VERSION 5.8 ;
BUSBITCHARS "[]" ;
DIVIDERCHAR "/" ;
UNITS
    DATABASE MICRONS 1000 ;
END UNITS

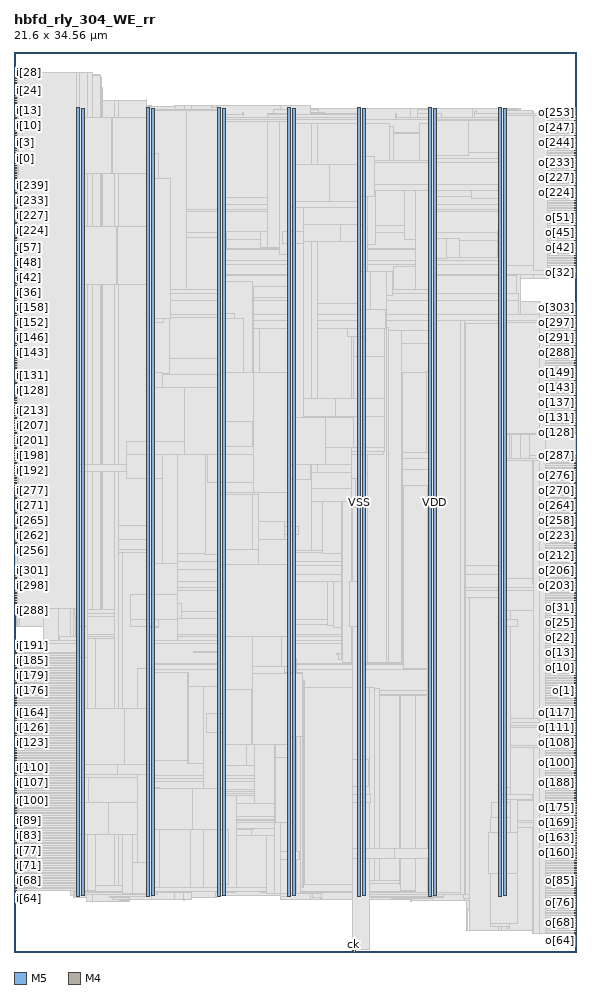
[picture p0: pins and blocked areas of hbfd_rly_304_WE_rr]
MACRO hbfd_rly_304_WE_rr
  FOREIGN hbfd_rly_304_WE_rr 0 0 ;
  CLASS BLOCK ;
  SIZE 21.6 BY 34.56 ;
  PIN ck
    DIRECTION INPUT ;
    USE SIGNAL ;
    PORT
      LAYER M5 ;
        RECT  13.008 0 13.032 0.084 ;
    END
  END ck
  PIN i[0]
    DIRECTION INPUT ;
    USE SIGNAL ;
    PORT
      LAYER M4 ;
        RECT  0 30.768 0.084 30.792 ;
    END
  END i[0]
  PIN i[100]
    DIRECTION INPUT ;
    USE SIGNAL ;
    PORT
      LAYER M4 ;
        RECT  0 5.808 0.084 5.832 ;
    END
  END i[100]
  PIN i[101]
    DIRECTION INPUT ;
    USE SIGNAL ;
    PORT
      LAYER M4 ;
        RECT  0 5.904 0.084 5.928 ;
    END
  END i[101]
  PIN i[102]
    DIRECTION INPUT ;
    USE SIGNAL ;
    PORT
      LAYER M4 ;
        RECT  0 6 0.084 6.024 ;
    END
  END i[102]
  PIN i[103]
    DIRECTION INPUT ;
    USE SIGNAL ;
    PORT
      LAYER M4 ;
        RECT  0 6.096 0.084 6.12 ;
    END
  END i[103]
  PIN i[104]
    DIRECTION INPUT ;
    USE SIGNAL ;
    PORT
      LAYER M4 ;
        RECT  0 6.192 0.084 6.216 ;
    END
  END i[104]
  PIN i[105]
    DIRECTION INPUT ;
    USE SIGNAL ;
    PORT
      LAYER M4 ;
        RECT  0 6.288 0.084 6.312 ;
    END
  END i[105]
  PIN i[106]
    DIRECTION INPUT ;
    USE SIGNAL ;
    PORT
      LAYER M4 ;
        RECT  0 6.384 0.084 6.408 ;
    END
  END i[106]
  PIN i[107]
    DIRECTION INPUT ;
    USE SIGNAL ;
    PORT
      LAYER M4 ;
        RECT  0 6.48 0.084 6.504 ;
    END
  END i[107]
  PIN i[108]
    DIRECTION INPUT ;
    USE SIGNAL ;
    PORT
      LAYER M4 ;
        RECT  0 6.576 0.084 6.6 ;
    END
  END i[108]
  PIN i[109]
    DIRECTION INPUT ;
    USE SIGNAL ;
    PORT
      LAYER M4 ;
        RECT  0 6.672 0.084 6.696 ;
    END
  END i[109]
  PIN i[10]
    DIRECTION INPUT ;
    USE SIGNAL ;
    PORT
      LAYER M4 ;
        RECT  0 31.728 0.084 31.752 ;
    END
  END i[10]
  PIN i[110]
    DIRECTION INPUT ;
    USE SIGNAL ;
    PORT
      LAYER M4 ;
        RECT  0 6.768 0.084 6.792 ;
    END
  END i[110]
  PIN i[111]
    DIRECTION INPUT ;
    USE SIGNAL ;
    PORT
      LAYER M4 ;
        RECT  0 6.864 0.084 6.888 ;
    END
  END i[111]
  PIN i[112]
    DIRECTION INPUT ;
    USE SIGNAL ;
    PORT
      LAYER M4 ;
        RECT  0 6.96 0.084 6.984 ;
    END
  END i[112]
  PIN i[113]
    DIRECTION INPUT ;
    USE SIGNAL ;
    PORT
      LAYER M4 ;
        RECT  0 7.056 0.084 7.08 ;
    END
  END i[113]
  PIN i[114]
    DIRECTION INPUT ;
    USE SIGNAL ;
    PORT
      LAYER M4 ;
        RECT  0 7.152 0.084 7.176 ;
    END
  END i[114]
  PIN i[115]
    DIRECTION INPUT ;
    USE SIGNAL ;
    PORT
      LAYER M4 ;
        RECT  0 7.248 0.084 7.272 ;
    END
  END i[115]
  PIN i[116]
    DIRECTION INPUT ;
    USE SIGNAL ;
    PORT
      LAYER M4 ;
        RECT  0 7.344 0.084 7.368 ;
    END
  END i[116]
  PIN i[117]
    DIRECTION INPUT ;
    USE SIGNAL ;
    PORT
      LAYER M4 ;
        RECT  0 7.44 0.084 7.464 ;
    END
  END i[117]
  PIN i[118]
    DIRECTION INPUT ;
    USE SIGNAL ;
    PORT
      LAYER M4 ;
        RECT  0 7.536 0.084 7.56 ;
    END
  END i[118]
  PIN i[119]
    DIRECTION INPUT ;
    USE SIGNAL ;
    PORT
      LAYER M4 ;
        RECT  0 7.632 0.084 7.656 ;
    END
  END i[119]
  PIN i[11]
    DIRECTION INPUT ;
    USE SIGNAL ;
    PORT
      LAYER M4 ;
        RECT  0 31.824 0.084 31.848 ;
    END
  END i[11]
  PIN i[120]
    DIRECTION INPUT ;
    USE SIGNAL ;
    PORT
      LAYER M4 ;
        RECT  0 7.728 0.084 7.752 ;
    END
  END i[120]
  PIN i[121]
    DIRECTION INPUT ;
    USE SIGNAL ;
    PORT
      LAYER M4 ;
        RECT  0 7.824 0.084 7.848 ;
    END
  END i[121]
  PIN i[122]
    DIRECTION INPUT ;
    USE SIGNAL ;
    PORT
      LAYER M4 ;
        RECT  0 7.92 0.084 7.944 ;
    END
  END i[122]
  PIN i[123]
    DIRECTION INPUT ;
    USE SIGNAL ;
    PORT
      LAYER M4 ;
        RECT  0 8.016 0.084 8.04 ;
    END
  END i[123]
  PIN i[124]
    DIRECTION INPUT ;
    USE SIGNAL ;
    PORT
      LAYER M4 ;
        RECT  0 8.112 0.084 8.136 ;
    END
  END i[124]
  PIN i[125]
    DIRECTION INPUT ;
    USE SIGNAL ;
    PORT
      LAYER M4 ;
        RECT  0 8.208 0.084 8.232 ;
    END
  END i[125]
  PIN i[126]
    DIRECTION INPUT ;
    USE SIGNAL ;
    PORT
      LAYER M4 ;
        RECT  0 8.304 0.084 8.328 ;
    END
  END i[126]
  PIN i[127]
    DIRECTION INPUT ;
    USE SIGNAL ;
    PORT
      LAYER M4 ;
        RECT  0 8.4 0.084 8.424 ;
    END
  END i[127]
  PIN i[128]
    DIRECTION INPUT ;
    USE SIGNAL ;
    PORT
      LAYER M4 ;
        RECT  0 21.552 0.084 21.576 ;
    END
  END i[128]
  PIN i[129]
    DIRECTION INPUT ;
    USE SIGNAL ;
    PORT
      LAYER M4 ;
        RECT  0 21.648 0.084 21.672 ;
    END
  END i[129]
  PIN i[12]
    DIRECTION INPUT ;
    USE SIGNAL ;
    PORT
      LAYER M4 ;
        RECT  0 31.92 0.084 31.944 ;
    END
  END i[12]
  PIN i[130]
    DIRECTION INPUT ;
    USE SIGNAL ;
    PORT
      LAYER M4 ;
        RECT  0 21.744 0.084 21.768 ;
    END
  END i[130]
  PIN i[131]
    DIRECTION INPUT ;
    USE SIGNAL ;
    PORT
      LAYER M4 ;
        RECT  0 21.84 0.084 21.864 ;
    END
  END i[131]
  PIN i[132]
    DIRECTION INPUT ;
    USE SIGNAL ;
    PORT
      LAYER M4 ;
        RECT  0 21.936 0.084 21.96 ;
    END
  END i[132]
  PIN i[133]
    DIRECTION INPUT ;
    USE SIGNAL ;
    PORT
      LAYER M4 ;
        RECT  0 22.032 0.084 22.056 ;
    END
  END i[133]
  PIN i[134]
    DIRECTION INPUT ;
    USE SIGNAL ;
    PORT
      LAYER M4 ;
        RECT  0 22.128 0.084 22.152 ;
    END
  END i[134]
  PIN i[135]
    DIRECTION INPUT ;
    USE SIGNAL ;
    PORT
      LAYER M4 ;
        RECT  0 22.224 0.084 22.248 ;
    END
  END i[135]
  PIN i[136]
    DIRECTION INPUT ;
    USE SIGNAL ;
    PORT
      LAYER M4 ;
        RECT  0 22.32 0.084 22.344 ;
    END
  END i[136]
  PIN i[137]
    DIRECTION INPUT ;
    USE SIGNAL ;
    PORT
      LAYER M4 ;
        RECT  0 22.416 0.084 22.44 ;
    END
  END i[137]
  PIN i[138]
    DIRECTION INPUT ;
    USE SIGNAL ;
    PORT
      LAYER M4 ;
        RECT  0 22.512 0.084 22.536 ;
    END
  END i[138]
  PIN i[139]
    DIRECTION INPUT ;
    USE SIGNAL ;
    PORT
      LAYER M4 ;
        RECT  0 22.608 0.084 22.632 ;
    END
  END i[139]
  PIN i[13]
    DIRECTION INPUT ;
    USE SIGNAL ;
    PORT
      LAYER M4 ;
        RECT  0 32.016 0.084 32.04 ;
    END
  END i[13]
  PIN i[140]
    DIRECTION INPUT ;
    USE SIGNAL ;
    PORT
      LAYER M4 ;
        RECT  0 22.704 0.084 22.728 ;
    END
  END i[140]
  PIN i[141]
    DIRECTION INPUT ;
    USE SIGNAL ;
    PORT
      LAYER M4 ;
        RECT  0 22.8 0.084 22.824 ;
    END
  END i[141]
  PIN i[142]
    DIRECTION INPUT ;
    USE SIGNAL ;
    PORT
      LAYER M4 ;
        RECT  0 22.896 0.084 22.92 ;
    END
  END i[142]
  PIN i[143]
    DIRECTION INPUT ;
    USE SIGNAL ;
    PORT
      LAYER M4 ;
        RECT  0 22.992 0.084 23.016 ;
    END
  END i[143]
  PIN i[144]
    DIRECTION INPUT ;
    USE SIGNAL ;
    PORT
      LAYER M4 ;
        RECT  0 23.088 0.084 23.112 ;
    END
  END i[144]
  PIN i[145]
    DIRECTION INPUT ;
    USE SIGNAL ;
    PORT
      LAYER M4 ;
        RECT  0 23.184 0.084 23.208 ;
    END
  END i[145]
  PIN i[146]
    DIRECTION INPUT ;
    USE SIGNAL ;
    PORT
      LAYER M4 ;
        RECT  0 23.28 0.084 23.304 ;
    END
  END i[146]
  PIN i[147]
    DIRECTION INPUT ;
    USE SIGNAL ;
    PORT
      LAYER M4 ;
        RECT  0 23.376 0.084 23.4 ;
    END
  END i[147]
  PIN i[148]
    DIRECTION INPUT ;
    USE SIGNAL ;
    PORT
      LAYER M4 ;
        RECT  0 23.472 0.084 23.496 ;
    END
  END i[148]
  PIN i[149]
    DIRECTION INPUT ;
    USE SIGNAL ;
    PORT
      LAYER M4 ;
        RECT  0 23.568 0.084 23.592 ;
    END
  END i[149]
  PIN i[14]
    DIRECTION INPUT ;
    USE SIGNAL ;
    PORT
      LAYER M4 ;
        RECT  0 32.112 0.084 32.136 ;
    END
  END i[14]
  PIN i[150]
    DIRECTION INPUT ;
    USE SIGNAL ;
    PORT
      LAYER M4 ;
        RECT  0 23.664 0.084 23.688 ;
    END
  END i[150]
  PIN i[151]
    DIRECTION INPUT ;
    USE SIGNAL ;
    PORT
      LAYER M4 ;
        RECT  0 23.76 0.084 23.784 ;
    END
  END i[151]
  PIN i[152]
    DIRECTION INPUT ;
    USE SIGNAL ;
    PORT
      LAYER M4 ;
        RECT  0 23.856 0.084 23.88 ;
    END
  END i[152]
  PIN i[153]
    DIRECTION INPUT ;
    USE SIGNAL ;
    PORT
      LAYER M4 ;
        RECT  0 23.952 0.084 23.976 ;
    END
  END i[153]
  PIN i[154]
    DIRECTION INPUT ;
    USE SIGNAL ;
    PORT
      LAYER M4 ;
        RECT  0 24.048 0.084 24.072 ;
    END
  END i[154]
  PIN i[155]
    DIRECTION INPUT ;
    USE SIGNAL ;
    PORT
      LAYER M4 ;
        RECT  0 24.144 0.084 24.168 ;
    END
  END i[155]
  PIN i[156]
    DIRECTION INPUT ;
    USE SIGNAL ;
    PORT
      LAYER M4 ;
        RECT  0 24.24 0.084 24.264 ;
    END
  END i[156]
  PIN i[157]
    DIRECTION INPUT ;
    USE SIGNAL ;
    PORT
      LAYER M4 ;
        RECT  0 24.336 0.084 24.36 ;
    END
  END i[157]
  PIN i[158]
    DIRECTION INPUT ;
    USE SIGNAL ;
    PORT
      LAYER M4 ;
        RECT  0 24.432 0.084 24.456 ;
    END
  END i[158]
  PIN i[159]
    DIRECTION INPUT ;
    USE SIGNAL ;
    PORT
      LAYER M4 ;
        RECT  0 24.528 0.084 24.552 ;
    END
  END i[159]
  PIN i[15]
    DIRECTION INPUT ;
    USE SIGNAL ;
    PORT
      LAYER M4 ;
        RECT  0 32.208 0.084 32.232 ;
    END
  END i[15]
  PIN i[160]
    DIRECTION INPUT ;
    USE SIGNAL ;
    PORT
      LAYER M4 ;
        RECT  0 8.496 0.084 8.52 ;
    END
  END i[160]
  PIN i[161]
    DIRECTION INPUT ;
    USE SIGNAL ;
    PORT
      LAYER M4 ;
        RECT  0 8.592 0.084 8.616 ;
    END
  END i[161]
  PIN i[162]
    DIRECTION INPUT ;
    USE SIGNAL ;
    PORT
      LAYER M4 ;
        RECT  0 8.688 0.084 8.712 ;
    END
  END i[162]
  PIN i[163]
    DIRECTION INPUT ;
    USE SIGNAL ;
    PORT
      LAYER M4 ;
        RECT  0 8.784 0.084 8.808 ;
    END
  END i[163]
  PIN i[164]
    DIRECTION INPUT ;
    USE SIGNAL ;
    PORT
      LAYER M4 ;
        RECT  0 8.88 0.084 8.904 ;
    END
  END i[164]
  PIN i[165]
    DIRECTION INPUT ;
    USE SIGNAL ;
    PORT
      LAYER M4 ;
        RECT  0 8.976 0.084 9 ;
    END
  END i[165]
  PIN i[166]
    DIRECTION INPUT ;
    USE SIGNAL ;
    PORT
      LAYER M4 ;
        RECT  0 9.072 0.084 9.096 ;
    END
  END i[166]
  PIN i[167]
    DIRECTION INPUT ;
    USE SIGNAL ;
    PORT
      LAYER M4 ;
        RECT  0 9.168 0.084 9.192 ;
    END
  END i[167]
  PIN i[168]
    DIRECTION INPUT ;
    USE SIGNAL ;
    PORT
      LAYER M4 ;
        RECT  0 9.264 0.084 9.288 ;
    END
  END i[168]
  PIN i[169]
    DIRECTION INPUT ;
    USE SIGNAL ;
    PORT
      LAYER M4 ;
        RECT  0 9.36 0.084 9.384 ;
    END
  END i[169]
  PIN i[16]
    DIRECTION INPUT ;
    USE SIGNAL ;
    PORT
      LAYER M4 ;
        RECT  0 32.304 0.084 32.328 ;
    END
  END i[16]
  PIN i[170]
    DIRECTION INPUT ;
    USE SIGNAL ;
    PORT
      LAYER M4 ;
        RECT  0 9.456 0.084 9.48 ;
    END
  END i[170]
  PIN i[171]
    DIRECTION INPUT ;
    USE SIGNAL ;
    PORT
      LAYER M4 ;
        RECT  0 9.552 0.084 9.576 ;
    END
  END i[171]
  PIN i[172]
    DIRECTION INPUT ;
    USE SIGNAL ;
    PORT
      LAYER M4 ;
        RECT  0 9.648 0.084 9.672 ;
    END
  END i[172]
  PIN i[173]
    DIRECTION INPUT ;
    USE SIGNAL ;
    PORT
      LAYER M4 ;
        RECT  0 9.744 0.084 9.768 ;
    END
  END i[173]
  PIN i[174]
    DIRECTION INPUT ;
    USE SIGNAL ;
    PORT
      LAYER M4 ;
        RECT  0 9.84 0.084 9.864 ;
    END
  END i[174]
  PIN i[175]
    DIRECTION INPUT ;
    USE SIGNAL ;
    PORT
      LAYER M4 ;
        RECT  0 9.936 0.084 9.96 ;
    END
  END i[175]
  PIN i[176]
    DIRECTION INPUT ;
    USE SIGNAL ;
    PORT
      LAYER M4 ;
        RECT  0 10.032 0.084 10.056 ;
    END
  END i[176]
  PIN i[177]
    DIRECTION INPUT ;
    USE SIGNAL ;
    PORT
      LAYER M4 ;
        RECT  0 10.128 0.084 10.152 ;
    END
  END i[177]
  PIN i[178]
    DIRECTION INPUT ;
    USE SIGNAL ;
    PORT
      LAYER M4 ;
        RECT  0 10.224 0.084 10.248 ;
    END
  END i[178]
  PIN i[179]
    DIRECTION INPUT ;
    USE SIGNAL ;
    PORT
      LAYER M4 ;
        RECT  0 10.32 0.084 10.344 ;
    END
  END i[179]
  PIN i[17]
    DIRECTION INPUT ;
    USE SIGNAL ;
    PORT
      LAYER M4 ;
        RECT  0 32.4 0.084 32.424 ;
    END
  END i[17]
  PIN i[180]
    DIRECTION INPUT ;
    USE SIGNAL ;
    PORT
      LAYER M4 ;
        RECT  0 10.416 0.084 10.44 ;
    END
  END i[180]
  PIN i[181]
    DIRECTION INPUT ;
    USE SIGNAL ;
    PORT
      LAYER M4 ;
        RECT  0 10.512 0.084 10.536 ;
    END
  END i[181]
  PIN i[182]
    DIRECTION INPUT ;
    USE SIGNAL ;
    PORT
      LAYER M4 ;
        RECT  0 10.608 0.084 10.632 ;
    END
  END i[182]
  PIN i[183]
    DIRECTION INPUT ;
    USE SIGNAL ;
    PORT
      LAYER M4 ;
        RECT  0 10.704 0.084 10.728 ;
    END
  END i[183]
  PIN i[184]
    DIRECTION INPUT ;
    USE SIGNAL ;
    PORT
      LAYER M4 ;
        RECT  0 10.8 0.084 10.824 ;
    END
  END i[184]
  PIN i[185]
    DIRECTION INPUT ;
    USE SIGNAL ;
    PORT
      LAYER M4 ;
        RECT  0 10.896 0.084 10.92 ;
    END
  END i[185]
  PIN i[186]
    DIRECTION INPUT ;
    USE SIGNAL ;
    PORT
      LAYER M4 ;
        RECT  0 10.992 0.084 11.016 ;
    END
  END i[186]
  PIN i[187]
    DIRECTION INPUT ;
    USE SIGNAL ;
    PORT
      LAYER M4 ;
        RECT  0 11.088 0.084 11.112 ;
    END
  END i[187]
  PIN i[188]
    DIRECTION INPUT ;
    USE SIGNAL ;
    PORT
      LAYER M4 ;
        RECT  0 11.184 0.084 11.208 ;
    END
  END i[188]
  PIN i[189]
    DIRECTION INPUT ;
    USE SIGNAL ;
    PORT
      LAYER M4 ;
        RECT  0 11.28 0.084 11.304 ;
    END
  END i[189]
  PIN i[18]
    DIRECTION INPUT ;
    USE SIGNAL ;
    PORT
      LAYER M4 ;
        RECT  0 32.496 0.084 32.52 ;
    END
  END i[18]
  PIN i[190]
    DIRECTION INPUT ;
    USE SIGNAL ;
    PORT
      LAYER M4 ;
        RECT  0 11.376 0.084 11.4 ;
    END
  END i[190]
  PIN i[191]
    DIRECTION INPUT ;
    USE SIGNAL ;
    PORT
      LAYER M4 ;
        RECT  0 11.472 0.084 11.496 ;
    END
  END i[191]
  PIN i[192]
    DIRECTION INPUT ;
    USE SIGNAL ;
    PORT
      LAYER M4 ;
        RECT  0 18.48 0.084 18.504 ;
    END
  END i[192]
  PIN i[193]
    DIRECTION INPUT ;
    USE SIGNAL ;
    PORT
      LAYER M4 ;
        RECT  0 18.576 0.084 18.6 ;
    END
  END i[193]
  PIN i[194]
    DIRECTION INPUT ;
    USE SIGNAL ;
    PORT
      LAYER M4 ;
        RECT  0 18.672 0.084 18.696 ;
    END
  END i[194]
  PIN i[195]
    DIRECTION INPUT ;
    USE SIGNAL ;
    PORT
      LAYER M4 ;
        RECT  0 18.768 0.084 18.792 ;
    END
  END i[195]
  PIN i[196]
    DIRECTION INPUT ;
    USE SIGNAL ;
    PORT
      LAYER M4 ;
        RECT  0 18.864 0.084 18.888 ;
    END
  END i[196]
  PIN i[197]
    DIRECTION INPUT ;
    USE SIGNAL ;
    PORT
      LAYER M4 ;
        RECT  0 18.96 0.084 18.984 ;
    END
  END i[197]
  PIN i[198]
    DIRECTION INPUT ;
    USE SIGNAL ;
    PORT
      LAYER M4 ;
        RECT  0 19.056 0.084 19.08 ;
    END
  END i[198]
  PIN i[199]
    DIRECTION INPUT ;
    USE SIGNAL ;
    PORT
      LAYER M4 ;
        RECT  0 19.152 0.084 19.176 ;
    END
  END i[199]
  PIN i[19]
    DIRECTION INPUT ;
    USE SIGNAL ;
    PORT
      LAYER M4 ;
        RECT  0 32.592 0.084 32.616 ;
    END
  END i[19]
  PIN i[1]
    DIRECTION INPUT ;
    USE SIGNAL ;
    PORT
      LAYER M4 ;
        RECT  0 30.864 0.084 30.888 ;
    END
  END i[1]
  PIN i[200]
    DIRECTION INPUT ;
    USE SIGNAL ;
    PORT
      LAYER M4 ;
        RECT  0 19.248 0.084 19.272 ;
    END
  END i[200]
  PIN i[201]
    DIRECTION INPUT ;
    USE SIGNAL ;
    PORT
      LAYER M4 ;
        RECT  0 19.344 0.084 19.368 ;
    END
  END i[201]
  PIN i[202]
    DIRECTION INPUT ;
    USE SIGNAL ;
    PORT
      LAYER M4 ;
        RECT  0 19.44 0.084 19.464 ;
    END
  END i[202]
  PIN i[203]
    DIRECTION INPUT ;
    USE SIGNAL ;
    PORT
      LAYER M4 ;
        RECT  0 19.536 0.084 19.56 ;
    END
  END i[203]
  PIN i[204]
    DIRECTION INPUT ;
    USE SIGNAL ;
    PORT
      LAYER M4 ;
        RECT  0 19.632 0.084 19.656 ;
    END
  END i[204]
  PIN i[205]
    DIRECTION INPUT ;
    USE SIGNAL ;
    PORT
      LAYER M4 ;
        RECT  0 19.728 0.084 19.752 ;
    END
  END i[205]
  PIN i[206]
    DIRECTION INPUT ;
    USE SIGNAL ;
    PORT
      LAYER M4 ;
        RECT  0 19.824 0.084 19.848 ;
    END
  END i[206]
  PIN i[207]
    DIRECTION INPUT ;
    USE SIGNAL ;
    PORT
      LAYER M4 ;
        RECT  0 19.92 0.084 19.944 ;
    END
  END i[207]
  PIN i[208]
    DIRECTION INPUT ;
    USE SIGNAL ;
    PORT
      LAYER M4 ;
        RECT  0 20.016 0.084 20.04 ;
    END
  END i[208]
  PIN i[209]
    DIRECTION INPUT ;
    USE SIGNAL ;
    PORT
      LAYER M4 ;
        RECT  0 20.112 0.084 20.136 ;
    END
  END i[209]
  PIN i[20]
    DIRECTION INPUT ;
    USE SIGNAL ;
    PORT
      LAYER M4 ;
        RECT  0 32.688 0.084 32.712 ;
    END
  END i[20]
  PIN i[210]
    DIRECTION INPUT ;
    USE SIGNAL ;
    PORT
      LAYER M4 ;
        RECT  0 20.208 0.084 20.232 ;
    END
  END i[210]
  PIN i[211]
    DIRECTION INPUT ;
    USE SIGNAL ;
    PORT
      LAYER M4 ;
        RECT  0 20.304 0.084 20.328 ;
    END
  END i[211]
  PIN i[212]
    DIRECTION INPUT ;
    USE SIGNAL ;
    PORT
      LAYER M4 ;
        RECT  0 20.4 0.084 20.424 ;
    END
  END i[212]
  PIN i[213]
    DIRECTION INPUT ;
    USE SIGNAL ;
    PORT
      LAYER M4 ;
        RECT  0 20.496 0.084 20.52 ;
    END
  END i[213]
  PIN i[214]
    DIRECTION INPUT ;
    USE SIGNAL ;
    PORT
      LAYER M4 ;
        RECT  0 20.592 0.084 20.616 ;
    END
  END i[214]
  PIN i[215]
    DIRECTION INPUT ;
    USE SIGNAL ;
    PORT
      LAYER M4 ;
        RECT  0 20.688 0.084 20.712 ;
    END
  END i[215]
  PIN i[216]
    DIRECTION INPUT ;
    USE SIGNAL ;
    PORT
      LAYER M4 ;
        RECT  0 20.784 0.084 20.808 ;
    END
  END i[216]
  PIN i[217]
    DIRECTION INPUT ;
    USE SIGNAL ;
    PORT
      LAYER M4 ;
        RECT  0 20.88 0.084 20.904 ;
    END
  END i[217]
  PIN i[218]
    DIRECTION INPUT ;
    USE SIGNAL ;
    PORT
      LAYER M4 ;
        RECT  0 20.976 0.084 21 ;
    END
  END i[218]
  PIN i[219]
    DIRECTION INPUT ;
    USE SIGNAL ;
    PORT
      LAYER M4 ;
        RECT  0 21.072 0.084 21.096 ;
    END
  END i[219]
  PIN i[21]
    DIRECTION INPUT ;
    USE SIGNAL ;
    PORT
      LAYER M4 ;
        RECT  0 32.784 0.084 32.808 ;
    END
  END i[21]
  PIN i[220]
    DIRECTION INPUT ;
    USE SIGNAL ;
    PORT
      LAYER M4 ;
        RECT  0 21.168 0.084 21.192 ;
    END
  END i[220]
  PIN i[221]
    DIRECTION INPUT ;
    USE SIGNAL ;
    PORT
      LAYER M4 ;
        RECT  0 21.264 0.084 21.288 ;
    END
  END i[221]
  PIN i[222]
    DIRECTION INPUT ;
    USE SIGNAL ;
    PORT
      LAYER M4 ;
        RECT  0 21.36 0.084 21.384 ;
    END
  END i[222]
  PIN i[223]
    DIRECTION INPUT ;
    USE SIGNAL ;
    PORT
      LAYER M4 ;
        RECT  0 21.456 0.084 21.48 ;
    END
  END i[223]
  PIN i[224]
    DIRECTION INPUT ;
    USE SIGNAL ;
    PORT
      LAYER M4 ;
        RECT  0 27.696 0.084 27.72 ;
    END
  END i[224]
  PIN i[225]
    DIRECTION INPUT ;
    USE SIGNAL ;
    PORT
      LAYER M4 ;
        RECT  0 27.792 0.084 27.816 ;
    END
  END i[225]
  PIN i[226]
    DIRECTION INPUT ;
    USE SIGNAL ;
    PORT
      LAYER M4 ;
        RECT  0 27.888 0.084 27.912 ;
    END
  END i[226]
  PIN i[227]
    DIRECTION INPUT ;
    USE SIGNAL ;
    PORT
      LAYER M4 ;
        RECT  0 27.984 0.084 28.008 ;
    END
  END i[227]
  PIN i[228]
    DIRECTION INPUT ;
    USE SIGNAL ;
    PORT
      LAYER M4 ;
        RECT  0 28.08 0.084 28.104 ;
    END
  END i[228]
  PIN i[229]
    DIRECTION INPUT ;
    USE SIGNAL ;
    PORT
      LAYER M4 ;
        RECT  0 28.176 0.084 28.2 ;
    END
  END i[229]
  PIN i[22]
    DIRECTION INPUT ;
    USE SIGNAL ;
    PORT
      LAYER M4 ;
        RECT  0 32.88 0.084 32.904 ;
    END
  END i[22]
  PIN i[230]
    DIRECTION INPUT ;
    USE SIGNAL ;
    PORT
      LAYER M4 ;
        RECT  0 28.272 0.084 28.296 ;
    END
  END i[230]
  PIN i[231]
    DIRECTION INPUT ;
    USE SIGNAL ;
    PORT
      LAYER M4 ;
        RECT  0 28.368 0.084 28.392 ;
    END
  END i[231]
  PIN i[232]
    DIRECTION INPUT ;
    USE SIGNAL ;
    PORT
      LAYER M4 ;
        RECT  0 28.464 0.084 28.488 ;
    END
  END i[232]
  PIN i[233]
    DIRECTION INPUT ;
    USE SIGNAL ;
    PORT
      LAYER M4 ;
        RECT  0 28.56 0.084 28.584 ;
    END
  END i[233]
  PIN i[234]
    DIRECTION INPUT ;
    USE SIGNAL ;
    PORT
      LAYER M4 ;
        RECT  0 28.656 0.084 28.68 ;
    END
  END i[234]
  PIN i[235]
    DIRECTION INPUT ;
    USE SIGNAL ;
    PORT
      LAYER M4 ;
        RECT  0 28.752 0.084 28.776 ;
    END
  END i[235]
  PIN i[236]
    DIRECTION INPUT ;
    USE SIGNAL ;
    PORT
      LAYER M4 ;
        RECT  0 28.848 0.084 28.872 ;
    END
  END i[236]
  PIN i[237]
    DIRECTION INPUT ;
    USE SIGNAL ;
    PORT
      LAYER M4 ;
        RECT  0 28.944 0.084 28.968 ;
    END
  END i[237]
  PIN i[238]
    DIRECTION INPUT ;
    USE SIGNAL ;
    PORT
      LAYER M4 ;
        RECT  0 29.04 0.084 29.064 ;
    END
  END i[238]
  PIN i[239]
    DIRECTION INPUT ;
    USE SIGNAL ;
    PORT
      LAYER M4 ;
        RECT  0 29.136 0.084 29.16 ;
    END
  END i[239]
  PIN i[23]
    DIRECTION INPUT ;
    USE SIGNAL ;
    PORT
      LAYER M4 ;
        RECT  0 32.976 0.084 33 ;
    END
  END i[23]
  PIN i[240]
    DIRECTION INPUT ;
    USE SIGNAL ;
    PORT
      LAYER M4 ;
        RECT  0 29.232 0.084 29.256 ;
    END
  END i[240]
  PIN i[241]
    DIRECTION INPUT ;
    USE SIGNAL ;
    PORT
      LAYER M4 ;
        RECT  0 29.328 0.084 29.352 ;
    END
  END i[241]
  PIN i[242]
    DIRECTION INPUT ;
    USE SIGNAL ;
    PORT
      LAYER M4 ;
        RECT  0 29.424 0.084 29.448 ;
    END
  END i[242]
  PIN i[243]
    DIRECTION INPUT ;
    USE SIGNAL ;
    PORT
      LAYER M4 ;
        RECT  0 29.52 0.084 29.544 ;
    END
  END i[243]
  PIN i[244]
    DIRECTION INPUT ;
    USE SIGNAL ;
    PORT
      LAYER M4 ;
        RECT  0 29.616 0.084 29.64 ;
    END
  END i[244]
  PIN i[245]
    DIRECTION INPUT ;
    USE SIGNAL ;
    PORT
      LAYER M4 ;
        RECT  0 29.712 0.084 29.736 ;
    END
  END i[245]
  PIN i[246]
    DIRECTION INPUT ;
    USE SIGNAL ;
    PORT
      LAYER M4 ;
        RECT  0 29.808 0.084 29.832 ;
    END
  END i[246]
  PIN i[247]
    DIRECTION INPUT ;
    USE SIGNAL ;
    PORT
      LAYER M4 ;
        RECT  0 29.904 0.084 29.928 ;
    END
  END i[247]
  PIN i[248]
    DIRECTION INPUT ;
    USE SIGNAL ;
    PORT
      LAYER M4 ;
        RECT  0 30 0.084 30.024 ;
    END
  END i[248]
  PIN i[249]
    DIRECTION INPUT ;
    USE SIGNAL ;
    PORT
      LAYER M4 ;
        RECT  0 30.096 0.084 30.12 ;
    END
  END i[249]
  PIN i[24]
    DIRECTION INPUT ;
    USE SIGNAL ;
    PORT
      LAYER M4 ;
        RECT  0 33.072 0.084 33.096 ;
    END
  END i[24]
  PIN i[250]
    DIRECTION INPUT ;
    USE SIGNAL ;
    PORT
      LAYER M4 ;
        RECT  0 30.192 0.084 30.216 ;
    END
  END i[250]
  PIN i[251]
    DIRECTION INPUT ;
    USE SIGNAL ;
    PORT
      LAYER M4 ;
        RECT  0 30.288 0.084 30.312 ;
    END
  END i[251]
  PIN i[252]
    DIRECTION INPUT ;
    USE SIGNAL ;
    PORT
      LAYER M4 ;
        RECT  0 30.384 0.084 30.408 ;
    END
  END i[252]
  PIN i[253]
    DIRECTION INPUT ;
    USE SIGNAL ;
    PORT
      LAYER M4 ;
        RECT  0 30.48 0.084 30.504 ;
    END
  END i[253]
  PIN i[254]
    DIRECTION INPUT ;
    USE SIGNAL ;
    PORT
      LAYER M4 ;
        RECT  0 30.576 0.084 30.6 ;
    END
  END i[254]
  PIN i[255]
    DIRECTION INPUT ;
    USE SIGNAL ;
    PORT
      LAYER M4 ;
        RECT  0 30.672 0.084 30.696 ;
    END
  END i[255]
  PIN i[256]
    DIRECTION INPUT ;
    USE SIGNAL ;
    PORT
      LAYER M4 ;
        RECT  0 15.408 0.084 15.432 ;
    END
  END i[256]
  PIN i[257]
    DIRECTION INPUT ;
    USE SIGNAL ;
    PORT
      LAYER M4 ;
        RECT  0 15.504 0.084 15.528 ;
    END
  END i[257]
  PIN i[258]
    DIRECTION INPUT ;
    USE SIGNAL ;
    PORT
      LAYER M4 ;
        RECT  0 15.6 0.084 15.624 ;
    END
  END i[258]
  PIN i[259]
    DIRECTION INPUT ;
    USE SIGNAL ;
    PORT
      LAYER M4 ;
        RECT  0 15.696 0.084 15.72 ;
    END
  END i[259]
  PIN i[25]
    DIRECTION INPUT ;
    USE SIGNAL ;
    PORT
      LAYER M4 ;
        RECT  0 33.168 0.084 33.192 ;
    END
  END i[25]
  PIN i[260]
    DIRECTION INPUT ;
    USE SIGNAL ;
    PORT
      LAYER M4 ;
        RECT  0 15.792 0.084 15.816 ;
    END
  END i[260]
  PIN i[261]
    DIRECTION INPUT ;
    USE SIGNAL ;
    PORT
      LAYER M4 ;
        RECT  0 15.888 0.084 15.912 ;
    END
  END i[261]
  PIN i[262]
    DIRECTION INPUT ;
    USE SIGNAL ;
    PORT
      LAYER M4 ;
        RECT  0 15.984 0.084 16.008 ;
    END
  END i[262]
  PIN i[263]
    DIRECTION INPUT ;
    USE SIGNAL ;
    PORT
      LAYER M4 ;
        RECT  0 16.08 0.084 16.104 ;
    END
  END i[263]
  PIN i[264]
    DIRECTION INPUT ;
    USE SIGNAL ;
    PORT
      LAYER M4 ;
        RECT  0 16.176 0.084 16.2 ;
    END
  END i[264]
  PIN i[265]
    DIRECTION INPUT ;
    USE SIGNAL ;
    PORT
      LAYER M4 ;
        RECT  0 16.272 0.084 16.296 ;
    END
  END i[265]
  PIN i[266]
    DIRECTION INPUT ;
    USE SIGNAL ;
    PORT
      LAYER M4 ;
        RECT  0 16.368 0.084 16.392 ;
    END
  END i[266]
  PIN i[267]
    DIRECTION INPUT ;
    USE SIGNAL ;
    PORT
      LAYER M4 ;
        RECT  0 16.464 0.084 16.488 ;
    END
  END i[267]
  PIN i[268]
    DIRECTION INPUT ;
    USE SIGNAL ;
    PORT
      LAYER M4 ;
        RECT  0 16.56 0.084 16.584 ;
    END
  END i[268]
  PIN i[269]
    DIRECTION INPUT ;
    USE SIGNAL ;
    PORT
      LAYER M4 ;
        RECT  0 16.656 0.084 16.68 ;
    END
  END i[269]
  PIN i[26]
    DIRECTION INPUT ;
    USE SIGNAL ;
    PORT
      LAYER M4 ;
        RECT  0 33.264 0.084 33.288 ;
    END
  END i[26]
  PIN i[270]
    DIRECTION INPUT ;
    USE SIGNAL ;
    PORT
      LAYER M4 ;
        RECT  0 16.752 0.084 16.776 ;
    END
  END i[270]
  PIN i[271]
    DIRECTION INPUT ;
    USE SIGNAL ;
    PORT
      LAYER M4 ;
        RECT  0 16.848 0.084 16.872 ;
    END
  END i[271]
  PIN i[272]
    DIRECTION INPUT ;
    USE SIGNAL ;
    PORT
      LAYER M4 ;
        RECT  0 16.944 0.084 16.968 ;
    END
  END i[272]
  PIN i[273]
    DIRECTION INPUT ;
    USE SIGNAL ;
    PORT
      LAYER M4 ;
        RECT  0 17.04 0.084 17.064 ;
    END
  END i[273]
  PIN i[274]
    DIRECTION INPUT ;
    USE SIGNAL ;
    PORT
      LAYER M4 ;
        RECT  0 17.136 0.084 17.16 ;
    END
  END i[274]
  PIN i[275]
    DIRECTION INPUT ;
    USE SIGNAL ;
    PORT
      LAYER M4 ;
        RECT  0 17.232 0.084 17.256 ;
    END
  END i[275]
  PIN i[276]
    DIRECTION INPUT ;
    USE SIGNAL ;
    PORT
      LAYER M4 ;
        RECT  0 17.328 0.084 17.352 ;
    END
  END i[276]
  PIN i[277]
    DIRECTION INPUT ;
    USE SIGNAL ;
    PORT
      LAYER M4 ;
        RECT  0 17.424 0.084 17.448 ;
    END
  END i[277]
  PIN i[278]
    DIRECTION INPUT ;
    USE SIGNAL ;
    PORT
      LAYER M4 ;
        RECT  0 17.52 0.084 17.544 ;
    END
  END i[278]
  PIN i[279]
    DIRECTION INPUT ;
    USE SIGNAL ;
    PORT
      LAYER M4 ;
        RECT  0 17.616 0.084 17.64 ;
    END
  END i[279]
  PIN i[27]
    DIRECTION INPUT ;
    USE SIGNAL ;
    PORT
      LAYER M4 ;
        RECT  0 33.36 0.084 33.384 ;
    END
  END i[27]
  PIN i[280]
    DIRECTION INPUT ;
    USE SIGNAL ;
    PORT
      LAYER M4 ;
        RECT  0 17.712 0.084 17.736 ;
    END
  END i[280]
  PIN i[281]
    DIRECTION INPUT ;
    USE SIGNAL ;
    PORT
      LAYER M4 ;
        RECT  0 17.808 0.084 17.832 ;
    END
  END i[281]
  PIN i[282]
    DIRECTION INPUT ;
    USE SIGNAL ;
    PORT
      LAYER M4 ;
        RECT  0 17.904 0.084 17.928 ;
    END
  END i[282]
  PIN i[283]
    DIRECTION INPUT ;
    USE SIGNAL ;
    PORT
      LAYER M4 ;
        RECT  0 18 0.084 18.024 ;
    END
  END i[283]
  PIN i[284]
    DIRECTION INPUT ;
    USE SIGNAL ;
    PORT
      LAYER M4 ;
        RECT  0 18.096 0.084 18.12 ;
    END
  END i[284]
  PIN i[285]
    DIRECTION INPUT ;
    USE SIGNAL ;
    PORT
      LAYER M4 ;
        RECT  0 18.192 0.084 18.216 ;
    END
  END i[285]
  PIN i[286]
    DIRECTION INPUT ;
    USE SIGNAL ;
    PORT
      LAYER M4 ;
        RECT  0 18.288 0.084 18.312 ;
    END
  END i[286]
  PIN i[287]
    DIRECTION INPUT ;
    USE SIGNAL ;
    PORT
      LAYER M4 ;
        RECT  0 18.384 0.084 18.408 ;
    END
  END i[287]
  PIN i[288]
    DIRECTION INPUT ;
    USE SIGNAL ;
    PORT
      LAYER M4 ;
        RECT  0 13.104 0.084 13.128 ;
    END
  END i[288]
  PIN i[289]
    DIRECTION INPUT ;
    USE SIGNAL ;
    PORT
      LAYER M4 ;
        RECT  0 13.2 0.084 13.224 ;
    END
  END i[289]
  PIN i[28]
    DIRECTION INPUT ;
    USE SIGNAL ;
    PORT
      LAYER M4 ;
        RECT  0 33.456 0.084 33.48 ;
    END
  END i[28]
  PIN i[290]
    DIRECTION INPUT ;
    USE SIGNAL ;
    PORT
      LAYER M4 ;
        RECT  0 13.296 0.084 13.32 ;
    END
  END i[290]
  PIN i[291]
    DIRECTION INPUT ;
    USE SIGNAL ;
    PORT
      LAYER M4 ;
        RECT  0 13.392 0.084 13.416 ;
    END
  END i[291]
  PIN i[292]
    DIRECTION INPUT ;
    USE SIGNAL ;
    PORT
      LAYER M4 ;
        RECT  0 13.488 0.084 13.512 ;
    END
  END i[292]
  PIN i[293]
    DIRECTION INPUT ;
    USE SIGNAL ;
    PORT
      LAYER M4 ;
        RECT  0 13.584 0.084 13.608 ;
    END
  END i[293]
  PIN i[294]
    DIRECTION INPUT ;
    USE SIGNAL ;
    PORT
      LAYER M4 ;
        RECT  0 13.68 0.084 13.704 ;
    END
  END i[294]
  PIN i[295]
    DIRECTION INPUT ;
    USE SIGNAL ;
    PORT
      LAYER M4 ;
        RECT  0 13.776 0.084 13.8 ;
    END
  END i[295]
  PIN i[296]
    DIRECTION INPUT ;
    USE SIGNAL ;
    PORT
      LAYER M4 ;
        RECT  0 13.872 0.084 13.896 ;
    END
  END i[296]
  PIN i[297]
    DIRECTION INPUT ;
    USE SIGNAL ;
    PORT
      LAYER M4 ;
        RECT  0 13.968 0.084 13.992 ;
    END
  END i[297]
  PIN i[298]
    DIRECTION INPUT ;
    USE SIGNAL ;
    PORT
      LAYER M4 ;
        RECT  0 14.064 0.084 14.088 ;
    END
  END i[298]
  PIN i[299]
    DIRECTION INPUT ;
    USE SIGNAL ;
    PORT
      LAYER M4 ;
        RECT  0 14.16 0.084 14.184 ;
    END
  END i[299]
  PIN i[29]
    DIRECTION INPUT ;
    USE SIGNAL ;
    PORT
      LAYER M4 ;
        RECT  0 33.552 0.084 33.576 ;
    END
  END i[29]
  PIN i[2]
    DIRECTION INPUT ;
    USE SIGNAL ;
    PORT
      LAYER M4 ;
        RECT  0 30.96 0.084 30.984 ;
    END
  END i[2]
  PIN i[300]
    DIRECTION INPUT ;
    USE SIGNAL ;
    PORT
      LAYER M4 ;
        RECT  0 14.256 0.084 14.28 ;
    END
  END i[300]
  PIN i[301]
    DIRECTION INPUT ;
    USE SIGNAL ;
    PORT
      LAYER M4 ;
        RECT  0 14.352 0.084 14.376 ;
    END
  END i[301]
  PIN i[302]
    DIRECTION INPUT ;
    USE SIGNAL ;
    PORT
      LAYER M4 ;
        RECT  0 14.448 0.084 14.472 ;
    END
  END i[302]
  PIN i[303]
    DIRECTION INPUT ;
    USE SIGNAL ;
    PORT
      LAYER M4 ;
        RECT  0 14.544 0.084 14.568 ;
    END
  END i[303]
  PIN i[30]
    DIRECTION INPUT ;
    USE SIGNAL ;
    PORT
      LAYER M4 ;
        RECT  0 33.648 0.084 33.672 ;
    END
  END i[30]
  PIN i[31]
    DIRECTION INPUT ;
    USE SIGNAL ;
    PORT
      LAYER M4 ;
        RECT  0 33.744 0.084 33.768 ;
    END
  END i[31]
  PIN i[32]
    DIRECTION INPUT ;
    USE SIGNAL ;
    PORT
      LAYER M4 ;
        RECT  0 24.624 0.084 24.648 ;
    END
  END i[32]
  PIN i[33]
    DIRECTION INPUT ;
    USE SIGNAL ;
    PORT
      LAYER M4 ;
        RECT  0 24.72 0.084 24.744 ;
    END
  END i[33]
  PIN i[34]
    DIRECTION INPUT ;
    USE SIGNAL ;
    PORT
      LAYER M4 ;
        RECT  0 24.816 0.084 24.84 ;
    END
  END i[34]
  PIN i[35]
    DIRECTION INPUT ;
    USE SIGNAL ;
    PORT
      LAYER M4 ;
        RECT  0 24.912 0.084 24.936 ;
    END
  END i[35]
  PIN i[36]
    DIRECTION INPUT ;
    USE SIGNAL ;
    PORT
      LAYER M4 ;
        RECT  0 25.008 0.084 25.032 ;
    END
  END i[36]
  PIN i[37]
    DIRECTION INPUT ;
    USE SIGNAL ;
    PORT
      LAYER M4 ;
        RECT  0 25.104 0.084 25.128 ;
    END
  END i[37]
  PIN i[38]
    DIRECTION INPUT ;
    USE SIGNAL ;
    PORT
      LAYER M4 ;
        RECT  0 25.2 0.084 25.224 ;
    END
  END i[38]
  PIN i[39]
    DIRECTION INPUT ;
    USE SIGNAL ;
    PORT
      LAYER M4 ;
        RECT  0 25.296 0.084 25.32 ;
    END
  END i[39]
  PIN i[3]
    DIRECTION INPUT ;
    USE SIGNAL ;
    PORT
      LAYER M4 ;
        RECT  0 31.056 0.084 31.08 ;
    END
  END i[3]
  PIN i[40]
    DIRECTION INPUT ;
    USE SIGNAL ;
    PORT
      LAYER M4 ;
        RECT  0 25.392 0.084 25.416 ;
    END
  END i[40]
  PIN i[41]
    DIRECTION INPUT ;
    USE SIGNAL ;
    PORT
      LAYER M4 ;
        RECT  0 25.488 0.084 25.512 ;
    END
  END i[41]
  PIN i[42]
    DIRECTION INPUT ;
    USE SIGNAL ;
    PORT
      LAYER M4 ;
        RECT  0 25.584 0.084 25.608 ;
    END
  END i[42]
  PIN i[43]
    DIRECTION INPUT ;
    USE SIGNAL ;
    PORT
      LAYER M4 ;
        RECT  0 25.68 0.084 25.704 ;
    END
  END i[43]
  PIN i[44]
    DIRECTION INPUT ;
    USE SIGNAL ;
    PORT
      LAYER M4 ;
        RECT  0 25.776 0.084 25.8 ;
    END
  END i[44]
  PIN i[45]
    DIRECTION INPUT ;
    USE SIGNAL ;
    PORT
      LAYER M4 ;
        RECT  0 25.872 0.084 25.896 ;
    END
  END i[45]
  PIN i[46]
    DIRECTION INPUT ;
    USE SIGNAL ;
    PORT
      LAYER M4 ;
        RECT  0 25.968 0.084 25.992 ;
    END
  END i[46]
  PIN i[47]
    DIRECTION INPUT ;
    USE SIGNAL ;
    PORT
      LAYER M4 ;
        RECT  0 26.064 0.084 26.088 ;
    END
  END i[47]
  PIN i[48]
    DIRECTION INPUT ;
    USE SIGNAL ;
    PORT
      LAYER M4 ;
        RECT  0 26.16 0.084 26.184 ;
    END
  END i[48]
  PIN i[49]
    DIRECTION INPUT ;
    USE SIGNAL ;
    PORT
      LAYER M4 ;
        RECT  0 26.256 0.084 26.28 ;
    END
  END i[49]
  PIN i[4]
    DIRECTION INPUT ;
    USE SIGNAL ;
    PORT
      LAYER M4 ;
        RECT  0 31.152 0.084 31.176 ;
    END
  END i[4]
  PIN i[50]
    DIRECTION INPUT ;
    USE SIGNAL ;
    PORT
      LAYER M4 ;
        RECT  0 26.352 0.084 26.376 ;
    END
  END i[50]
  PIN i[51]
    DIRECTION INPUT ;
    USE SIGNAL ;
    PORT
      LAYER M4 ;
        RECT  0 26.448 0.084 26.472 ;
    END
  END i[51]
  PIN i[52]
    DIRECTION INPUT ;
    USE SIGNAL ;
    PORT
      LAYER M4 ;
        RECT  0 26.544 0.084 26.568 ;
    END
  END i[52]
  PIN i[53]
    DIRECTION INPUT ;
    USE SIGNAL ;
    PORT
      LAYER M4 ;
        RECT  0 26.64 0.084 26.664 ;
    END
  END i[53]
  PIN i[54]
    DIRECTION INPUT ;
    USE SIGNAL ;
    PORT
      LAYER M4 ;
        RECT  0 26.736 0.084 26.76 ;
    END
  END i[54]
  PIN i[55]
    DIRECTION INPUT ;
    USE SIGNAL ;
    PORT
      LAYER M4 ;
        RECT  0 26.832 0.084 26.856 ;
    END
  END i[55]
  PIN i[56]
    DIRECTION INPUT ;
    USE SIGNAL ;
    PORT
      LAYER M4 ;
        RECT  0 26.928 0.084 26.952 ;
    END
  END i[56]
  PIN i[57]
    DIRECTION INPUT ;
    USE SIGNAL ;
    PORT
      LAYER M4 ;
        RECT  0 27.024 0.084 27.048 ;
    END
  END i[57]
  PIN i[58]
    DIRECTION INPUT ;
    USE SIGNAL ;
    PORT
      LAYER M4 ;
        RECT  0 27.12 0.084 27.144 ;
    END
  END i[58]
  PIN i[59]
    DIRECTION INPUT ;
    USE SIGNAL ;
    PORT
      LAYER M4 ;
        RECT  0 27.216 0.084 27.24 ;
    END
  END i[59]
  PIN i[5]
    DIRECTION INPUT ;
    USE SIGNAL ;
    PORT
      LAYER M4 ;
        RECT  0 31.248 0.084 31.272 ;
    END
  END i[5]
  PIN i[60]
    DIRECTION INPUT ;
    USE SIGNAL ;
    PORT
      LAYER M4 ;
        RECT  0 27.312 0.084 27.336 ;
    END
  END i[60]
  PIN i[61]
    DIRECTION INPUT ;
    USE SIGNAL ;
    PORT
      LAYER M4 ;
        RECT  0 27.408 0.084 27.432 ;
    END
  END i[61]
  PIN i[62]
    DIRECTION INPUT ;
    USE SIGNAL ;
    PORT
      LAYER M4 ;
        RECT  0 27.504 0.084 27.528 ;
    END
  END i[62]
  PIN i[63]
    DIRECTION INPUT ;
    USE SIGNAL ;
    PORT
      LAYER M4 ;
        RECT  0 27.6 0.084 27.624 ;
    END
  END i[63]
  PIN i[64]
    DIRECTION INPUT ;
    USE SIGNAL ;
    PORT
      LAYER M4 ;
        RECT  0 2.352 0.084 2.376 ;
    END
  END i[64]
  PIN i[65]
    DIRECTION INPUT ;
    USE SIGNAL ;
    PORT
      LAYER M4 ;
        RECT  0 2.448 0.084 2.472 ;
    END
  END i[65]
  PIN i[66]
    DIRECTION INPUT ;
    USE SIGNAL ;
    PORT
      LAYER M4 ;
        RECT  0 2.544 0.084 2.568 ;
    END
  END i[66]
  PIN i[67]
    DIRECTION INPUT ;
    USE SIGNAL ;
    PORT
      LAYER M4 ;
        RECT  0 2.64 0.084 2.664 ;
    END
  END i[67]
  PIN i[68]
    DIRECTION INPUT ;
    USE SIGNAL ;
    PORT
      LAYER M4 ;
        RECT  0 2.736 0.084 2.76 ;
    END
  END i[68]
  PIN i[69]
    DIRECTION INPUT ;
    USE SIGNAL ;
    PORT
      LAYER M4 ;
        RECT  0 2.832 0.084 2.856 ;
    END
  END i[69]
  PIN i[6]
    DIRECTION INPUT ;
    USE SIGNAL ;
    PORT
      LAYER M4 ;
        RECT  0 31.344 0.084 31.368 ;
    END
  END i[6]
  PIN i[70]
    DIRECTION INPUT ;
    USE SIGNAL ;
    PORT
      LAYER M4 ;
        RECT  0 2.928 0.084 2.952 ;
    END
  END i[70]
  PIN i[71]
    DIRECTION INPUT ;
    USE SIGNAL ;
    PORT
      LAYER M4 ;
        RECT  0 3.024 0.084 3.048 ;
    END
  END i[71]
  PIN i[72]
    DIRECTION INPUT ;
    USE SIGNAL ;
    PORT
      LAYER M4 ;
        RECT  0 3.12 0.084 3.144 ;
    END
  END i[72]
  PIN i[73]
    DIRECTION INPUT ;
    USE SIGNAL ;
    PORT
      LAYER M4 ;
        RECT  0 3.216 0.084 3.24 ;
    END
  END i[73]
  PIN i[74]
    DIRECTION INPUT ;
    USE SIGNAL ;
    PORT
      LAYER M4 ;
        RECT  0 3.312 0.084 3.336 ;
    END
  END i[74]
  PIN i[75]
    DIRECTION INPUT ;
    USE SIGNAL ;
    PORT
      LAYER M4 ;
        RECT  0 3.408 0.084 3.432 ;
    END
  END i[75]
  PIN i[76]
    DIRECTION INPUT ;
    USE SIGNAL ;
    PORT
      LAYER M4 ;
        RECT  0 3.504 0.084 3.528 ;
    END
  END i[76]
  PIN i[77]
    DIRECTION INPUT ;
    USE SIGNAL ;
    PORT
      LAYER M4 ;
        RECT  0 3.6 0.084 3.624 ;
    END
  END i[77]
  PIN i[78]
    DIRECTION INPUT ;
    USE SIGNAL ;
    PORT
      LAYER M4 ;
        RECT  0 3.696 0.084 3.72 ;
    END
  END i[78]
  PIN i[79]
    DIRECTION INPUT ;
    USE SIGNAL ;
    PORT
      LAYER M4 ;
        RECT  0 3.792 0.084 3.816 ;
    END
  END i[79]
  PIN i[7]
    DIRECTION INPUT ;
    USE SIGNAL ;
    PORT
      LAYER M4 ;
        RECT  0 31.44 0.084 31.464 ;
    END
  END i[7]
  PIN i[80]
    DIRECTION INPUT ;
    USE SIGNAL ;
    PORT
      LAYER M4 ;
        RECT  0 3.888 0.084 3.912 ;
    END
  END i[80]
  PIN i[81]
    DIRECTION INPUT ;
    USE SIGNAL ;
    PORT
      LAYER M4 ;
        RECT  0 3.984 0.084 4.008 ;
    END
  END i[81]
  PIN i[82]
    DIRECTION INPUT ;
    USE SIGNAL ;
    PORT
      LAYER M4 ;
        RECT  0 4.08 0.084 4.104 ;
    END
  END i[82]
  PIN i[83]
    DIRECTION INPUT ;
    USE SIGNAL ;
    PORT
      LAYER M4 ;
        RECT  0 4.176 0.084 4.2 ;
    END
  END i[83]
  PIN i[84]
    DIRECTION INPUT ;
    USE SIGNAL ;
    PORT
      LAYER M4 ;
        RECT  0 4.272 0.084 4.296 ;
    END
  END i[84]
  PIN i[85]
    DIRECTION INPUT ;
    USE SIGNAL ;
    PORT
      LAYER M4 ;
        RECT  0 4.368 0.084 4.392 ;
    END
  END i[85]
  PIN i[86]
    DIRECTION INPUT ;
    USE SIGNAL ;
    PORT
      LAYER M4 ;
        RECT  0 4.464 0.084 4.488 ;
    END
  END i[86]
  PIN i[87]
    DIRECTION INPUT ;
    USE SIGNAL ;
    PORT
      LAYER M4 ;
        RECT  0 4.56 0.084 4.584 ;
    END
  END i[87]
  PIN i[88]
    DIRECTION INPUT ;
    USE SIGNAL ;
    PORT
      LAYER M4 ;
        RECT  0 4.656 0.084 4.68 ;
    END
  END i[88]
  PIN i[89]
    DIRECTION INPUT ;
    USE SIGNAL ;
    PORT
      LAYER M4 ;
        RECT  0 4.752 0.084 4.776 ;
    END
  END i[89]
  PIN i[8]
    DIRECTION INPUT ;
    USE SIGNAL ;
    PORT
      LAYER M4 ;
        RECT  0 31.536 0.084 31.56 ;
    END
  END i[8]
  PIN i[90]
    DIRECTION INPUT ;
    USE SIGNAL ;
    PORT
      LAYER M4 ;
        RECT  0 4.848 0.084 4.872 ;
    END
  END i[90]
  PIN i[91]
    DIRECTION INPUT ;
    USE SIGNAL ;
    PORT
      LAYER M4 ;
        RECT  0 4.944 0.084 4.968 ;
    END
  END i[91]
  PIN i[92]
    DIRECTION INPUT ;
    USE SIGNAL ;
    PORT
      LAYER M4 ;
        RECT  0 5.04 0.084 5.064 ;
    END
  END i[92]
  PIN i[93]
    DIRECTION INPUT ;
    USE SIGNAL ;
    PORT
      LAYER M4 ;
        RECT  0 5.136 0.084 5.16 ;
    END
  END i[93]
  PIN i[94]
    DIRECTION INPUT ;
    USE SIGNAL ;
    PORT
      LAYER M4 ;
        RECT  0 5.232 0.084 5.256 ;
    END
  END i[94]
  PIN i[95]
    DIRECTION INPUT ;
    USE SIGNAL ;
    PORT
      LAYER M4 ;
        RECT  0 5.328 0.084 5.352 ;
    END
  END i[95]
  PIN i[96]
    DIRECTION INPUT ;
    USE SIGNAL ;
    PORT
      LAYER M4 ;
        RECT  0 5.424 0.084 5.448 ;
    END
  END i[96]
  PIN i[97]
    DIRECTION INPUT ;
    USE SIGNAL ;
    PORT
      LAYER M4 ;
        RECT  0 5.52 0.084 5.544 ;
    END
  END i[97]
  PIN i[98]
    DIRECTION INPUT ;
    USE SIGNAL ;
    PORT
      LAYER M4 ;
        RECT  0 5.616 0.084 5.64 ;
    END
  END i[98]
  PIN i[99]
    DIRECTION INPUT ;
    USE SIGNAL ;
    PORT
      LAYER M4 ;
        RECT  0 5.712 0.084 5.736 ;
    END
  END i[99]
  PIN i[9]
    DIRECTION INPUT ;
    USE SIGNAL ;
    PORT
      LAYER M4 ;
        RECT  0 31.632 0.084 31.656 ;
    END
  END i[9]
  PIN o[0]
    DIRECTION OUTPUT ;
    USE SIGNAL ;
    PORT
      LAYER M4 ;
        RECT  21.516 9.936 21.6 9.96 ;
    END
  END o[0]
  PIN o[100]
    DIRECTION OUTPUT ;
    USE SIGNAL ;
    PORT
      LAYER M4 ;
        RECT  21.516 7.248 21.6 7.272 ;
    END
  END o[100]
  PIN o[101]
    DIRECTION OUTPUT ;
    USE SIGNAL ;
    PORT
      LAYER M4 ;
        RECT  21.516 7.344 21.6 7.368 ;
    END
  END o[101]
  PIN o[102]
    DIRECTION OUTPUT ;
    USE SIGNAL ;
    PORT
      LAYER M4 ;
        RECT  21.516 7.44 21.6 7.464 ;
    END
  END o[102]
  PIN o[103]
    DIRECTION OUTPUT ;
    USE SIGNAL ;
    PORT
      LAYER M4 ;
        RECT  21.516 7.536 21.6 7.56 ;
    END
  END o[103]
  PIN o[104]
    DIRECTION OUTPUT ;
    USE SIGNAL ;
    PORT
      LAYER M4 ;
        RECT  21.516 7.632 21.6 7.656 ;
    END
  END o[104]
  PIN o[105]
    DIRECTION OUTPUT ;
    USE SIGNAL ;
    PORT
      LAYER M4 ;
        RECT  21.516 7.728 21.6 7.752 ;
    END
  END o[105]
  PIN o[106]
    DIRECTION OUTPUT ;
    USE SIGNAL ;
    PORT
      LAYER M4 ;
        RECT  21.516 7.824 21.6 7.848 ;
    END
  END o[106]
  PIN o[107]
    DIRECTION OUTPUT ;
    USE SIGNAL ;
    PORT
      LAYER M4 ;
        RECT  21.516 7.92 21.6 7.944 ;
    END
  END o[107]
  PIN o[108]
    DIRECTION OUTPUT ;
    USE SIGNAL ;
    PORT
      LAYER M4 ;
        RECT  21.516 8.016 21.6 8.04 ;
    END
  END o[108]
  PIN o[109]
    DIRECTION OUTPUT ;
    USE SIGNAL ;
    PORT
      LAYER M4 ;
        RECT  21.516 8.112 21.6 8.136 ;
    END
  END o[109]
  PIN o[10]
    DIRECTION OUTPUT ;
    USE SIGNAL ;
    PORT
      LAYER M4 ;
        RECT  21.516 10.896 21.6 10.92 ;
    END
  END o[10]
  PIN o[110]
    DIRECTION OUTPUT ;
    USE SIGNAL ;
    PORT
      LAYER M4 ;
        RECT  21.516 8.208 21.6 8.232 ;
    END
  END o[110]
  PIN o[111]
    DIRECTION OUTPUT ;
    USE SIGNAL ;
    PORT
      LAYER M4 ;
        RECT  21.516 8.304 21.6 8.328 ;
    END
  END o[111]
  PIN o[112]
    DIRECTION OUTPUT ;
    USE SIGNAL ;
    PORT
      LAYER M4 ;
        RECT  21.516 8.4 21.6 8.424 ;
    END
  END o[112]
  PIN o[113]
    DIRECTION OUTPUT ;
    USE SIGNAL ;
    PORT
      LAYER M4 ;
        RECT  21.516 8.496 21.6 8.52 ;
    END
  END o[113]
  PIN o[114]
    DIRECTION OUTPUT ;
    USE SIGNAL ;
    PORT
      LAYER M4 ;
        RECT  21.516 8.592 21.6 8.616 ;
    END
  END o[114]
  PIN o[115]
    DIRECTION OUTPUT ;
    USE SIGNAL ;
    PORT
      LAYER M4 ;
        RECT  21.516 8.688 21.6 8.712 ;
    END
  END o[115]
  PIN o[116]
    DIRECTION OUTPUT ;
    USE SIGNAL ;
    PORT
      LAYER M4 ;
        RECT  21.516 8.784 21.6 8.808 ;
    END
  END o[116]
  PIN o[117]
    DIRECTION OUTPUT ;
    USE SIGNAL ;
    PORT
      LAYER M4 ;
        RECT  21.516 8.88 21.6 8.904 ;
    END
  END o[117]
  PIN o[118]
    DIRECTION OUTPUT ;
    USE SIGNAL ;
    PORT
      LAYER M4 ;
        RECT  21.516 8.976 21.6 9 ;
    END
  END o[118]
  PIN o[119]
    DIRECTION OUTPUT ;
    USE SIGNAL ;
    PORT
      LAYER M4 ;
        RECT  21.516 9.072 21.6 9.096 ;
    END
  END o[119]
  PIN o[11]
    DIRECTION OUTPUT ;
    USE SIGNAL ;
    PORT
      LAYER M4 ;
        RECT  21.516 10.992 21.6 11.016 ;
    END
  END o[11]
  PIN o[120]
    DIRECTION OUTPUT ;
    USE SIGNAL ;
    PORT
      LAYER M4 ;
        RECT  21.516 9.168 21.6 9.192 ;
    END
  END o[120]
  PIN o[121]
    DIRECTION OUTPUT ;
    USE SIGNAL ;
    PORT
      LAYER M4 ;
        RECT  21.516 9.264 21.6 9.288 ;
    END
  END o[121]
  PIN o[122]
    DIRECTION OUTPUT ;
    USE SIGNAL ;
    PORT
      LAYER M4 ;
        RECT  21.516 9.36 21.6 9.384 ;
    END
  END o[122]
  PIN o[123]
    DIRECTION OUTPUT ;
    USE SIGNAL ;
    PORT
      LAYER M4 ;
        RECT  21.516 9.456 21.6 9.48 ;
    END
  END o[123]
  PIN o[124]
    DIRECTION OUTPUT ;
    USE SIGNAL ;
    PORT
      LAYER M4 ;
        RECT  21.516 9.552 21.6 9.576 ;
    END
  END o[124]
  PIN o[125]
    DIRECTION OUTPUT ;
    USE SIGNAL ;
    PORT
      LAYER M4 ;
        RECT  21.516 9.648 21.6 9.672 ;
    END
  END o[125]
  PIN o[126]
    DIRECTION OUTPUT ;
    USE SIGNAL ;
    PORT
      LAYER M4 ;
        RECT  21.516 9.744 21.6 9.768 ;
    END
  END o[126]
  PIN o[127]
    DIRECTION OUTPUT ;
    USE SIGNAL ;
    PORT
      LAYER M4 ;
        RECT  21.516 9.84 21.6 9.864 ;
    END
  END o[127]
  PIN o[128]
    DIRECTION OUTPUT ;
    USE SIGNAL ;
    PORT
      LAYER M4 ;
        RECT  21.516 19.92 21.6 19.944 ;
    END
  END o[128]
  PIN o[129]
    DIRECTION OUTPUT ;
    USE SIGNAL ;
    PORT
      LAYER M4 ;
        RECT  21.516 20.016 21.6 20.04 ;
    END
  END o[129]
  PIN o[12]
    DIRECTION OUTPUT ;
    USE SIGNAL ;
    PORT
      LAYER M4 ;
        RECT  21.516 11.088 21.6 11.112 ;
    END
  END o[12]
  PIN o[130]
    DIRECTION OUTPUT ;
    USE SIGNAL ;
    PORT
      LAYER M4 ;
        RECT  21.516 20.112 21.6 20.136 ;
    END
  END o[130]
  PIN o[131]
    DIRECTION OUTPUT ;
    USE SIGNAL ;
    PORT
      LAYER M4 ;
        RECT  21.516 20.208 21.6 20.232 ;
    END
  END o[131]
  PIN o[132]
    DIRECTION OUTPUT ;
    USE SIGNAL ;
    PORT
      LAYER M4 ;
        RECT  21.516 20.304 21.6 20.328 ;
    END
  END o[132]
  PIN o[133]
    DIRECTION OUTPUT ;
    USE SIGNAL ;
    PORT
      LAYER M4 ;
        RECT  21.516 20.4 21.6 20.424 ;
    END
  END o[133]
  PIN o[134]
    DIRECTION OUTPUT ;
    USE SIGNAL ;
    PORT
      LAYER M4 ;
        RECT  21.516 20.496 21.6 20.52 ;
    END
  END o[134]
  PIN o[135]
    DIRECTION OUTPUT ;
    USE SIGNAL ;
    PORT
      LAYER M4 ;
        RECT  21.516 20.592 21.6 20.616 ;
    END
  END o[135]
  PIN o[136]
    DIRECTION OUTPUT ;
    USE SIGNAL ;
    PORT
      LAYER M4 ;
        RECT  21.516 20.688 21.6 20.712 ;
    END
  END o[136]
  PIN o[137]
    DIRECTION OUTPUT ;
    USE SIGNAL ;
    PORT
      LAYER M4 ;
        RECT  21.516 20.784 21.6 20.808 ;
    END
  END o[137]
  PIN o[138]
    DIRECTION OUTPUT ;
    USE SIGNAL ;
    PORT
      LAYER M4 ;
        RECT  21.516 20.88 21.6 20.904 ;
    END
  END o[138]
  PIN o[139]
    DIRECTION OUTPUT ;
    USE SIGNAL ;
    PORT
      LAYER M4 ;
        RECT  21.516 20.976 21.6 21 ;
    END
  END o[139]
  PIN o[13]
    DIRECTION OUTPUT ;
    USE SIGNAL ;
    PORT
      LAYER M4 ;
        RECT  21.516 11.184 21.6 11.208 ;
    END
  END o[13]
  PIN o[140]
    DIRECTION OUTPUT ;
    USE SIGNAL ;
    PORT
      LAYER M4 ;
        RECT  21.516 21.072 21.6 21.096 ;
    END
  END o[140]
  PIN o[141]
    DIRECTION OUTPUT ;
    USE SIGNAL ;
    PORT
      LAYER M4 ;
        RECT  21.516 21.168 21.6 21.192 ;
    END
  END o[141]
  PIN o[142]
    DIRECTION OUTPUT ;
    USE SIGNAL ;
    PORT
      LAYER M4 ;
        RECT  21.516 21.264 21.6 21.288 ;
    END
  END o[142]
  PIN o[143]
    DIRECTION OUTPUT ;
    USE SIGNAL ;
    PORT
      LAYER M4 ;
        RECT  21.516 21.36 21.6 21.384 ;
    END
  END o[143]
  PIN o[144]
    DIRECTION OUTPUT ;
    USE SIGNAL ;
    PORT
      LAYER M4 ;
        RECT  21.516 21.456 21.6 21.48 ;
    END
  END o[144]
  PIN o[145]
    DIRECTION OUTPUT ;
    USE SIGNAL ;
    PORT
      LAYER M4 ;
        RECT  21.516 21.552 21.6 21.576 ;
    END
  END o[145]
  PIN o[146]
    DIRECTION OUTPUT ;
    USE SIGNAL ;
    PORT
      LAYER M4 ;
        RECT  21.516 21.648 21.6 21.672 ;
    END
  END o[146]
  PIN o[147]
    DIRECTION OUTPUT ;
    USE SIGNAL ;
    PORT
      LAYER M4 ;
        RECT  21.516 21.744 21.6 21.768 ;
    END
  END o[147]
  PIN o[148]
    DIRECTION OUTPUT ;
    USE SIGNAL ;
    PORT
      LAYER M4 ;
        RECT  21.516 21.84 21.6 21.864 ;
    END
  END o[148]
  PIN o[149]
    DIRECTION OUTPUT ;
    USE SIGNAL ;
    PORT
      LAYER M4 ;
        RECT  21.516 21.936 21.6 21.96 ;
    END
  END o[149]
  PIN o[14]
    DIRECTION OUTPUT ;
    USE SIGNAL ;
    PORT
      LAYER M4 ;
        RECT  21.516 11.28 21.6 11.304 ;
    END
  END o[14]
  PIN o[150]
    DIRECTION OUTPUT ;
    USE SIGNAL ;
    PORT
      LAYER M4 ;
        RECT  21.516 22.032 21.6 22.056 ;
    END
  END o[150]
  PIN o[151]
    DIRECTION OUTPUT ;
    USE SIGNAL ;
    PORT
      LAYER M4 ;
        RECT  21.516 22.128 21.6 22.152 ;
    END
  END o[151]
  PIN o[152]
    DIRECTION OUTPUT ;
    USE SIGNAL ;
    PORT
      LAYER M4 ;
        RECT  21.516 22.224 21.6 22.248 ;
    END
  END o[152]
  PIN o[153]
    DIRECTION OUTPUT ;
    USE SIGNAL ;
    PORT
      LAYER M4 ;
        RECT  21.516 22.32 21.6 22.344 ;
    END
  END o[153]
  PIN o[154]
    DIRECTION OUTPUT ;
    USE SIGNAL ;
    PORT
      LAYER M4 ;
        RECT  21.516 22.416 21.6 22.44 ;
    END
  END o[154]
  PIN o[155]
    DIRECTION OUTPUT ;
    USE SIGNAL ;
    PORT
      LAYER M4 ;
        RECT  21.516 22.512 21.6 22.536 ;
    END
  END o[155]
  PIN o[156]
    DIRECTION OUTPUT ;
    USE SIGNAL ;
    PORT
      LAYER M4 ;
        RECT  21.516 22.608 21.6 22.632 ;
    END
  END o[156]
  PIN o[157]
    DIRECTION OUTPUT ;
    USE SIGNAL ;
    PORT
      LAYER M4 ;
        RECT  21.516 22.704 21.6 22.728 ;
    END
  END o[157]
  PIN o[158]
    DIRECTION OUTPUT ;
    USE SIGNAL ;
    PORT
      LAYER M4 ;
        RECT  21.516 22.8 21.6 22.824 ;
    END
  END o[158]
  PIN o[159]
    DIRECTION OUTPUT ;
    USE SIGNAL ;
    PORT
      LAYER M4 ;
        RECT  21.516 22.896 21.6 22.92 ;
    END
  END o[159]
  PIN o[15]
    DIRECTION OUTPUT ;
    USE SIGNAL ;
    PORT
      LAYER M4 ;
        RECT  21.516 11.376 21.6 11.4 ;
    END
  END o[15]
  PIN o[160]
    DIRECTION OUTPUT ;
    USE SIGNAL ;
    PORT
      LAYER M4 ;
        RECT  21.516 3.792 21.6 3.816 ;
    END
  END o[160]
  PIN o[161]
    DIRECTION OUTPUT ;
    USE SIGNAL ;
    PORT
      LAYER M4 ;
        RECT  21.516 3.888 21.6 3.912 ;
    END
  END o[161]
  PIN o[162]
    DIRECTION OUTPUT ;
    USE SIGNAL ;
    PORT
      LAYER M4 ;
        RECT  21.516 3.984 21.6 4.008 ;
    END
  END o[162]
  PIN o[163]
    DIRECTION OUTPUT ;
    USE SIGNAL ;
    PORT
      LAYER M4 ;
        RECT  21.516 4.08 21.6 4.104 ;
    END
  END o[163]
  PIN o[164]
    DIRECTION OUTPUT ;
    USE SIGNAL ;
    PORT
      LAYER M4 ;
        RECT  21.516 4.176 21.6 4.2 ;
    END
  END o[164]
  PIN o[165]
    DIRECTION OUTPUT ;
    USE SIGNAL ;
    PORT
      LAYER M4 ;
        RECT  21.516 4.272 21.6 4.296 ;
    END
  END o[165]
  PIN o[166]
    DIRECTION OUTPUT ;
    USE SIGNAL ;
    PORT
      LAYER M4 ;
        RECT  21.516 4.368 21.6 4.392 ;
    END
  END o[166]
  PIN o[167]
    DIRECTION OUTPUT ;
    USE SIGNAL ;
    PORT
      LAYER M4 ;
        RECT  21.516 4.464 21.6 4.488 ;
    END
  END o[167]
  PIN o[168]
    DIRECTION OUTPUT ;
    USE SIGNAL ;
    PORT
      LAYER M4 ;
        RECT  21.516 4.56 21.6 4.584 ;
    END
  END o[168]
  PIN o[169]
    DIRECTION OUTPUT ;
    USE SIGNAL ;
    PORT
      LAYER M4 ;
        RECT  21.516 4.656 21.6 4.68 ;
    END
  END o[169]
  PIN o[16]
    DIRECTION OUTPUT ;
    USE SIGNAL ;
    PORT
      LAYER M4 ;
        RECT  21.516 11.472 21.6 11.496 ;
    END
  END o[16]
  PIN o[170]
    DIRECTION OUTPUT ;
    USE SIGNAL ;
    PORT
      LAYER M4 ;
        RECT  21.516 4.752 21.6 4.776 ;
    END
  END o[170]
  PIN o[171]
    DIRECTION OUTPUT ;
    USE SIGNAL ;
    PORT
      LAYER M4 ;
        RECT  21.516 4.848 21.6 4.872 ;
    END
  END o[171]
  PIN o[172]
    DIRECTION OUTPUT ;
    USE SIGNAL ;
    PORT
      LAYER M4 ;
        RECT  21.516 4.944 21.6 4.968 ;
    END
  END o[172]
  PIN o[173]
    DIRECTION OUTPUT ;
    USE SIGNAL ;
    PORT
      LAYER M4 ;
        RECT  21.516 5.04 21.6 5.064 ;
    END
  END o[173]
  PIN o[174]
    DIRECTION OUTPUT ;
    USE SIGNAL ;
    PORT
      LAYER M4 ;
        RECT  21.516 5.136 21.6 5.16 ;
    END
  END o[174]
  PIN o[175]
    DIRECTION OUTPUT ;
    USE SIGNAL ;
    PORT
      LAYER M4 ;
        RECT  21.516 5.232 21.6 5.256 ;
    END
  END o[175]
  PIN o[176]
    DIRECTION OUTPUT ;
    USE SIGNAL ;
    PORT
      LAYER M4 ;
        RECT  21.516 5.328 21.6 5.352 ;
    END
  END o[176]
  PIN o[177]
    DIRECTION OUTPUT ;
    USE SIGNAL ;
    PORT
      LAYER M4 ;
        RECT  21.516 5.424 21.6 5.448 ;
    END
  END o[177]
  PIN o[178]
    DIRECTION OUTPUT ;
    USE SIGNAL ;
    PORT
      LAYER M4 ;
        RECT  21.516 5.52 21.6 5.544 ;
    END
  END o[178]
  PIN o[179]
    DIRECTION OUTPUT ;
    USE SIGNAL ;
    PORT
      LAYER M4 ;
        RECT  21.516 5.616 21.6 5.64 ;
    END
  END o[179]
  PIN o[17]
    DIRECTION OUTPUT ;
    USE SIGNAL ;
    PORT
      LAYER M4 ;
        RECT  21.516 11.568 21.6 11.592 ;
    END
  END o[17]
  PIN o[180]
    DIRECTION OUTPUT ;
    USE SIGNAL ;
    PORT
      LAYER M4 ;
        RECT  21.516 5.712 21.6 5.736 ;
    END
  END o[180]
  PIN o[181]
    DIRECTION OUTPUT ;
    USE SIGNAL ;
    PORT
      LAYER M4 ;
        RECT  21.516 5.808 21.6 5.832 ;
    END
  END o[181]
  PIN o[182]
    DIRECTION OUTPUT ;
    USE SIGNAL ;
    PORT
      LAYER M4 ;
        RECT  21.516 5.904 21.6 5.928 ;
    END
  END o[182]
  PIN o[183]
    DIRECTION OUTPUT ;
    USE SIGNAL ;
    PORT
      LAYER M4 ;
        RECT  21.516 6 21.6 6.024 ;
    END
  END o[183]
  PIN o[184]
    DIRECTION OUTPUT ;
    USE SIGNAL ;
    PORT
      LAYER M4 ;
        RECT  21.516 6.096 21.6 6.12 ;
    END
  END o[184]
  PIN o[185]
    DIRECTION OUTPUT ;
    USE SIGNAL ;
    PORT
      LAYER M4 ;
        RECT  21.516 6.192 21.6 6.216 ;
    END
  END o[185]
  PIN o[186]
    DIRECTION OUTPUT ;
    USE SIGNAL ;
    PORT
      LAYER M4 ;
        RECT  21.516 6.288 21.6 6.312 ;
    END
  END o[186]
  PIN o[187]
    DIRECTION OUTPUT ;
    USE SIGNAL ;
    PORT
      LAYER M4 ;
        RECT  21.516 6.384 21.6 6.408 ;
    END
  END o[187]
  PIN o[188]
    DIRECTION OUTPUT ;
    USE SIGNAL ;
    PORT
      LAYER M4 ;
        RECT  21.516 6.48 21.6 6.504 ;
    END
  END o[188]
  PIN o[189]
    DIRECTION OUTPUT ;
    USE SIGNAL ;
    PORT
      LAYER M4 ;
        RECT  21.516 6.576 21.6 6.6 ;
    END
  END o[189]
  PIN o[18]
    DIRECTION OUTPUT ;
    USE SIGNAL ;
    PORT
      LAYER M4 ;
        RECT  21.516 11.664 21.6 11.688 ;
    END
  END o[18]
  PIN o[190]
    DIRECTION OUTPUT ;
    USE SIGNAL ;
    PORT
      LAYER M4 ;
        RECT  21.516 6.672 21.6 6.696 ;
    END
  END o[190]
  PIN o[191]
    DIRECTION OUTPUT ;
    USE SIGNAL ;
    PORT
      LAYER M4 ;
        RECT  21.516 6.768 21.6 6.792 ;
    END
  END o[191]
  PIN o[192]
    DIRECTION OUTPUT ;
    USE SIGNAL ;
    PORT
      LAYER M4 ;
        RECT  21.516 13.008 21.6 13.032 ;
    END
  END o[192]
  PIN o[193]
    DIRECTION OUTPUT ;
    USE SIGNAL ;
    PORT
      LAYER M4 ;
        RECT  21.516 13.104 21.6 13.128 ;
    END
  END o[193]
  PIN o[194]
    DIRECTION OUTPUT ;
    USE SIGNAL ;
    PORT
      LAYER M4 ;
        RECT  21.516 13.2 21.6 13.224 ;
    END
  END o[194]
  PIN o[195]
    DIRECTION OUTPUT ;
    USE SIGNAL ;
    PORT
      LAYER M4 ;
        RECT  21.516 13.296 21.6 13.32 ;
    END
  END o[195]
  PIN o[196]
    DIRECTION OUTPUT ;
    USE SIGNAL ;
    PORT
      LAYER M4 ;
        RECT  21.516 13.392 21.6 13.416 ;
    END
  END o[196]
  PIN o[197]
    DIRECTION OUTPUT ;
    USE SIGNAL ;
    PORT
      LAYER M4 ;
        RECT  21.516 13.488 21.6 13.512 ;
    END
  END o[197]
  PIN o[198]
    DIRECTION OUTPUT ;
    USE SIGNAL ;
    PORT
      LAYER M4 ;
        RECT  21.516 13.584 21.6 13.608 ;
    END
  END o[198]
  PIN o[199]
    DIRECTION OUTPUT ;
    USE SIGNAL ;
    PORT
      LAYER M4 ;
        RECT  21.516 13.68 21.6 13.704 ;
    END
  END o[199]
  PIN o[19]
    DIRECTION OUTPUT ;
    USE SIGNAL ;
    PORT
      LAYER M4 ;
        RECT  21.516 11.76 21.6 11.784 ;
    END
  END o[19]
  PIN o[1]
    DIRECTION OUTPUT ;
    USE SIGNAL ;
    PORT
      LAYER M4 ;
        RECT  21.516 10.032 21.6 10.056 ;
    END
  END o[1]
  PIN o[200]
    DIRECTION OUTPUT ;
    USE SIGNAL ;
    PORT
      LAYER M4 ;
        RECT  21.516 13.776 21.6 13.8 ;
    END
  END o[200]
  PIN o[201]
    DIRECTION OUTPUT ;
    USE SIGNAL ;
    PORT
      LAYER M4 ;
        RECT  21.516 13.872 21.6 13.896 ;
    END
  END o[201]
  PIN o[202]
    DIRECTION OUTPUT ;
    USE SIGNAL ;
    PORT
      LAYER M4 ;
        RECT  21.516 13.968 21.6 13.992 ;
    END
  END o[202]
  PIN o[203]
    DIRECTION OUTPUT ;
    USE SIGNAL ;
    PORT
      LAYER M4 ;
        RECT  21.516 14.064 21.6 14.088 ;
    END
  END o[203]
  PIN o[204]
    DIRECTION OUTPUT ;
    USE SIGNAL ;
    PORT
      LAYER M4 ;
        RECT  21.516 14.16 21.6 14.184 ;
    END
  END o[204]
  PIN o[205]
    DIRECTION OUTPUT ;
    USE SIGNAL ;
    PORT
      LAYER M4 ;
        RECT  21.516 14.256 21.6 14.28 ;
    END
  END o[205]
  PIN o[206]
    DIRECTION OUTPUT ;
    USE SIGNAL ;
    PORT
      LAYER M4 ;
        RECT  21.516 14.352 21.6 14.376 ;
    END
  END o[206]
  PIN o[207]
    DIRECTION OUTPUT ;
    USE SIGNAL ;
    PORT
      LAYER M4 ;
        RECT  21.516 14.448 21.6 14.472 ;
    END
  END o[207]
  PIN o[208]
    DIRECTION OUTPUT ;
    USE SIGNAL ;
    PORT
      LAYER M4 ;
        RECT  21.516 14.544 21.6 14.568 ;
    END
  END o[208]
  PIN o[209]
    DIRECTION OUTPUT ;
    USE SIGNAL ;
    PORT
      LAYER M4 ;
        RECT  21.516 14.64 21.6 14.664 ;
    END
  END o[209]
  PIN o[20]
    DIRECTION OUTPUT ;
    USE SIGNAL ;
    PORT
      LAYER M4 ;
        RECT  21.516 11.856 21.6 11.88 ;
    END
  END o[20]
  PIN o[210]
    DIRECTION OUTPUT ;
    USE SIGNAL ;
    PORT
      LAYER M4 ;
        RECT  21.516 14.736 21.6 14.76 ;
    END
  END o[210]
  PIN o[211]
    DIRECTION OUTPUT ;
    USE SIGNAL ;
    PORT
      LAYER M4 ;
        RECT  21.516 14.832 21.6 14.856 ;
    END
  END o[211]
  PIN o[212]
    DIRECTION OUTPUT ;
    USE SIGNAL ;
    PORT
      LAYER M4 ;
        RECT  21.516 14.928 21.6 14.952 ;
    END
  END o[212]
  PIN o[213]
    DIRECTION OUTPUT ;
    USE SIGNAL ;
    PORT
      LAYER M4 ;
        RECT  21.516 15.024 21.6 15.048 ;
    END
  END o[213]
  PIN o[214]
    DIRECTION OUTPUT ;
    USE SIGNAL ;
    PORT
      LAYER M4 ;
        RECT  21.516 15.12 21.6 15.144 ;
    END
  END o[214]
  PIN o[215]
    DIRECTION OUTPUT ;
    USE SIGNAL ;
    PORT
      LAYER M4 ;
        RECT  21.516 15.216 21.6 15.24 ;
    END
  END o[215]
  PIN o[216]
    DIRECTION OUTPUT ;
    USE SIGNAL ;
    PORT
      LAYER M4 ;
        RECT  21.516 15.312 21.6 15.336 ;
    END
  END o[216]
  PIN o[217]
    DIRECTION OUTPUT ;
    USE SIGNAL ;
    PORT
      LAYER M4 ;
        RECT  21.516 15.408 21.6 15.432 ;
    END
  END o[217]
  PIN o[218]
    DIRECTION OUTPUT ;
    USE SIGNAL ;
    PORT
      LAYER M4 ;
        RECT  21.516 15.504 21.6 15.528 ;
    END
  END o[218]
  PIN o[219]
    DIRECTION OUTPUT ;
    USE SIGNAL ;
    PORT
      LAYER M4 ;
        RECT  21.516 15.6 21.6 15.624 ;
    END
  END o[219]
  PIN o[21]
    DIRECTION OUTPUT ;
    USE SIGNAL ;
    PORT
      LAYER M4 ;
        RECT  21.516 11.952 21.6 11.976 ;
    END
  END o[21]
  PIN o[220]
    DIRECTION OUTPUT ;
    USE SIGNAL ;
    PORT
      LAYER M4 ;
        RECT  21.516 15.696 21.6 15.72 ;
    END
  END o[220]
  PIN o[221]
    DIRECTION OUTPUT ;
    USE SIGNAL ;
    PORT
      LAYER M4 ;
        RECT  21.516 15.792 21.6 15.816 ;
    END
  END o[221]
  PIN o[222]
    DIRECTION OUTPUT ;
    USE SIGNAL ;
    PORT
      LAYER M4 ;
        RECT  21.516 15.888 21.6 15.912 ;
    END
  END o[222]
  PIN o[223]
    DIRECTION OUTPUT ;
    USE SIGNAL ;
    PORT
      LAYER M4 ;
        RECT  21.516 15.984 21.6 16.008 ;
    END
  END o[223]
  PIN o[224]
    DIRECTION OUTPUT ;
    USE SIGNAL ;
    PORT
      LAYER M4 ;
        RECT  21.516 29.136 21.6 29.16 ;
    END
  END o[224]
  PIN o[225]
    DIRECTION OUTPUT ;
    USE SIGNAL ;
    PORT
      LAYER M4 ;
        RECT  21.516 29.232 21.6 29.256 ;
    END
  END o[225]
  PIN o[226]
    DIRECTION OUTPUT ;
    USE SIGNAL ;
    PORT
      LAYER M4 ;
        RECT  21.516 29.328 21.6 29.352 ;
    END
  END o[226]
  PIN o[227]
    DIRECTION OUTPUT ;
    USE SIGNAL ;
    PORT
      LAYER M4 ;
        RECT  21.516 29.424 21.6 29.448 ;
    END
  END o[227]
  PIN o[228]
    DIRECTION OUTPUT ;
    USE SIGNAL ;
    PORT
      LAYER M4 ;
        RECT  21.516 29.52 21.6 29.544 ;
    END
  END o[228]
  PIN o[229]
    DIRECTION OUTPUT ;
    USE SIGNAL ;
    PORT
      LAYER M4 ;
        RECT  21.516 29.616 21.6 29.64 ;
    END
  END o[229]
  PIN o[22]
    DIRECTION OUTPUT ;
    USE SIGNAL ;
    PORT
      LAYER M4 ;
        RECT  21.516 12.048 21.6 12.072 ;
    END
  END o[22]
  PIN o[230]
    DIRECTION OUTPUT ;
    USE SIGNAL ;
    PORT
      LAYER M4 ;
        RECT  21.516 29.712 21.6 29.736 ;
    END
  END o[230]
  PIN o[231]
    DIRECTION OUTPUT ;
    USE SIGNAL ;
    PORT
      LAYER M4 ;
        RECT  21.516 29.808 21.6 29.832 ;
    END
  END o[231]
  PIN o[232]
    DIRECTION OUTPUT ;
    USE SIGNAL ;
    PORT
      LAYER M4 ;
        RECT  21.516 29.904 21.6 29.928 ;
    END
  END o[232]
  PIN o[233]
    DIRECTION OUTPUT ;
    USE SIGNAL ;
    PORT
      LAYER M4 ;
        RECT  21.516 30 21.6 30.024 ;
    END
  END o[233]
  PIN o[234]
    DIRECTION OUTPUT ;
    USE SIGNAL ;
    PORT
      LAYER M4 ;
        RECT  21.516 30.096 21.6 30.12 ;
    END
  END o[234]
  PIN o[235]
    DIRECTION OUTPUT ;
    USE SIGNAL ;
    PORT
      LAYER M4 ;
        RECT  21.516 30.192 21.6 30.216 ;
    END
  END o[235]
  PIN o[236]
    DIRECTION OUTPUT ;
    USE SIGNAL ;
    PORT
      LAYER M4 ;
        RECT  21.516 30.288 21.6 30.312 ;
    END
  END o[236]
  PIN o[237]
    DIRECTION OUTPUT ;
    USE SIGNAL ;
    PORT
      LAYER M4 ;
        RECT  21.516 30.384 21.6 30.408 ;
    END
  END o[237]
  PIN o[238]
    DIRECTION OUTPUT ;
    USE SIGNAL ;
    PORT
      LAYER M4 ;
        RECT  21.516 30.48 21.6 30.504 ;
    END
  END o[238]
  PIN o[239]
    DIRECTION OUTPUT ;
    USE SIGNAL ;
    PORT
      LAYER M4 ;
        RECT  21.516 30.576 21.6 30.6 ;
    END
  END o[239]
  PIN o[23]
    DIRECTION OUTPUT ;
    USE SIGNAL ;
    PORT
      LAYER M4 ;
        RECT  21.516 12.144 21.6 12.168 ;
    END
  END o[23]
  PIN o[240]
    DIRECTION OUTPUT ;
    USE SIGNAL ;
    PORT
      LAYER M4 ;
        RECT  21.516 30.672 21.6 30.696 ;
    END
  END o[240]
  PIN o[241]
    DIRECTION OUTPUT ;
    USE SIGNAL ;
    PORT
      LAYER M4 ;
        RECT  21.516 30.768 21.6 30.792 ;
    END
  END o[241]
  PIN o[242]
    DIRECTION OUTPUT ;
    USE SIGNAL ;
    PORT
      LAYER M4 ;
        RECT  21.516 30.864 21.6 30.888 ;
    END
  END o[242]
  PIN o[243]
    DIRECTION OUTPUT ;
    USE SIGNAL ;
    PORT
      LAYER M4 ;
        RECT  21.516 30.96 21.6 30.984 ;
    END
  END o[243]
  PIN o[244]
    DIRECTION OUTPUT ;
    USE SIGNAL ;
    PORT
      LAYER M4 ;
        RECT  21.516 31.056 21.6 31.08 ;
    END
  END o[244]
  PIN o[245]
    DIRECTION OUTPUT ;
    USE SIGNAL ;
    PORT
      LAYER M4 ;
        RECT  21.516 31.152 21.6 31.176 ;
    END
  END o[245]
  PIN o[246]
    DIRECTION OUTPUT ;
    USE SIGNAL ;
    PORT
      LAYER M4 ;
        RECT  21.516 31.248 21.6 31.272 ;
    END
  END o[246]
  PIN o[247]
    DIRECTION OUTPUT ;
    USE SIGNAL ;
    PORT
      LAYER M4 ;
        RECT  21.516 31.344 21.6 31.368 ;
    END
  END o[247]
  PIN o[248]
    DIRECTION OUTPUT ;
    USE SIGNAL ;
    PORT
      LAYER M4 ;
        RECT  21.516 31.44 21.6 31.464 ;
    END
  END o[248]
  PIN o[249]
    DIRECTION OUTPUT ;
    USE SIGNAL ;
    PORT
      LAYER M4 ;
        RECT  21.516 31.536 21.6 31.56 ;
    END
  END o[249]
  PIN o[24]
    DIRECTION OUTPUT ;
    USE SIGNAL ;
    PORT
      LAYER M4 ;
        RECT  21.516 12.24 21.6 12.264 ;
    END
  END o[24]
  PIN o[250]
    DIRECTION OUTPUT ;
    USE SIGNAL ;
    PORT
      LAYER M4 ;
        RECT  21.516 31.632 21.6 31.656 ;
    END
  END o[250]
  PIN o[251]
    DIRECTION OUTPUT ;
    USE SIGNAL ;
    PORT
      LAYER M4 ;
        RECT  21.516 31.728 21.6 31.752 ;
    END
  END o[251]
  PIN o[252]
    DIRECTION OUTPUT ;
    USE SIGNAL ;
    PORT
      LAYER M4 ;
        RECT  21.516 31.824 21.6 31.848 ;
    END
  END o[252]
  PIN o[253]
    DIRECTION OUTPUT ;
    USE SIGNAL ;
    PORT
      LAYER M4 ;
        RECT  21.516 31.92 21.6 31.944 ;
    END
  END o[253]
  PIN o[254]
    DIRECTION OUTPUT ;
    USE SIGNAL ;
    PORT
      LAYER M4 ;
        RECT  21.516 32.016 21.6 32.04 ;
    END
  END o[254]
  PIN o[255]
    DIRECTION OUTPUT ;
    USE SIGNAL ;
    PORT
      LAYER M4 ;
        RECT  21.516 32.112 21.6 32.136 ;
    END
  END o[255]
  PIN o[256]
    DIRECTION OUTPUT ;
    USE SIGNAL ;
    PORT
      LAYER M4 ;
        RECT  21.516 16.08 21.6 16.104 ;
    END
  END o[256]
  PIN o[257]
    DIRECTION OUTPUT ;
    USE SIGNAL ;
    PORT
      LAYER M4 ;
        RECT  21.516 16.176 21.6 16.2 ;
    END
  END o[257]
  PIN o[258]
    DIRECTION OUTPUT ;
    USE SIGNAL ;
    PORT
      LAYER M4 ;
        RECT  21.516 16.272 21.6 16.296 ;
    END
  END o[258]
  PIN o[259]
    DIRECTION OUTPUT ;
    USE SIGNAL ;
    PORT
      LAYER M4 ;
        RECT  21.516 16.368 21.6 16.392 ;
    END
  END o[259]
  PIN o[25]
    DIRECTION OUTPUT ;
    USE SIGNAL ;
    PORT
      LAYER M4 ;
        RECT  21.516 12.336 21.6 12.36 ;
    END
  END o[25]
  PIN o[260]
    DIRECTION OUTPUT ;
    USE SIGNAL ;
    PORT
      LAYER M4 ;
        RECT  21.516 16.464 21.6 16.488 ;
    END
  END o[260]
  PIN o[261]
    DIRECTION OUTPUT ;
    USE SIGNAL ;
    PORT
      LAYER M4 ;
        RECT  21.516 16.56 21.6 16.584 ;
    END
  END o[261]
  PIN o[262]
    DIRECTION OUTPUT ;
    USE SIGNAL ;
    PORT
      LAYER M4 ;
        RECT  21.516 16.656 21.6 16.68 ;
    END
  END o[262]
  PIN o[263]
    DIRECTION OUTPUT ;
    USE SIGNAL ;
    PORT
      LAYER M4 ;
        RECT  21.516 16.752 21.6 16.776 ;
    END
  END o[263]
  PIN o[264]
    DIRECTION OUTPUT ;
    USE SIGNAL ;
    PORT
      LAYER M4 ;
        RECT  21.516 16.848 21.6 16.872 ;
    END
  END o[264]
  PIN o[265]
    DIRECTION OUTPUT ;
    USE SIGNAL ;
    PORT
      LAYER M4 ;
        RECT  21.516 16.944 21.6 16.968 ;
    END
  END o[265]
  PIN o[266]
    DIRECTION OUTPUT ;
    USE SIGNAL ;
    PORT
      LAYER M4 ;
        RECT  21.516 17.04 21.6 17.064 ;
    END
  END o[266]
  PIN o[267]
    DIRECTION OUTPUT ;
    USE SIGNAL ;
    PORT
      LAYER M4 ;
        RECT  21.516 17.136 21.6 17.16 ;
    END
  END o[267]
  PIN o[268]
    DIRECTION OUTPUT ;
    USE SIGNAL ;
    PORT
      LAYER M4 ;
        RECT  21.516 17.232 21.6 17.256 ;
    END
  END o[268]
  PIN o[269]
    DIRECTION OUTPUT ;
    USE SIGNAL ;
    PORT
      LAYER M4 ;
        RECT  21.516 17.328 21.6 17.352 ;
    END
  END o[269]
  PIN o[26]
    DIRECTION OUTPUT ;
    USE SIGNAL ;
    PORT
      LAYER M4 ;
        RECT  21.516 12.432 21.6 12.456 ;
    END
  END o[26]
  PIN o[270]
    DIRECTION OUTPUT ;
    USE SIGNAL ;
    PORT
      LAYER M4 ;
        RECT  21.516 17.424 21.6 17.448 ;
    END
  END o[270]
  PIN o[271]
    DIRECTION OUTPUT ;
    USE SIGNAL ;
    PORT
      LAYER M4 ;
        RECT  21.516 17.52 21.6 17.544 ;
    END
  END o[271]
  PIN o[272]
    DIRECTION OUTPUT ;
    USE SIGNAL ;
    PORT
      LAYER M4 ;
        RECT  21.516 17.616 21.6 17.64 ;
    END
  END o[272]
  PIN o[273]
    DIRECTION OUTPUT ;
    USE SIGNAL ;
    PORT
      LAYER M4 ;
        RECT  21.516 17.712 21.6 17.736 ;
    END
  END o[273]
  PIN o[274]
    DIRECTION OUTPUT ;
    USE SIGNAL ;
    PORT
      LAYER M4 ;
        RECT  21.516 17.808 21.6 17.832 ;
    END
  END o[274]
  PIN o[275]
    DIRECTION OUTPUT ;
    USE SIGNAL ;
    PORT
      LAYER M4 ;
        RECT  21.516 17.904 21.6 17.928 ;
    END
  END o[275]
  PIN o[276]
    DIRECTION OUTPUT ;
    USE SIGNAL ;
    PORT
      LAYER M4 ;
        RECT  21.516 18 21.6 18.024 ;
    END
  END o[276]
  PIN o[277]
    DIRECTION OUTPUT ;
    USE SIGNAL ;
    PORT
      LAYER M4 ;
        RECT  21.516 18.096 21.6 18.12 ;
    END
  END o[277]
  PIN o[278]
    DIRECTION OUTPUT ;
    USE SIGNAL ;
    PORT
      LAYER M4 ;
        RECT  21.516 18.192 21.6 18.216 ;
    END
  END o[278]
  PIN o[279]
    DIRECTION OUTPUT ;
    USE SIGNAL ;
    PORT
      LAYER M4 ;
        RECT  21.516 18.288 21.6 18.312 ;
    END
  END o[279]
  PIN o[27]
    DIRECTION OUTPUT ;
    USE SIGNAL ;
    PORT
      LAYER M4 ;
        RECT  21.516 12.528 21.6 12.552 ;
    END
  END o[27]
  PIN o[280]
    DIRECTION OUTPUT ;
    USE SIGNAL ;
    PORT
      LAYER M4 ;
        RECT  21.516 18.384 21.6 18.408 ;
    END
  END o[280]
  PIN o[281]
    DIRECTION OUTPUT ;
    USE SIGNAL ;
    PORT
      LAYER M4 ;
        RECT  21.516 18.48 21.6 18.504 ;
    END
  END o[281]
  PIN o[282]
    DIRECTION OUTPUT ;
    USE SIGNAL ;
    PORT
      LAYER M4 ;
        RECT  21.516 18.576 21.6 18.6 ;
    END
  END o[282]
  PIN o[283]
    DIRECTION OUTPUT ;
    USE SIGNAL ;
    PORT
      LAYER M4 ;
        RECT  21.516 18.672 21.6 18.696 ;
    END
  END o[283]
  PIN o[284]
    DIRECTION OUTPUT ;
    USE SIGNAL ;
    PORT
      LAYER M4 ;
        RECT  21.516 18.768 21.6 18.792 ;
    END
  END o[284]
  PIN o[285]
    DIRECTION OUTPUT ;
    USE SIGNAL ;
    PORT
      LAYER M4 ;
        RECT  21.516 18.864 21.6 18.888 ;
    END
  END o[285]
  PIN o[286]
    DIRECTION OUTPUT ;
    USE SIGNAL ;
    PORT
      LAYER M4 ;
        RECT  21.516 18.96 21.6 18.984 ;
    END
  END o[286]
  PIN o[287]
    DIRECTION OUTPUT ;
    USE SIGNAL ;
    PORT
      LAYER M4 ;
        RECT  21.516 19.056 21.6 19.08 ;
    END
  END o[287]
  PIN o[288]
    DIRECTION OUTPUT ;
    USE SIGNAL ;
    PORT
      LAYER M4 ;
        RECT  21.516 22.992 21.6 23.016 ;
    END
  END o[288]
  PIN o[289]
    DIRECTION OUTPUT ;
    USE SIGNAL ;
    PORT
      LAYER M4 ;
        RECT  21.516 23.088 21.6 23.112 ;
    END
  END o[289]
  PIN o[28]
    DIRECTION OUTPUT ;
    USE SIGNAL ;
    PORT
      LAYER M4 ;
        RECT  21.516 12.624 21.6 12.648 ;
    END
  END o[28]
  PIN o[290]
    DIRECTION OUTPUT ;
    USE SIGNAL ;
    PORT
      LAYER M4 ;
        RECT  21.516 23.184 21.6 23.208 ;
    END
  END o[290]
  PIN o[291]
    DIRECTION OUTPUT ;
    USE SIGNAL ;
    PORT
      LAYER M4 ;
        RECT  21.516 23.28 21.6 23.304 ;
    END
  END o[291]
  PIN o[292]
    DIRECTION OUTPUT ;
    USE SIGNAL ;
    PORT
      LAYER M4 ;
        RECT  21.516 23.376 21.6 23.4 ;
    END
  END o[292]
  PIN o[293]
    DIRECTION OUTPUT ;
    USE SIGNAL ;
    PORT
      LAYER M4 ;
        RECT  21.516 23.472 21.6 23.496 ;
    END
  END o[293]
  PIN o[294]
    DIRECTION OUTPUT ;
    USE SIGNAL ;
    PORT
      LAYER M4 ;
        RECT  21.516 23.568 21.6 23.592 ;
    END
  END o[294]
  PIN o[295]
    DIRECTION OUTPUT ;
    USE SIGNAL ;
    PORT
      LAYER M4 ;
        RECT  21.516 23.664 21.6 23.688 ;
    END
  END o[295]
  PIN o[296]
    DIRECTION OUTPUT ;
    USE SIGNAL ;
    PORT
      LAYER M4 ;
        RECT  21.516 23.76 21.6 23.784 ;
    END
  END o[296]
  PIN o[297]
    DIRECTION OUTPUT ;
    USE SIGNAL ;
    PORT
      LAYER M4 ;
        RECT  21.516 23.856 21.6 23.88 ;
    END
  END o[297]
  PIN o[298]
    DIRECTION OUTPUT ;
    USE SIGNAL ;
    PORT
      LAYER M4 ;
        RECT  21.516 23.952 21.6 23.976 ;
    END
  END o[298]
  PIN o[299]
    DIRECTION OUTPUT ;
    USE SIGNAL ;
    PORT
      LAYER M4 ;
        RECT  21.516 24.048 21.6 24.072 ;
    END
  END o[299]
  PIN o[29]
    DIRECTION OUTPUT ;
    USE SIGNAL ;
    PORT
      LAYER M4 ;
        RECT  21.516 12.72 21.6 12.744 ;
    END
  END o[29]
  PIN o[2]
    DIRECTION OUTPUT ;
    USE SIGNAL ;
    PORT
      LAYER M4 ;
        RECT  21.516 10.128 21.6 10.152 ;
    END
  END o[2]
  PIN o[300]
    DIRECTION OUTPUT ;
    USE SIGNAL ;
    PORT
      LAYER M4 ;
        RECT  21.516 24.144 21.6 24.168 ;
    END
  END o[300]
  PIN o[301]
    DIRECTION OUTPUT ;
    USE SIGNAL ;
    PORT
      LAYER M4 ;
        RECT  21.516 24.24 21.6 24.264 ;
    END
  END o[301]
  PIN o[302]
    DIRECTION OUTPUT ;
    USE SIGNAL ;
    PORT
      LAYER M4 ;
        RECT  21.516 24.336 21.6 24.36 ;
    END
  END o[302]
  PIN o[303]
    DIRECTION OUTPUT ;
    USE SIGNAL ;
    PORT
      LAYER M4 ;
        RECT  21.516 24.432 21.6 24.456 ;
    END
  END o[303]
  PIN o[30]
    DIRECTION OUTPUT ;
    USE SIGNAL ;
    PORT
      LAYER M4 ;
        RECT  21.516 12.816 21.6 12.84 ;
    END
  END o[30]
  PIN o[31]
    DIRECTION OUTPUT ;
    USE SIGNAL ;
    PORT
      LAYER M4 ;
        RECT  21.516 12.912 21.6 12.936 ;
    END
  END o[31]
  PIN o[32]
    DIRECTION OUTPUT ;
    USE SIGNAL ;
    PORT
      LAYER M4 ;
        RECT  21.516 26.064 21.6 26.088 ;
    END
  END o[32]
  PIN o[33]
    DIRECTION OUTPUT ;
    USE SIGNAL ;
    PORT
      LAYER M4 ;
        RECT  21.516 26.16 21.6 26.184 ;
    END
  END o[33]
  PIN o[34]
    DIRECTION OUTPUT ;
    USE SIGNAL ;
    PORT
      LAYER M4 ;
        RECT  21.516 26.256 21.6 26.28 ;
    END
  END o[34]
  PIN o[35]
    DIRECTION OUTPUT ;
    USE SIGNAL ;
    PORT
      LAYER M4 ;
        RECT  21.516 26.352 21.6 26.376 ;
    END
  END o[35]
  PIN o[36]
    DIRECTION OUTPUT ;
    USE SIGNAL ;
    PORT
      LAYER M4 ;
        RECT  21.516 26.448 21.6 26.472 ;
    END
  END o[36]
  PIN o[37]
    DIRECTION OUTPUT ;
    USE SIGNAL ;
    PORT
      LAYER M4 ;
        RECT  21.516 26.544 21.6 26.568 ;
    END
  END o[37]
  PIN o[38]
    DIRECTION OUTPUT ;
    USE SIGNAL ;
    PORT
      LAYER M4 ;
        RECT  21.516 26.64 21.6 26.664 ;
    END
  END o[38]
  PIN o[39]
    DIRECTION OUTPUT ;
    USE SIGNAL ;
    PORT
      LAYER M4 ;
        RECT  21.516 26.736 21.6 26.76 ;
    END
  END o[39]
  PIN o[3]
    DIRECTION OUTPUT ;
    USE SIGNAL ;
    PORT
      LAYER M4 ;
        RECT  21.516 10.224 21.6 10.248 ;
    END
  END o[3]
  PIN o[40]
    DIRECTION OUTPUT ;
    USE SIGNAL ;
    PORT
      LAYER M4 ;
        RECT  21.516 26.832 21.6 26.856 ;
    END
  END o[40]
  PIN o[41]
    DIRECTION OUTPUT ;
    USE SIGNAL ;
    PORT
      LAYER M4 ;
        RECT  21.516 26.928 21.6 26.952 ;
    END
  END o[41]
  PIN o[42]
    DIRECTION OUTPUT ;
    USE SIGNAL ;
    PORT
      LAYER M4 ;
        RECT  21.516 27.024 21.6 27.048 ;
    END
  END o[42]
  PIN o[43]
    DIRECTION OUTPUT ;
    USE SIGNAL ;
    PORT
      LAYER M4 ;
        RECT  21.516 27.12 21.6 27.144 ;
    END
  END o[43]
  PIN o[44]
    DIRECTION OUTPUT ;
    USE SIGNAL ;
    PORT
      LAYER M4 ;
        RECT  21.516 27.216 21.6 27.24 ;
    END
  END o[44]
  PIN o[45]
    DIRECTION OUTPUT ;
    USE SIGNAL ;
    PORT
      LAYER M4 ;
        RECT  21.516 27.312 21.6 27.336 ;
    END
  END o[45]
  PIN o[46]
    DIRECTION OUTPUT ;
    USE SIGNAL ;
    PORT
      LAYER M4 ;
        RECT  21.516 27.408 21.6 27.432 ;
    END
  END o[46]
  PIN o[47]
    DIRECTION OUTPUT ;
    USE SIGNAL ;
    PORT
      LAYER M4 ;
        RECT  21.516 27.504 21.6 27.528 ;
    END
  END o[47]
  PIN o[48]
    DIRECTION OUTPUT ;
    USE SIGNAL ;
    PORT
      LAYER M4 ;
        RECT  21.516 27.6 21.6 27.624 ;
    END
  END o[48]
  PIN o[49]
    DIRECTION OUTPUT ;
    USE SIGNAL ;
    PORT
      LAYER M4 ;
        RECT  21.516 27.696 21.6 27.72 ;
    END
  END o[49]
  PIN o[4]
    DIRECTION OUTPUT ;
    USE SIGNAL ;
    PORT
      LAYER M4 ;
        RECT  21.516 10.32 21.6 10.344 ;
    END
  END o[4]
  PIN o[50]
    DIRECTION OUTPUT ;
    USE SIGNAL ;
    PORT
      LAYER M4 ;
        RECT  21.516 27.792 21.6 27.816 ;
    END
  END o[50]
  PIN o[51]
    DIRECTION OUTPUT ;
    USE SIGNAL ;
    PORT
      LAYER M4 ;
        RECT  21.516 27.888 21.6 27.912 ;
    END
  END o[51]
  PIN o[52]
    DIRECTION OUTPUT ;
    USE SIGNAL ;
    PORT
      LAYER M4 ;
        RECT  21.516 27.984 21.6 28.008 ;
    END
  END o[52]
  PIN o[53]
    DIRECTION OUTPUT ;
    USE SIGNAL ;
    PORT
      LAYER M4 ;
        RECT  21.516 28.08 21.6 28.104 ;
    END
  END o[53]
  PIN o[54]
    DIRECTION OUTPUT ;
    USE SIGNAL ;
    PORT
      LAYER M4 ;
        RECT  21.516 28.176 21.6 28.2 ;
    END
  END o[54]
  PIN o[55]
    DIRECTION OUTPUT ;
    USE SIGNAL ;
    PORT
      LAYER M4 ;
        RECT  21.516 28.272 21.6 28.296 ;
    END
  END o[55]
  PIN o[56]
    DIRECTION OUTPUT ;
    USE SIGNAL ;
    PORT
      LAYER M4 ;
        RECT  21.516 28.368 21.6 28.392 ;
    END
  END o[56]
  PIN o[57]
    DIRECTION OUTPUT ;
    USE SIGNAL ;
    PORT
      LAYER M4 ;
        RECT  21.516 28.464 21.6 28.488 ;
    END
  END o[57]
  PIN o[58]
    DIRECTION OUTPUT ;
    USE SIGNAL ;
    PORT
      LAYER M4 ;
        RECT  21.516 28.56 21.6 28.584 ;
    END
  END o[58]
  PIN o[59]
    DIRECTION OUTPUT ;
    USE SIGNAL ;
    PORT
      LAYER M4 ;
        RECT  21.516 28.656 21.6 28.68 ;
    END
  END o[59]
  PIN o[5]
    DIRECTION OUTPUT ;
    USE SIGNAL ;
    PORT
      LAYER M4 ;
        RECT  21.516 10.416 21.6 10.44 ;
    END
  END o[5]
  PIN o[60]
    DIRECTION OUTPUT ;
    USE SIGNAL ;
    PORT
      LAYER M4 ;
        RECT  21.516 28.752 21.6 28.776 ;
    END
  END o[60]
  PIN o[61]
    DIRECTION OUTPUT ;
    USE SIGNAL ;
    PORT
      LAYER M4 ;
        RECT  21.516 28.848 21.6 28.872 ;
    END
  END o[61]
  PIN o[62]
    DIRECTION OUTPUT ;
    USE SIGNAL ;
    PORT
      LAYER M4 ;
        RECT  21.516 28.944 21.6 28.968 ;
    END
  END o[62]
  PIN o[63]
    DIRECTION OUTPUT ;
    USE SIGNAL ;
    PORT
      LAYER M4 ;
        RECT  21.516 29.04 21.6 29.064 ;
    END
  END o[63]
  PIN o[64]
    DIRECTION OUTPUT ;
    USE SIGNAL ;
    PORT
      LAYER M4 ;
        RECT  21.516 0.72 21.6 0.744 ;
    END
  END o[64]
  PIN o[65]
    DIRECTION OUTPUT ;
    USE SIGNAL ;
    PORT
      LAYER M4 ;
        RECT  21.516 0.816 21.6 0.84 ;
    END
  END o[65]
  PIN o[66]
    DIRECTION OUTPUT ;
    USE SIGNAL ;
    PORT
      LAYER M4 ;
        RECT  21.516 0.912 21.6 0.936 ;
    END
  END o[66]
  PIN o[67]
    DIRECTION OUTPUT ;
    USE SIGNAL ;
    PORT
      LAYER M4 ;
        RECT  21.516 1.008 21.6 1.032 ;
    END
  END o[67]
  PIN o[68]
    DIRECTION OUTPUT ;
    USE SIGNAL ;
    PORT
      LAYER M4 ;
        RECT  21.516 1.104 21.6 1.128 ;
    END
  END o[68]
  PIN o[69]
    DIRECTION OUTPUT ;
    USE SIGNAL ;
    PORT
      LAYER M4 ;
        RECT  21.516 1.2 21.6 1.224 ;
    END
  END o[69]
  PIN o[6]
    DIRECTION OUTPUT ;
    USE SIGNAL ;
    PORT
      LAYER M4 ;
        RECT  21.516 10.512 21.6 10.536 ;
    END
  END o[6]
  PIN o[70]
    DIRECTION OUTPUT ;
    USE SIGNAL ;
    PORT
      LAYER M4 ;
        RECT  21.516 1.296 21.6 1.32 ;
    END
  END o[70]
  PIN o[71]
    DIRECTION OUTPUT ;
    USE SIGNAL ;
    PORT
      LAYER M4 ;
        RECT  21.516 1.392 21.6 1.416 ;
    END
  END o[71]
  PIN o[72]
    DIRECTION OUTPUT ;
    USE SIGNAL ;
    PORT
      LAYER M4 ;
        RECT  21.516 1.488 21.6 1.512 ;
    END
  END o[72]
  PIN o[73]
    DIRECTION OUTPUT ;
    USE SIGNAL ;
    PORT
      LAYER M4 ;
        RECT  21.516 1.584 21.6 1.608 ;
    END
  END o[73]
  PIN o[74]
    DIRECTION OUTPUT ;
    USE SIGNAL ;
    PORT
      LAYER M4 ;
        RECT  21.516 1.68 21.6 1.704 ;
    END
  END o[74]
  PIN o[75]
    DIRECTION OUTPUT ;
    USE SIGNAL ;
    PORT
      LAYER M4 ;
        RECT  21.516 1.776 21.6 1.8 ;
    END
  END o[75]
  PIN o[76]
    DIRECTION OUTPUT ;
    USE SIGNAL ;
    PORT
      LAYER M4 ;
        RECT  21.516 1.872 21.6 1.896 ;
    END
  END o[76]
  PIN o[77]
    DIRECTION OUTPUT ;
    USE SIGNAL ;
    PORT
      LAYER M4 ;
        RECT  21.516 1.968 21.6 1.992 ;
    END
  END o[77]
  PIN o[78]
    DIRECTION OUTPUT ;
    USE SIGNAL ;
    PORT
      LAYER M4 ;
        RECT  21.516 2.064 21.6 2.088 ;
    END
  END o[78]
  PIN o[79]
    DIRECTION OUTPUT ;
    USE SIGNAL ;
    PORT
      LAYER M4 ;
        RECT  21.516 2.16 21.6 2.184 ;
    END
  END o[79]
  PIN o[7]
    DIRECTION OUTPUT ;
    USE SIGNAL ;
    PORT
      LAYER M4 ;
        RECT  21.516 10.608 21.6 10.632 ;
    END
  END o[7]
  PIN o[80]
    DIRECTION OUTPUT ;
    USE SIGNAL ;
    PORT
      LAYER M4 ;
        RECT  21.516 2.256 21.6 2.28 ;
    END
  END o[80]
  PIN o[81]
    DIRECTION OUTPUT ;
    USE SIGNAL ;
    PORT
      LAYER M4 ;
        RECT  21.516 2.352 21.6 2.376 ;
    END
  END o[81]
  PIN o[82]
    DIRECTION OUTPUT ;
    USE SIGNAL ;
    PORT
      LAYER M4 ;
        RECT  21.516 2.448 21.6 2.472 ;
    END
  END o[82]
  PIN o[83]
    DIRECTION OUTPUT ;
    USE SIGNAL ;
    PORT
      LAYER M4 ;
        RECT  21.516 2.544 21.6 2.568 ;
    END
  END o[83]
  PIN o[84]
    DIRECTION OUTPUT ;
    USE SIGNAL ;
    PORT
      LAYER M4 ;
        RECT  21.516 2.64 21.6 2.664 ;
    END
  END o[84]
  PIN o[85]
    DIRECTION OUTPUT ;
    USE SIGNAL ;
    PORT
      LAYER M4 ;
        RECT  21.516 2.736 21.6 2.76 ;
    END
  END o[85]
  PIN o[86]
    DIRECTION OUTPUT ;
    USE SIGNAL ;
    PORT
      LAYER M4 ;
        RECT  21.516 2.832 21.6 2.856 ;
    END
  END o[86]
  PIN o[87]
    DIRECTION OUTPUT ;
    USE SIGNAL ;
    PORT
      LAYER M4 ;
        RECT  21.516 2.928 21.6 2.952 ;
    END
  END o[87]
  PIN o[88]
    DIRECTION OUTPUT ;
    USE SIGNAL ;
    PORT
      LAYER M4 ;
        RECT  21.516 3.024 21.6 3.048 ;
    END
  END o[88]
  PIN o[89]
    DIRECTION OUTPUT ;
    USE SIGNAL ;
    PORT
      LAYER M4 ;
        RECT  21.516 3.12 21.6 3.144 ;
    END
  END o[89]
  PIN o[8]
    DIRECTION OUTPUT ;
    USE SIGNAL ;
    PORT
      LAYER M4 ;
        RECT  21.516 10.704 21.6 10.728 ;
    END
  END o[8]
  PIN o[90]
    DIRECTION OUTPUT ;
    USE SIGNAL ;
    PORT
      LAYER M4 ;
        RECT  21.516 3.216 21.6 3.24 ;
    END
  END o[90]
  PIN o[91]
    DIRECTION OUTPUT ;
    USE SIGNAL ;
    PORT
      LAYER M4 ;
        RECT  21.516 3.312 21.6 3.336 ;
    END
  END o[91]
  PIN o[92]
    DIRECTION OUTPUT ;
    USE SIGNAL ;
    PORT
      LAYER M4 ;
        RECT  21.516 3.408 21.6 3.432 ;
    END
  END o[92]
  PIN o[93]
    DIRECTION OUTPUT ;
    USE SIGNAL ;
    PORT
      LAYER M4 ;
        RECT  21.516 3.504 21.6 3.528 ;
    END
  END o[93]
  PIN o[94]
    DIRECTION OUTPUT ;
    USE SIGNAL ;
    PORT
      LAYER M4 ;
        RECT  21.516 3.6 21.6 3.624 ;
    END
  END o[94]
  PIN o[95]
    DIRECTION OUTPUT ;
    USE SIGNAL ;
    PORT
      LAYER M4 ;
        RECT  21.516 3.696 21.6 3.72 ;
    END
  END o[95]
  PIN o[96]
    DIRECTION OUTPUT ;
    USE SIGNAL ;
    PORT
      LAYER M4 ;
        RECT  21.516 6.864 21.6 6.888 ;
    END
  END o[96]
  PIN o[97]
    DIRECTION OUTPUT ;
    USE SIGNAL ;
    PORT
      LAYER M4 ;
        RECT  21.516 6.96 21.6 6.984 ;
    END
  END o[97]
  PIN o[98]
    DIRECTION OUTPUT ;
    USE SIGNAL ;
    PORT
      LAYER M4 ;
        RECT  21.516 7.056 21.6 7.08 ;
    END
  END o[98]
  PIN o[99]
    DIRECTION OUTPUT ;
    USE SIGNAL ;
    PORT
      LAYER M4 ;
        RECT  21.516 7.152 21.6 7.176 ;
    END
  END o[99]
  PIN o[9]
    DIRECTION OUTPUT ;
    USE SIGNAL ;
    PORT
      LAYER M4 ;
        RECT  21.516 10.8 21.6 10.824 ;
    END
  END o[9]
  PIN rs
    DIRECTION INPUT ;
    USE SIGNAL ;
    PORT
      LAYER M5 ;
        RECT  13.104 0 13.128 0.084 ;
    END
  END rs
  PIN rso
    DIRECTION OUTPUT ;
    USE SIGNAL ;
    PORT
      LAYER M4 ;
        RECT  21.516 24.528 21.6 24.552 ;
    END
  END rso
  PIN VDD
    DIRECTION INOUT ;
    USE POWER ;
    PORT
      LAYER M5 ;
        RECT  18.792 2.151 18.912 32.409 ;
        RECT  16.092 2.151 16.212 32.409 ;
        RECT  13.392 2.151 13.512 32.409 ;
        RECT  10.692 2.151 10.812 32.409 ;
        RECT  7.992 2.151 8.112 32.409 ;
        RECT  5.292 2.151 5.412 32.409 ;
        RECT  2.592 2.151 2.712 32.409 ;
    END
  END VDD
  PIN VSS
    DIRECTION INOUT ;
    USE GROUND ;
    PORT
      LAYER M5 ;
        RECT  18.6 2.137 18.72 32.423 ;
        RECT  15.9 2.137 16.02 32.423 ;
        RECT  13.2 2.137 13.32 32.423 ;
        RECT  10.5 2.137 10.62 32.423 ;
        RECT  7.8 2.137 7.92 32.423 ;
        RECT  5.1 2.137 5.22 32.423 ;
        RECT  2.4 2.137 2.52 32.423 ;
    END
  END VSS
  # OT_OBS_CLOSED layer=M5 d_um=1.536 added=38
  OBS
    LAYER RVTN ;
     RECT  2.16 2.16 19.44 2.295 ;
     RECT  2.16 2.565 19.44 2.835 ;
     RECT  2.16 3.105 19.44 3.375 ;
     RECT  2.16 3.645 19.44 3.915 ;
     RECT  2.16 4.185 19.44 4.455 ;
     RECT  2.16 4.725 19.44 4.995 ;
     RECT  2.16 5.265 19.44 5.535 ;
     RECT  2.16 5.805 19.44 6.075 ;
     RECT  2.16 6.345 19.44 6.615 ;
     RECT  2.16 6.885 19.44 7.155 ;
     RECT  2.16 7.425 19.44 7.695 ;
     RECT  2.16 7.965 19.44 8.235 ;
     RECT  2.16 8.505 19.44 8.775 ;
     RECT  2.16 9.045 19.44 9.315 ;
     RECT  2.16 9.585 19.44 9.855 ;
     RECT  2.16 10.125 19.44 10.395 ;
     RECT  2.16 10.665 19.44 10.935 ;
     RECT  2.16 11.205 19.44 11.475 ;
     RECT  2.16 11.745 19.44 12.015 ;
     RECT  2.16 12.285 19.44 12.555 ;
     RECT  2.16 12.825 19.44 13.095 ;
     RECT  2.16 13.365 19.44 13.635 ;
     RECT  2.16 13.905 19.44 14.175 ;
     RECT  2.16 14.445 19.44 14.715 ;
     RECT  2.16 14.985 19.44 15.255 ;
     RECT  2.16 15.525 19.44 15.795 ;
     RECT  2.16 16.065 19.44 16.335 ;
     RECT  2.16 16.605 19.44 16.875 ;
     RECT  2.16 17.145 19.44 17.415 ;
     RECT  2.16 17.685 19.44 17.955 ;
     RECT  2.16 18.225 19.44 18.495 ;
     RECT  2.16 18.765 19.44 19.035 ;
     RECT  2.16 19.305 19.44 19.575 ;
     RECT  2.16 19.845 19.44 20.115 ;
     RECT  2.16 20.385 19.44 20.655 ;
     RECT  2.16 20.925 19.44 21.195 ;
     RECT  2.16 21.465 19.44 21.735 ;
     RECT  2.16 22.005 19.44 22.275 ;
     RECT  2.16 22.545 19.44 22.815 ;
     RECT  2.16 23.085 19.44 23.355 ;
     RECT  2.16 23.625 19.44 23.895 ;
     RECT  2.16 24.165 19.44 24.435 ;
     RECT  2.16 24.705 19.44 24.975 ;
     RECT  2.16 25.245 19.44 25.515 ;
     RECT  2.16 25.785 19.44 26.055 ;
     RECT  2.16 26.325 19.44 26.595 ;
     RECT  2.16 26.865 19.44 27.135 ;
     RECT  2.16 27.405 19.44 27.675 ;
     RECT  2.16 27.945 19.44 28.215 ;
     RECT  2.16 28.485 19.44 28.755 ;
     RECT  2.16 29.025 19.44 29.295 ;
     RECT  2.16 29.565 19.44 29.835 ;
     RECT  2.16 30.105 19.44 30.375 ;
     RECT  2.16 30.645 19.44 30.915 ;
     RECT  2.16 31.185 19.44 31.455 ;
     RECT  2.16 31.725 19.44 31.995 ;
     RECT  2.16 32.265 19.44 32.4 ;
    LAYER RVTP ;
     RECT  2.16 2.295 19.44 2.565 ;
     RECT  2.16 2.835 19.44 3.105 ;
     RECT  2.16 3.375 19.44 3.645 ;
     RECT  2.16 3.915 19.44 4.185 ;
     RECT  2.16 4.455 19.44 4.725 ;
     RECT  2.16 4.995 19.44 5.265 ;
     RECT  2.16 5.535 19.44 5.805 ;
     RECT  2.16 6.075 19.44 6.345 ;
     RECT  2.16 6.615 19.44 6.885 ;
     RECT  2.16 7.155 19.44 7.425 ;
     RECT  2.16 7.695 19.44 7.965 ;
     RECT  2.16 8.235 19.44 8.505 ;
     RECT  2.16 8.775 19.44 9.045 ;
     RECT  2.16 9.315 19.44 9.585 ;
     RECT  2.16 9.855 19.44 10.125 ;
     RECT  2.16 10.395 19.44 10.665 ;
     RECT  2.16 10.935 19.44 11.205 ;
     RECT  2.16 11.475 19.44 11.745 ;
     RECT  2.16 12.015 19.44 12.285 ;
     RECT  2.16 12.555 19.44 12.825 ;
     RECT  2.16 13.095 19.44 13.365 ;
     RECT  2.16 13.635 19.44 13.905 ;
     RECT  2.16 14.175 19.44 14.445 ;
     RECT  2.16 14.715 19.44 14.985 ;
     RECT  2.16 15.255 19.44 15.525 ;
     RECT  2.16 15.795 19.44 16.065 ;
     RECT  2.16 16.335 19.44 16.605 ;
     RECT  2.16 16.875 19.44 17.145 ;
     RECT  2.16 17.415 19.44 17.685 ;
     RECT  2.16 17.955 19.44 18.225 ;
     RECT  2.16 18.495 19.44 18.765 ;
     RECT  2.16 19.035 19.44 19.305 ;
     RECT  2.16 19.575 19.44 19.845 ;
     RECT  2.16 20.115 19.44 20.385 ;
     RECT  2.16 20.655 19.44 20.925 ;
     RECT  2.16 21.195 19.44 21.465 ;
     RECT  2.16 21.735 19.44 22.005 ;
     RECT  2.16 22.275 19.44 22.545 ;
     RECT  2.16 22.815 19.44 23.085 ;
     RECT  2.16 23.355 19.44 23.625 ;
     RECT  2.16 23.895 19.44 24.165 ;
     RECT  2.16 24.435 19.44 24.705 ;
     RECT  2.16 24.975 19.44 25.245 ;
     RECT  2.16 25.515 19.44 25.785 ;
     RECT  2.16 26.055 19.44 26.325 ;
     RECT  2.16 26.595 19.44 26.865 ;
     RECT  2.16 27.135 19.44 27.405 ;
     RECT  2.16 27.675 19.44 27.945 ;
     RECT  2.16 28.215 19.44 28.485 ;
     RECT  2.16 28.755 19.44 29.025 ;
     RECT  2.16 29.295 19.44 29.565 ;
     RECT  2.16 29.835 19.44 30.105 ;
     RECT  2.16 30.375 19.44 30.645 ;
     RECT  2.16 30.915 19.44 31.185 ;
     RECT  2.16 31.455 19.44 31.725 ;
     RECT  2.16 31.995 19.44 32.265 ;
    LAYER M1 ;
     RECT  2.16 2.151 19.44 32.409 ;
    LAYER M2 ;
     RECT  0.031 17.766 0.103 17.784 ;
     RECT  0.031 21.168 0.103 21.186 ;
     RECT  0.103 12.492 0.139 12.51 ;
     RECT  0.103 13.41 0.139 13.428 ;
     RECT  0.103 15.3 0.139 15.858 ;
     RECT  0.103 19.008 0.139 19.026 ;
     RECT  0.103 20.7 0.139 21.186 ;
     RECT  0.139 20.322 0.167 21.186 ;
     RECT  0.139 19.008 0.175 19.26 ;
     RECT  0.167 20.322 0.175 20.718 ;
     RECT  0.139 12.492 0.211 13.428 ;
     RECT  0.103 17.352 0.247 17.784 ;
     RECT  0.247 17.352 0.283 17.982 ;
     RECT  0.175 19.008 0.283 20.718 ;
     RECT  0.103 30.852 0.355 30.87 ;
     RECT  0.355 30.852 0.499 31.104 ;
     RECT  0.103 2.502 0.535 2.52 ;
     RECT  0.175 23.328 0.535 23.346 ;
     RECT  0.499 30.384 0.563 31.518 ;
     RECT  0.211 12.492 1.147 13.968 ;
     RECT  1.147 11.826 1.723 13.968 ;
     RECT  0.563 31.5 1.723 31.518 ;
     RECT  1.291 10.404 1.975 10.422 ;
     RECT  0.535 2.502 2.16 3.204 ;
     RECT  0.103 4.5 2.16 4.518 ;
     RECT  1.975 10.404 2.16 10.998 ;
     RECT  1.723 11.79 2.16 13.968 ;
     RECT  0.139 15.03 2.16 15.858 ;
     RECT  0.283 17.352 2.16 20.718 ;
     RECT  0.103 22.212 2.16 22.23 ;
     RECT  0.535 23.166 2.16 23.346 ;
     RECT  0.535 25.02 2.16 26.118 ;
     RECT  0.103 27.882 2.16 27.9 ;
     RECT  0.535 28.836 2.16 28.854 ;
     RECT  0.563 30.384 2.16 30.402 ;
     RECT  1.723 31.23 2.16 31.518 ;
     RECT  0.535 32.436 2.16 32.454 ;
     RECT  2.16 2.151 2.299 32.454 ;
     RECT  2.299 2.106 2.767 32.454 ;
     RECT  2.767 1.926 3.019 32.454 ;
     RECT  3.019 1.926 4.451 32.49 ;
     RECT  4.451 1.998 5.279 32.49 ;
     RECT  5.279 1.998 6.151 32.454 ;
     RECT  6.151 1.998 6.539 32.49 ;
     RECT  6.539 2.034 6.827 32.49 ;
     RECT  6.827 2.106 7.763 32.49 ;
     RECT  7.763 2.151 10.219 32.49 ;
     RECT  10.219 2.034 11.399 32.49 ;
     RECT  11.399 2.034 15.223 32.409 ;
     RECT  15.223 1.962 17.591 32.409 ;
     RECT  17.591 1.998 19.103 32.409 ;
     RECT  19.103 2.034 19.44 32.409 ;
     RECT  19.44 25.866 19.931 32.292 ;
     RECT  19.44 2.034 20.219 24.966 ;
     RECT  20.219 2.034 20.291 22.5 ;
     RECT  20.291 2.034 20.435 9.234 ;
     RECT  20.291 10.026 20.435 22.5 ;
     RECT  20.435 2.106 20.471 4.554 ;
     RECT  20.435 10.026 20.471 14.094 ;
     RECT  20.435 15.156 20.471 22.5 ;
     RECT  20.471 2.106 20.507 2.286 ;
     RECT  20.435 5.436 20.507 9.234 ;
     RECT  20.471 10.026 20.507 12.852 ;
     RECT  20.471 13.986 20.507 14.094 ;
     RECT  20.471 15.336 20.507 19.224 ;
     RECT  20.471 20.016 20.507 22.5 ;
     RECT  20.219 23.256 20.507 24.894 ;
     RECT  19.931 25.866 20.507 32.184 ;
     RECT  20.471 3.384 20.543 4.554 ;
     RECT  20.507 5.706 20.543 6.759 ;
     RECT  20.507 10.836 20.543 11.844 ;
     RECT  20.507 13.986 20.543 14.004 ;
     RECT  20.507 15.336 20.543 16.092 ;
     RECT  20.507 21.591 20.543 21.609 ;
     RECT  20.507 26.406 20.543 27.702 ;
     RECT  20.507 28.836 20.543 28.854 ;
     RECT  20.507 29.88 20.543 31.752 ;
     RECT  20.507 17.046 20.579 18.216 ;
     RECT  20.543 26.568 20.579 26.784 ;
     RECT  20.543 11.79 20.615 11.808 ;
     RECT  20.579 26.568 20.615 26.586 ;
     RECT  20.543 15.57 21.343 16.092 ;
     RECT  20.507 7.866 21.407 8.964 ;
     RECT  20.543 3.384 21.415 3.978 ;
     RECT  21.407 8.136 21.415 8.964 ;
     RECT  20.507 23.796 21.415 23.958 ;
     RECT  21.415 3.042 21.443 3.978 ;
     RECT  21.343 14.958 21.443 16.092 ;
     RECT  21.443 3.042 21.479 3.942 ;
     RECT  21.415 8.136 21.479 9.189 ;
     RECT  20.543 10.836 21.479 10.89 ;
     RECT  20.579 17.766 21.479 18.216 ;
     RECT  20.507 19.206 21.479 19.224 ;
     RECT  20.543 30.186 21.479 31.752 ;
     RECT  20.507 2.268 21.487 2.286 ;
     RECT  21.479 3.042 21.487 3.06 ;
     RECT  21.487 2.268 21.515 3.06 ;
     RECT  21.479 3.924 21.515 3.942 ;
     RECT  20.543 5.706 21.515 6.138 ;
     RECT  21.479 8.856 21.515 9.189 ;
     RECT  21.415 9.936 21.515 9.954 ;
     RECT  21.479 10.872 21.515 10.89 ;
     RECT  20.507 12.834 21.515 12.852 ;
     RECT  21.443 16.074 21.515 16.092 ;
     RECT  21.479 17.766 21.515 17.784 ;
     RECT  20.507 20.016 21.515 20.682 ;
     RECT  21.415 23.796 21.515 24.084 ;
     RECT  20.543 27.576 21.515 27.594 ;
     RECT  21.479 30.924 21.515 31.644 ;
     RECT  21.515 2.772 21.587 2.79 ;
     RECT  21.515 5.706 21.587 5.724 ;
    LAYER M3 ;
     RECT  19.908 0.715 19.926 1.195 ;
     RECT  19.908 1.195 20.502 1.387 ;
     RECT  17.388 0.811 17.406 1.579 ;
     RECT  17.388 1.579 17.514 1.675 ;
     RECT  19.872 1.387 20.502 1.867 ;
     RECT  4.428 1.921 4.446 1.993 ;
     RECT  17.388 1.675 17.802 1.993 ;
     RECT  18.936 1.483 18.954 1.993 ;
     RECT  4.068 1.993 4.446 2.029 ;
     RECT  6.516 1.993 6.534 2.029 ;
     RECT  15.228 1.957 15.246 2.029 ;
     RECT  19.872 1.867 20.538 2.056 ;
     RECT  14.508 2.029 15.246 2.065 ;
     RECT  16.056 1.993 16.074 2.065 ;
     RECT  17.316 1.993 19.098 2.065 ;
     RECT  2.772 1.921 2.79 2.101 ;
     RECT  3.78 2.029 4.446 2.101 ;
     RECT  11.772 2.065 11.79 2.101 ;
     RECT  13.716 2.065 13.734 2.101 ;
     RECT  14.508 2.065 16.074 2.101 ;
     RECT  3.672 2.101 4.446 2.143 ;
     RECT  7.74 2.101 7.758 2.143 ;
     RECT  10.224 2.029 10.242 2.143 ;
     RECT  13.716 2.101 16.506 2.143 ;
     RECT  2.304 2.101 2.79 2.191 ;
     RECT  3.672 2.143 5.205 2.191 ;
     RECT  13.215 2.143 16.506 2.191 ;
     RECT  17.244 2.065 19.098 2.191 ;
     RECT  2.304 2.191 5.205 2.227 ;
     RECT  10.224 2.143 10.605 2.251 ;
     RECT  11.448 2.101 11.79 2.251 ;
     RECT  2.304 2.227 5.526 2.299 ;
     RECT  6.516 2.029 6.822 2.299 ;
     RECT  7.74 2.143 7.905 2.299 ;
     RECT  9.72 2.251 11.79 2.299 ;
     RECT  13.215 2.191 19.098 2.299 ;
     RECT  2.304 2.299 6.822 2.335 ;
     RECT  7.74 2.299 8.514 2.335 ;
     RECT  9.468 2.299 19.098 2.335 ;
     RECT  19.836 2.056 20.538 2.335 ;
     RECT  0.144 2.491 0.162 2.497 ;
     RECT  2.304 2.335 20.538 2.641 ;
     RECT  2.268 2.641 20.538 2.765 ;
     RECT  21.492 2.263 21.51 2.767 ;
     RECT  0.108 2.497 0.162 2.923 ;
     RECT  21.492 2.767 21.582 3.037 ;
     RECT  0.108 2.923 0.342 3.053 ;
     RECT  21.42 3.037 21.582 3.101 ;
     RECT  2.304 2.765 20.538 3.403 ;
     RECT  0.54 3.181 0.558 3.437 ;
     RECT  2.304 3.403 20.574 3.499 ;
     RECT  2.304 3.499 20.61 3.677 ;
     RECT  2.304 3.677 20.574 3.787 ;
     RECT  2.268 3.787 20.574 3.911 ;
     RECT  2.268 3.911 20.538 3.917 ;
     RECT  9.864 3.917 20.538 3.947 ;
     RECT  21.456 3.101 21.582 3.955 ;
     RECT  0.144 4.267 0.162 4.445 ;
     RECT  10.008 3.947 20.538 4.559 ;
     RECT  0.108 4.495 0.126 4.685 ;
     RECT  21.42 3.955 21.582 4.685 ;
     RECT  2.268 3.917 9.126 4.693 ;
     RECT  2.268 4.693 9.198 4.729 ;
     RECT  10.008 4.559 20.502 4.729 ;
     RECT  2.268 4.729 20.502 4.991 ;
     RECT  2.268 4.991 6.39 5.027 ;
     RECT  7.38 4.991 20.502 5.063 ;
     RECT  7.38 5.063 10.926 5.099 ;
     RECT  7.452 5.099 10.926 5.189 ;
     RECT  2.268 5.027 6.21 5.369 ;
     RECT  0.324 5.419 0.342 5.549 ;
     RECT  21.492 4.685 21.582 5.729 ;
     RECT  7.452 5.189 10.854 5.845 ;
     RECT  7.416 5.845 10.854 5.881 ;
     RECT  7.2 5.881 10.854 6.079 ;
     RECT  11.7 5.063 20.502 6.079 ;
     RECT  21.492 5.729 21.51 6.143 ;
     RECT  7.2 6.079 20.502 6.151 ;
     RECT  2.304 5.369 6.21 6.235 ;
     RECT  6.948 6.151 20.502 6.235 ;
     RECT  2.304 6.235 20.502 6.547 ;
     RECT  2.268 6.547 20.502 6.667 ;
     RECT  2.268 6.667 20.538 6.764 ;
     RECT  2.268 6.764 20.502 7.565 ;
     RECT  21.492 7.435 21.51 7.861 ;
     RECT  2.304 7.565 20.502 7.933 ;
     RECT  0.324 8.107 0.342 8.203 ;
     RECT  2.304 7.933 20.574 8.621 ;
     RECT  2.304 8.621 20.538 8.683 ;
     RECT  2.268 8.683 20.538 8.807 ;
     RECT  21.384 7.861 21.51 8.813 ;
     RECT  0.216 8.203 0.342 8.827 ;
     RECT  0.144 8.827 0.342 9.005 ;
     RECT  21.42 8.813 21.51 9.197 ;
     RECT  1.296 8.395 1.314 9.259 ;
     RECT  2.268 8.807 20.502 9.887 ;
     RECT  21.42 9.197 21.438 9.931 ;
     RECT  21.42 9.931 21.51 9.959 ;
     RECT  1.152 9.259 1.314 10.027 ;
     RECT  2.268 9.887 18.897 10.027 ;
     RECT  21.492 9.959 21.51 10.795 ;
     RECT  21.456 10.795 21.51 10.859 ;
     RECT  1.152 10.027 18.897 10.867 ;
     RECT  19.908 9.887 20.502 10.867 ;
     RECT  21.492 10.859 21.51 10.895 ;
     RECT  1.152 10.867 20.502 11.056 ;
     RECT  1.152 11.056 20.538 11.084 ;
     RECT  20.196 11.084 20.538 11.785 ;
     RECT  1.152 11.084 19.422 11.849 ;
     RECT  1.188 11.849 19.422 11.975 ;
     RECT  1.764 11.975 19.422 12.119 ;
     RECT  20.196 11.785 20.61 12.173 ;
     RECT  2.376 12.119 19.422 12.209 ;
     RECT  9.828 12.209 19.422 12.595 ;
     RECT  20.196 12.173 20.502 12.595 ;
     RECT  0.108 12.487 0.126 12.757 ;
     RECT  21.42 12.619 21.438 12.797 ;
     RECT  2.376 12.209 9.054 12.901 ;
     RECT  2.304 12.901 9.054 12.991 ;
     RECT  9.828 12.595 20.502 12.991 ;
     RECT  0.108 12.757 0.198 13.639 ;
     RECT  2.304 12.991 20.502 13.867 ;
     RECT  2.268 13.867 20.502 13.981 ;
     RECT  2.268 13.981 20.538 14.009 ;
     RECT  0.108 13.639 0.558 14.189 ;
     RECT  2.268 14.009 8.946 14.243 ;
     RECT  0.216 14.189 0.558 14.477 ;
     RECT  9.864 14.009 20.538 14.477 ;
     RECT  2.268 14.243 8.622 14.675 ;
     RECT  9.864 14.477 20.502 14.827 ;
     RECT  21.492 12.829 21.51 14.827 ;
     RECT  21.312 14.827 21.51 14.957 ;
     RECT  2.34 14.675 8.622 14.989 ;
     RECT  9.432 14.827 20.502 14.989 ;
     RECT  21.348 14.957 21.51 15.101 ;
     RECT  0.144 15.025 0.162 15.259 ;
     RECT  0.144 15.259 0.558 15.295 ;
     RECT  2.34 14.989 20.502 15.331 ;
     RECT  2.34 15.331 20.538 15.457 ;
     RECT  21.42 15.101 21.51 15.593 ;
     RECT  0.108 15.295 0.558 15.787 ;
     RECT  2.304 15.457 20.538 15.821 ;
     RECT  0.108 15.787 0.666 15.917 ;
     RECT  21.492 15.593 21.51 16.097 ;
     RECT  2.304 15.821 20.502 16.537 ;
     RECT  2.232 16.537 20.502 16.907 ;
     RECT  2.304 16.907 20.502 17.035 ;
     RECT  2.304 17.035 20.574 17.075 ;
     RECT  0.108 15.917 0.126 17.083 ;
     RECT  0.108 17.083 0.162 17.455 ;
     RECT  0.108 17.455 0.558 17.761 ;
     RECT  2.304 17.075 20.502 17.803 ;
     RECT  21.492 17.227 21.51 18.193 ;
     RECT  0.036 17.761 0.558 18.509 ;
     RECT  2.268 17.803 20.502 18.527 ;
     RECT  0.036 18.509 0.522 18.605 ;
     RECT  2.304 18.527 20.502 18.959 ;
     RECT  0.036 18.605 0.378 18.989 ;
     RECT  19.8 18.959 20.502 19.067 ;
     RECT  21.456 18.193 21.51 19.229 ;
     RECT  0.036 18.989 0.342 19.813 ;
     RECT  2.304 18.959 19.026 19.885 ;
     RECT  19.8 19.067 20.466 19.885 ;
     RECT  2.304 19.885 20.466 20.107 ;
     RECT  2.304 20.107 20.502 20.389 ;
     RECT  2.232 20.389 20.502 20.425 ;
     RECT  2.232 20.425 20.574 20.525 ;
     RECT  0.036 19.813 0.558 20.621 ;
     RECT  21.492 19.229 21.51 20.623 ;
     RECT  21.456 20.623 21.51 20.717 ;
     RECT  0.036 20.621 0.162 21.191 ;
     RECT  0.108 21.191 0.162 21.197 ;
     RECT  2.304 20.525 20.574 21.197 ;
     RECT  21.456 20.717 21.474 21.293 ;
     RECT  2.304 21.197 20.538 22.157 ;
     RECT  0.108 21.197 0.126 22.253 ;
     RECT  0.144 22.267 0.198 22.411 ;
     RECT  21.42 22.411 21.438 22.589 ;
     RECT  0.144 22.411 0.342 23.117 ;
     RECT  0.18 23.117 0.342 23.161 ;
     RECT  0.18 23.161 0.558 23.597 ;
     RECT  21.456 22.987 21.51 23.659 ;
     RECT  0.54 23.597 0.558 23.789 ;
     RECT  21.42 23.659 21.51 24.089 ;
     RECT  21.42 24.089 21.438 24.125 ;
     RECT  2.304 22.157 20.502 24.232 ;
     RECT  2.268 24.232 20.502 24.467 ;
     RECT  20.196 24.467 20.502 24.899 ;
     RECT  20.196 24.899 20.214 24.971 ;
     RECT  2.268 24.467 19.386 25.007 ;
     RECT  0.324 24.331 0.342 25.015 ;
     RECT  0.324 25.015 0.558 25.099 ;
     RECT  0.144 25.099 0.558 25.277 ;
     RECT  2.304 25.007 19.386 25.277 ;
     RECT  2.304 25.277 19.314 25.963 ;
     RECT  2.268 25.963 19.314 26.015 ;
     RECT  2.304 26.015 19.314 26.023 ;
     RECT  20.484 25.861 20.502 26.023 ;
     RECT  2.304 26.023 20.502 26.401 ;
     RECT  2.304 26.401 20.538 26.563 ;
     RECT  0.54 25.277 0.558 26.669 ;
     RECT  2.304 26.563 20.61 26.957 ;
     RECT  2.304 26.957 19.422 27.019 ;
     RECT  20.412 26.957 20.61 27.149 ;
     RECT  2.268 27.019 19.422 27.629 ;
     RECT  20.412 27.149 20.538 27.913 ;
     RECT  19.944 27.913 20.538 27.917 ;
     RECT  0.108 27.877 0.126 28.013 ;
     RECT  19.944 27.917 20.502 28.013 ;
     RECT  21.492 27.571 21.51 28.205 ;
     RECT  2.268 27.629 19.098 28.453 ;
     RECT  2.268 28.453 19.422 28.493 ;
     RECT  2.268 28.493 19.098 28.715 ;
     RECT  20.412 28.013 20.502 28.747 ;
     RECT  19.908 28.747 20.502 28.787 ;
     RECT  0.324 28.363 0.342 28.795 ;
     RECT  0.144 28.795 0.342 28.831 ;
     RECT  19.944 28.787 20.502 28.831 ;
     RECT  0.144 28.831 0.558 28.973 ;
     RECT  2.268 28.715 19.062 29.021 ;
     RECT  2.268 29.021 8.226 29.419 ;
     RECT  8.964 29.021 19.062 29.461 ;
     RECT  8.964 29.461 19.134 29.489 ;
     RECT  19.944 28.831 20.538 29.515 ;
     RECT  1.728 29.419 8.226 29.597 ;
     RECT  19.908 29.515 20.538 29.707 ;
     RECT  0.54 28.973 0.558 29.995 ;
     RECT  19.872 29.707 20.538 30.125 ;
     RECT  21.456 30.181 21.474 30.283 ;
     RECT  1.728 29.597 8.19 30.331 ;
     RECT  9 29.489 19.134 30.331 ;
     RECT  1.728 30.331 19.134 30.475 ;
     RECT  19.872 30.125 20.502 30.475 ;
     RECT  0.324 29.995 0.558 30.847 ;
     RECT  0.108 30.847 0.558 30.875 ;
     RECT  0.108 30.875 0.522 30.893 ;
     RECT  1.728 30.475 20.502 31.225 ;
     RECT  1.728 31.225 20.538 31.253 ;
     RECT  2.268 31.253 20.538 31.289 ;
     RECT  2.304 31.289 20.538 31.469 ;
     RECT  21.456 30.283 21.51 31.649 ;
     RECT  21.456 31.649 21.474 31.757 ;
     RECT  0.144 30.893 0.522 31.949 ;
     RECT  2.304 31.469 20.502 31.955 ;
     RECT  14.652 31.955 20.502 32.027 ;
     RECT  2.304 31.955 13.497 32.063 ;
     RECT  15.48 32.027 20.502 32.063 ;
     RECT  2.304 32.063 8.802 32.147 ;
     RECT  9.72 32.063 13.497 32.147 ;
     RECT  9.72 32.147 10.605 32.189 ;
     RECT  11.376 32.147 13.305 32.189 ;
     RECT  14.652 32.027 14.67 32.189 ;
     RECT  15.48 32.063 16.398 32.189 ;
     RECT  17.676 32.063 20.502 32.189 ;
     RECT  8.784 32.147 8.802 32.225 ;
     RECT  11.376 32.189 11.934 32.225 ;
     RECT  2.304 32.147 7.905 32.251 ;
     RECT  17.676 32.189 17.766 32.261 ;
     RECT  17.748 32.261 17.766 32.297 ;
     RECT  18.615 32.189 19.926 32.297 ;
     RECT  2.232 32.251 7.905 32.333 ;
     RECT  11.376 32.225 11.682 32.333 ;
     RECT  5.004 32.333 6.462 32.369 ;
     RECT  9.972 32.189 10.605 32.369 ;
     RECT  15.48 32.189 16.005 32.369 ;
     RECT  18.615 32.297 19.386 32.369 ;
     RECT  7.596 32.333 7.905 32.417 ;
     RECT  10.515 32.369 10.605 32.417 ;
     RECT  13.215 32.189 13.305 32.417 ;
     RECT  15.915 32.369 16.005 32.417 ;
     RECT  18.615 32.369 18.705 32.417 ;
     RECT  2.232 32.333 3.402 32.429 ;
     RECT  0.18 31.949 0.522 32.431 ;
     RECT  5.004 32.369 6.21 32.459 ;
     RECT  7.596 32.417 7.614 32.459 ;
     RECT  5.004 32.459 5.274 32.495 ;
     RECT  6.156 32.459 6.174 32.495 ;
     RECT  11.376 32.333 11.394 32.495 ;
     RECT  5.004 32.495 5.094 32.525 ;
     RECT  0.18 32.431 0.558 32.621 ;
     RECT  5.076 32.525 5.094 32.717 ;
     RECT  0.18 32.621 0.522 32.909 ;
     RECT  0.504 32.909 0.522 33.005 ;
     RECT  2.556 32.429 3.402 33.197 ;
     RECT  2.556 33.197 3.366 33.293 ;
     RECT  2.844 33.293 3.366 33.389 ;
     RECT  2.988 33.389 3.366 33.485 ;
     RECT  2.988 33.485 3.33 33.581 ;
     RECT  2.988 33.581 3.294 33.677 ;
     RECT  2.988 33.677 3.006 33.773 ;
    LAYER M4 ;
     RECT  0.084 13.104 0.137 13.128 ;
     RECT  0.06 13.128 0.137 13.2 ;
     RECT  0.084 13.2 0.137 13.224 ;
     RECT  0.06 13.224 0.137 13.296 ;
     RECT  0.084 13.296 0.137 13.32 ;
     RECT  0.06 13.32 0.137 13.392 ;
     RECT  0.084 13.392 0.137 13.416 ;
     RECT  0.06 13.416 0.137 13.488 ;
     RECT  0.084 13.488 0.137 13.512 ;
     RECT  0.06 13.512 0.137 13.584 ;
     RECT  0.084 13.584 0.137 13.608 ;
     RECT  0.06 13.608 0.137 13.68 ;
     RECT  0.084 13.68 0.137 13.704 ;
     RECT  0.06 13.704 0.137 13.776 ;
     RECT  0.084 13.776 0.137 13.8 ;
     RECT  0.06 13.8 0.137 13.872 ;
     RECT  0.084 13.872 0.137 13.896 ;
     RECT  0.06 13.896 0.137 13.968 ;
     RECT  0.084 13.968 0.137 13.992 ;
     RECT  0.06 13.992 0.137 14.064 ;
     RECT  0.084 14.064 0.137 14.088 ;
     RECT  0.06 14.088 0.137 14.16 ;
     RECT  0.084 14.16 0.137 14.184 ;
     RECT  0.06 14.184 0.137 14.256 ;
     RECT  0.084 14.256 0.137 14.28 ;
     RECT  0.06 14.28 0.137 14.352 ;
     RECT  0.084 14.352 0.137 14.376 ;
     RECT  0.06 14.376 0.137 14.448 ;
     RECT  0.084 14.448 0.137 14.472 ;
     RECT  0.06 14.472 0.137 14.544 ;
     RECT  0.084 14.544 0.137 14.568 ;
     RECT  0.06 14.568 0.137 15.408 ;
     RECT  0.084 15.408 0.137 15.432 ;
     RECT  0.06 15.432 0.137 15.504 ;
     RECT  0.084 15.504 0.137 15.528 ;
     RECT  0.06 15.528 0.137 15.6 ;
     RECT  0.084 15.6 0.137 15.624 ;
     RECT  0.06 15.624 0.137 15.696 ;
     RECT  0.084 15.696 0.137 15.72 ;
     RECT  0.06 15.72 0.137 15.792 ;
     RECT  0.084 15.792 0.137 15.816 ;
     RECT  0.06 15.816 0.137 15.888 ;
     RECT  0.084 15.888 0.137 15.912 ;
     RECT  0.06 15.912 0.137 15.984 ;
     RECT  0.084 15.984 0.137 16.008 ;
     RECT  0.06 16.008 0.137 16.08 ;
     RECT  0.084 16.08 0.137 16.104 ;
     RECT  0.06 16.104 0.137 16.176 ;
     RECT  0.084 16.176 0.137 16.2 ;
     RECT  0.06 16.2 0.137 16.272 ;
     RECT  0.084 16.272 0.137 16.296 ;
     RECT  0.06 16.296 0.137 16.368 ;
     RECT  0.084 16.368 0.137 16.392 ;
     RECT  0.06 16.392 0.137 16.464 ;
     RECT  0.084 16.464 0.137 16.488 ;
     RECT  0.06 16.488 0.137 16.56 ;
     RECT  0.084 16.56 0.137 16.584 ;
     RECT  0.06 16.584 0.137 16.656 ;
     RECT  0.084 16.656 0.137 16.68 ;
     RECT  0.06 16.68 0.137 16.752 ;
     RECT  0.084 16.752 0.137 16.776 ;
     RECT  0.06 16.776 0.137 16.848 ;
     RECT  0.084 16.848 0.137 16.872 ;
     RECT  0.06 16.872 0.137 16.944 ;
     RECT  0.084 16.944 0.137 16.968 ;
     RECT  0.06 16.968 0.137 17.04 ;
     RECT  0.084 17.04 0.137 17.064 ;
     RECT  0.06 17.064 0.137 17.136 ;
     RECT  0.084 17.136 0.137 17.16 ;
     RECT  0.06 17.16 0.137 17.232 ;
     RECT  0.084 17.232 0.137 17.256 ;
     RECT  0.06 17.256 0.137 17.328 ;
     RECT  0.084 17.328 0.137 17.352 ;
     RECT  0.06 17.352 0.137 17.424 ;
     RECT  0.084 17.424 0.137 17.448 ;
     RECT  0.06 17.448 0.137 17.52 ;
     RECT  0.084 17.52 0.137 17.544 ;
     RECT  0.06 17.544 0.137 17.616 ;
     RECT  0.084 17.616 0.137 17.64 ;
     RECT  0.06 17.64 0.137 17.712 ;
     RECT  0.084 17.712 0.137 17.736 ;
     RECT  0.06 17.736 0.137 17.808 ;
     RECT  0.084 17.808 0.137 17.832 ;
     RECT  0.06 17.832 0.137 17.904 ;
     RECT  0.084 17.904 0.137 17.928 ;
     RECT  0.06 17.928 0.137 18 ;
     RECT  0.084 18 0.137 18.024 ;
     RECT  0.06 18.024 0.137 18.096 ;
     RECT  0.084 18.096 0.137 18.12 ;
     RECT  0.06 18.12 0.137 18.192 ;
     RECT  0.084 18.192 0.137 18.216 ;
     RECT  0.06 18.216 0.137 18.288 ;
     RECT  0.084 18.288 0.137 18.312 ;
     RECT  0.06 18.312 0.137 18.384 ;
     RECT  0.084 18.384 0.137 18.408 ;
     RECT  0.06 18.408 0.137 18.48 ;
     RECT  0.084 18.48 0.137 18.504 ;
     RECT  0.06 18.504 0.137 18.576 ;
     RECT  0.084 18.576 0.137 18.6 ;
     RECT  0.06 18.6 0.137 18.672 ;
     RECT  0.084 18.672 0.137 18.696 ;
     RECT  0.06 18.696 0.137 18.768 ;
     RECT  0.084 18.768 0.137 18.792 ;
     RECT  0.06 18.792 0.137 18.864 ;
     RECT  0.084 18.864 0.137 18.888 ;
     RECT  0.06 18.888 0.137 18.96 ;
     RECT  0.084 18.96 0.137 18.984 ;
     RECT  0.06 18.984 0.137 19.056 ;
     RECT  0.084 19.056 0.137 19.08 ;
     RECT  0.06 19.08 0.137 19.152 ;
     RECT  0.084 19.152 0.137 19.176 ;
     RECT  0.06 19.176 0.137 19.248 ;
     RECT  0.084 19.248 0.137 19.272 ;
     RECT  0.06 19.272 0.137 19.344 ;
     RECT  0.084 19.344 0.137 19.368 ;
     RECT  0.06 19.368 0.137 19.44 ;
     RECT  0.084 19.44 0.137 19.464 ;
     RECT  0.06 19.464 0.137 19.536 ;
     RECT  0.084 19.536 0.137 19.56 ;
     RECT  0.06 19.56 0.137 19.632 ;
     RECT  0.084 19.632 0.137 19.656 ;
     RECT  0.06 19.656 0.137 19.728 ;
     RECT  0.084 19.728 0.137 19.752 ;
     RECT  0.06 19.752 0.137 19.824 ;
     RECT  0.084 19.824 0.137 19.848 ;
     RECT  0.06 19.848 0.137 19.92 ;
     RECT  0.084 19.92 0.137 19.944 ;
     RECT  0.06 19.944 0.137 20.016 ;
     RECT  0.084 20.016 0.137 20.04 ;
     RECT  0.06 20.04 0.137 20.112 ;
     RECT  0.084 20.112 0.137 20.136 ;
     RECT  0.06 20.136 0.137 20.208 ;
     RECT  0.084 20.208 0.137 20.232 ;
     RECT  0.06 20.232 0.137 20.304 ;
     RECT  0.084 20.304 0.137 20.328 ;
     RECT  0.06 20.328 0.137 20.4 ;
     RECT  0.084 20.4 0.137 20.424 ;
     RECT  0.06 20.424 0.137 20.496 ;
     RECT  0.084 20.496 0.137 20.52 ;
     RECT  0.06 20.52 0.137 20.592 ;
     RECT  0.084 20.592 0.137 20.616 ;
     RECT  0.06 20.616 0.137 20.688 ;
     RECT  0.084 20.688 0.137 20.712 ;
     RECT  0.06 20.712 0.137 20.784 ;
     RECT  0.084 20.784 0.137 20.808 ;
     RECT  0.06 20.808 0.137 20.88 ;
     RECT  0.084 20.88 0.137 20.904 ;
     RECT  0.06 20.904 0.137 20.976 ;
     RECT  0.084 20.976 0.137 21 ;
     RECT  0.06 21 0.137 21.072 ;
     RECT  0.084 21.072 0.137 21.096 ;
     RECT  0.06 21.096 0.137 21.168 ;
     RECT  0.084 21.168 0.137 21.192 ;
     RECT  0.06 21.192 0.137 21.264 ;
     RECT  0.084 21.264 0.137 21.288 ;
     RECT  0.06 21.288 0.137 21.36 ;
     RECT  0.084 21.36 0.137 21.384 ;
     RECT  0.06 21.384 0.137 21.456 ;
     RECT  0.084 21.456 0.137 21.48 ;
     RECT  0.06 21.48 0.137 21.552 ;
     RECT  0.084 21.552 0.137 21.576 ;
     RECT  0.06 21.576 0.137 21.648 ;
     RECT  0.084 21.648 0.137 21.672 ;
     RECT  0.06 21.672 0.137 21.744 ;
     RECT  0.084 21.744 0.137 21.768 ;
     RECT  0.06 21.768 0.137 21.84 ;
     RECT  0.084 21.84 0.137 21.864 ;
     RECT  0.06 21.864 0.137 21.936 ;
     RECT  0.084 21.936 0.137 21.96 ;
     RECT  0.06 21.96 0.137 22.032 ;
     RECT  0.084 22.032 0.137 22.056 ;
     RECT  0.06 22.056 0.137 22.128 ;
     RECT  0.084 22.128 0.137 22.152 ;
     RECT  0.06 22.152 0.137 22.224 ;
     RECT  0.084 22.224 0.137 22.248 ;
     RECT  0.06 22.248 0.137 22.32 ;
     RECT  0.084 22.32 0.137 22.344 ;
     RECT  0.06 22.344 0.137 22.416 ;
     RECT  0.084 22.416 0.137 22.44 ;
     RECT  0.06 22.44 0.137 22.512 ;
     RECT  0.084 22.512 0.137 22.536 ;
     RECT  0.06 22.536 0.137 22.608 ;
     RECT  0.084 22.608 0.137 22.632 ;
     RECT  0.06 22.632 0.137 22.704 ;
     RECT  0.084 22.704 0.137 22.728 ;
     RECT  0.06 22.728 0.137 22.8 ;
     RECT  0.084 22.8 0.137 22.824 ;
     RECT  0.06 22.824 0.137 22.896 ;
     RECT  0.084 22.896 0.137 22.92 ;
     RECT  0.06 22.92 0.137 22.992 ;
     RECT  0.084 22.992 0.137 23.016 ;
     RECT  0.06 23.016 0.137 23.088 ;
     RECT  0.084 23.088 0.137 23.112 ;
     RECT  0.06 23.112 0.137 23.184 ;
     RECT  0.084 23.184 0.137 23.208 ;
     RECT  0.06 23.208 0.137 23.28 ;
     RECT  0.084 23.28 0.137 23.304 ;
     RECT  0.06 23.304 0.137 23.376 ;
     RECT  0.084 23.376 0.137 23.4 ;
     RECT  0.06 23.4 0.137 23.472 ;
     RECT  0.084 23.472 0.137 23.496 ;
     RECT  0.06 23.496 0.137 23.568 ;
     RECT  0.084 23.568 0.137 23.592 ;
     RECT  0.06 23.592 0.137 23.664 ;
     RECT  0.084 23.664 0.137 23.688 ;
     RECT  0.06 23.688 0.137 23.76 ;
     RECT  0.084 23.76 0.137 23.784 ;
     RECT  0.06 23.784 0.137 23.856 ;
     RECT  0.084 23.856 0.137 23.88 ;
     RECT  0.06 23.88 0.137 23.952 ;
     RECT  0.084 23.952 0.137 23.976 ;
     RECT  0.06 23.976 0.137 24.048 ;
     RECT  0.084 24.048 0.137 24.072 ;
     RECT  0.06 24.072 0.137 24.144 ;
     RECT  0.084 24.144 0.137 24.168 ;
     RECT  0.06 24.168 0.137 24.24 ;
     RECT  0.084 24.24 0.137 24.264 ;
     RECT  0.06 24.264 0.137 24.336 ;
     RECT  0.084 24.336 0.137 24.36 ;
     RECT  0.06 24.36 0.137 24.432 ;
     RECT  0.084 24.432 0.137 24.456 ;
     RECT  0.06 24.456 0.137 24.528 ;
     RECT  0.084 24.528 0.137 24.552 ;
     RECT  0.06 24.552 0.137 24.624 ;
     RECT  0.084 24.624 0.137 24.648 ;
     RECT  0.06 24.648 0.137 24.72 ;
     RECT  0.084 24.72 0.137 24.744 ;
     RECT  0.06 24.744 0.137 24.816 ;
     RECT  0.084 24.816 0.137 24.84 ;
     RECT  0.06 24.84 0.137 24.912 ;
     RECT  0.084 24.912 0.137 24.936 ;
     RECT  0.06 24.936 0.137 25.008 ;
     RECT  0.084 25.008 0.137 25.032 ;
     RECT  0.06 25.032 0.137 25.104 ;
     RECT  0.084 25.104 0.137 25.128 ;
     RECT  0.06 25.128 0.137 25.2 ;
     RECT  0.084 25.2 0.137 25.224 ;
     RECT  0.06 25.224 0.137 25.296 ;
     RECT  0.084 25.296 0.137 25.32 ;
     RECT  0.06 25.32 0.137 25.392 ;
     RECT  0.084 25.392 0.137 25.416 ;
     RECT  0.06 25.416 0.137 25.488 ;
     RECT  0.084 25.488 0.137 25.512 ;
     RECT  0.06 25.512 0.137 25.584 ;
     RECT  0.084 25.584 0.137 25.608 ;
     RECT  0.06 25.608 0.137 25.68 ;
     RECT  0.084 25.68 0.137 25.704 ;
     RECT  0.06 25.704 0.137 25.776 ;
     RECT  0.084 25.776 0.137 25.8 ;
     RECT  0.06 25.8 0.137 25.872 ;
     RECT  0.084 25.872 0.137 25.896 ;
     RECT  0.06 25.896 0.137 25.968 ;
     RECT  0.084 25.968 0.137 25.992 ;
     RECT  0.06 25.992 0.137 26.064 ;
     RECT  0.084 26.064 0.137 26.088 ;
     RECT  0.06 26.088 0.137 26.16 ;
     RECT  0.084 26.16 0.137 26.184 ;
     RECT  0.06 26.184 0.137 26.256 ;
     RECT  0.084 26.256 0.137 26.28 ;
     RECT  0.06 26.28 0.137 26.352 ;
     RECT  0.084 26.352 0.137 26.376 ;
     RECT  0.06 26.376 0.137 26.448 ;
     RECT  0.084 26.448 0.137 26.472 ;
     RECT  0.06 26.472 0.137 26.544 ;
     RECT  0.084 26.544 0.137 26.568 ;
     RECT  0.06 26.568 0.137 26.64 ;
     RECT  0.084 26.64 0.137 26.664 ;
     RECT  0.06 26.664 0.137 26.736 ;
     RECT  0.084 26.736 0.137 26.76 ;
     RECT  0.06 26.76 0.137 26.832 ;
     RECT  0.084 26.832 0.137 26.856 ;
     RECT  0.06 26.856 0.137 26.928 ;
     RECT  0.084 26.928 0.137 26.952 ;
     RECT  0.06 26.952 0.137 27.024 ;
     RECT  0.084 27.024 0.137 27.048 ;
     RECT  0.06 27.048 0.137 27.12 ;
     RECT  0.084 27.12 0.137 27.144 ;
     RECT  0.06 27.144 0.137 27.216 ;
     RECT  0.084 27.216 0.137 27.24 ;
     RECT  0.06 27.24 0.137 27.312 ;
     RECT  0.084 27.312 0.137 27.336 ;
     RECT  0.06 27.336 0.137 27.408 ;
     RECT  0.084 27.408 0.137 27.432 ;
     RECT  0.06 27.432 0.137 27.504 ;
     RECT  0.084 27.504 0.137 27.528 ;
     RECT  0.06 27.528 0.137 27.6 ;
     RECT  0.084 27.6 0.137 27.624 ;
     RECT  0.06 27.624 0.137 27.696 ;
     RECT  0.084 27.696 0.137 27.72 ;
     RECT  0.06 27.72 0.137 27.792 ;
     RECT  0.084 27.792 0.137 27.816 ;
     RECT  0.06 27.816 0.137 27.888 ;
     RECT  0.084 27.888 0.137 27.912 ;
     RECT  0.06 27.912 0.137 27.984 ;
     RECT  0.084 27.984 0.137 28.008 ;
     RECT  0.06 28.008 0.137 28.08 ;
     RECT  0.084 28.08 0.137 28.104 ;
     RECT  0.06 28.104 0.137 28.176 ;
     RECT  0.084 28.176 0.137 28.2 ;
     RECT  0.06 28.2 0.137 28.272 ;
     RECT  0.084 28.272 0.137 28.296 ;
     RECT  0.06 28.296 0.137 28.368 ;
     RECT  0.084 28.368 0.137 28.392 ;
     RECT  0.06 28.392 0.137 28.464 ;
     RECT  0.084 28.464 0.137 28.488 ;
     RECT  0.06 28.488 0.137 28.56 ;
     RECT  0.084 28.56 0.137 28.584 ;
     RECT  0.06 28.584 0.137 28.656 ;
     RECT  0.084 28.656 0.137 28.68 ;
     RECT  0.06 28.68 0.137 28.752 ;
     RECT  0.084 28.752 0.137 28.776 ;
     RECT  0.06 28.776 0.137 28.848 ;
     RECT  0.084 28.848 0.137 28.872 ;
     RECT  0.06 28.872 0.137 28.944 ;
     RECT  0.084 28.944 0.137 28.968 ;
     RECT  0.06 28.968 0.137 29.04 ;
     RECT  0.084 29.04 0.137 29.064 ;
     RECT  0.06 29.064 0.137 29.136 ;
     RECT  0.084 29.136 0.137 29.16 ;
     RECT  0.06 29.16 0.137 29.232 ;
     RECT  0.084 29.232 0.137 29.256 ;
     RECT  0.06 29.256 0.137 29.328 ;
     RECT  0.084 29.328 0.137 29.352 ;
     RECT  0.06 29.352 0.137 29.424 ;
     RECT  0.084 29.424 0.137 29.448 ;
     RECT  0.06 29.448 0.137 29.52 ;
     RECT  0.084 29.52 0.137 29.544 ;
     RECT  0.06 29.544 0.137 29.616 ;
     RECT  0.084 29.616 0.137 29.64 ;
     RECT  0.06 29.64 0.137 29.712 ;
     RECT  0.084 29.712 0.137 29.736 ;
     RECT  0.06 29.736 0.137 29.808 ;
     RECT  0.084 29.808 0.137 29.832 ;
     RECT  0.06 29.832 0.137 29.904 ;
     RECT  0.084 29.904 0.137 29.928 ;
     RECT  0.06 29.928 0.137 30 ;
     RECT  0.084 30 0.137 30.024 ;
     RECT  0.06 30.024 0.137 30.096 ;
     RECT  0.084 30.096 0.137 30.12 ;
     RECT  0.06 30.12 0.137 30.192 ;
     RECT  0.084 30.192 0.137 30.216 ;
     RECT  0.06 30.216 0.137 30.288 ;
     RECT  0.084 30.288 0.137 30.312 ;
     RECT  0.06 30.312 0.137 30.384 ;
     RECT  0.084 30.384 0.137 30.408 ;
     RECT  0.06 30.408 0.137 30.48 ;
     RECT  0.084 30.48 0.137 30.504 ;
     RECT  0.06 30.504 0.137 30.576 ;
     RECT  0.084 30.576 0.137 30.6 ;
     RECT  0.06 30.6 0.137 30.672 ;
     RECT  0.084 30.672 0.137 30.696 ;
     RECT  0.06 30.696 0.137 30.768 ;
     RECT  0.084 30.768 0.137 30.792 ;
     RECT  0.06 30.792 0.137 30.864 ;
     RECT  0.084 30.864 0.137 30.888 ;
     RECT  0.06 30.888 0.137 30.96 ;
     RECT  0.084 30.96 0.137 30.984 ;
     RECT  0.06 30.984 0.137 31.056 ;
     RECT  0.084 31.056 0.137 31.08 ;
     RECT  0.06 31.08 0.137 31.152 ;
     RECT  0.084 31.152 0.137 31.176 ;
     RECT  0.06 31.176 0.137 31.248 ;
     RECT  0.084 31.248 0.137 31.272 ;
     RECT  0.06 31.272 0.137 31.344 ;
     RECT  0.084 31.344 0.137 31.368 ;
     RECT  0.06 31.368 0.137 31.44 ;
     RECT  0.084 31.44 0.137 31.464 ;
     RECT  0.06 31.464 0.137 31.536 ;
     RECT  0.084 31.536 0.137 31.56 ;
     RECT  0.06 31.56 0.137 31.632 ;
     RECT  0.084 31.632 0.137 31.656 ;
     RECT  0.06 31.656 0.137 31.728 ;
     RECT  0.084 31.728 0.137 31.752 ;
     RECT  0.06 31.752 0.137 31.824 ;
     RECT  0.084 31.824 0.137 31.848 ;
     RECT  0.06 31.848 0.137 31.92 ;
     RECT  0.084 31.92 0.137 31.944 ;
     RECT  0.06 31.944 0.137 32.016 ;
     RECT  0.084 32.016 0.137 32.04 ;
     RECT  0.06 32.04 0.137 32.112 ;
     RECT  0.084 32.112 0.137 32.136 ;
     RECT  0.06 32.136 0.137 32.208 ;
     RECT  0.084 32.208 0.137 32.232 ;
     RECT  0.06 32.232 0.137 32.304 ;
     RECT  0.084 32.304 0.137 32.328 ;
     RECT  0.06 32.328 0.137 32.4 ;
     RECT  0.084 32.4 0.137 32.424 ;
     RECT  0.06 32.424 0.137 32.496 ;
     RECT  0.084 32.496 0.137 32.52 ;
     RECT  0.06 32.52 0.137 32.592 ;
     RECT  0.084 32.592 0.137 32.616 ;
     RECT  0.06 32.616 0.137 32.688 ;
     RECT  0.084 32.688 0.137 32.712 ;
     RECT  0.06 32.712 0.137 32.784 ;
     RECT  0.084 32.784 0.137 32.808 ;
     RECT  0.06 32.808 0.137 32.88 ;
     RECT  0.084 32.88 0.137 32.904 ;
     RECT  0.06 32.904 0.137 32.976 ;
     RECT  0.084 32.976 0.137 33 ;
     RECT  0.06 33 0.137 33.072 ;
     RECT  0.084 33.072 0.137 33.096 ;
     RECT  0.06 33.096 0.137 33.168 ;
     RECT  0.084 33.168 0.137 33.192 ;
     RECT  0.06 33.192 0.137 33.264 ;
     RECT  0.084 33.264 0.137 33.288 ;
     RECT  0.06 33.288 0.137 33.36 ;
     RECT  0.084 33.36 0.137 33.384 ;
     RECT  0.06 33.384 0.137 33.456 ;
     RECT  0.084 33.456 0.137 33.48 ;
     RECT  0.06 33.48 0.137 33.552 ;
     RECT  0.084 33.552 0.137 33.576 ;
     RECT  0.06 33.576 0.137 33.648 ;
     RECT  0.084 33.648 0.137 33.672 ;
     RECT  0.06 33.672 0.137 33.744 ;
     RECT  0.084 33.744 0.137 33.768 ;
     RECT  0.084 2.352 2.408 2.376 ;
     RECT  0.06 2.376 2.408 2.448 ;
     RECT  0.084 2.448 2.408 2.472 ;
     RECT  0.06 2.472 2.408 2.544 ;
     RECT  0.084 2.544 2.408 2.568 ;
     RECT  0.06 2.568 2.408 2.64 ;
     RECT  0.084 2.64 2.408 2.664 ;
     RECT  0.06 2.664 2.408 2.736 ;
     RECT  0.084 2.736 2.408 2.76 ;
     RECT  0.06 2.76 2.408 2.832 ;
     RECT  0.084 2.832 2.408 2.856 ;
     RECT  0.06 2.856 2.408 2.928 ;
     RECT  0.084 2.928 2.408 2.952 ;
     RECT  0.06 2.952 2.408 3.024 ;
     RECT  0.084 3.024 2.408 3.048 ;
     RECT  0.06 3.048 2.408 3.12 ;
     RECT  0.084 3.12 2.408 3.144 ;
     RECT  0.06 3.144 2.408 3.216 ;
     RECT  0.084 3.216 2.408 3.24 ;
     RECT  0.06 3.24 2.408 3.312 ;
     RECT  0.084 3.312 2.408 3.336 ;
     RECT  0.06 3.336 2.408 3.408 ;
     RECT  0.084 3.408 2.408 3.432 ;
     RECT  0.06 3.432 2.408 3.504 ;
     RECT  0.084 3.504 2.408 3.528 ;
     RECT  0.06 3.528 2.408 3.6 ;
     RECT  0.084 3.6 2.408 3.624 ;
     RECT  0.06 3.624 2.408 3.696 ;
     RECT  0.084 3.696 2.408 3.72 ;
     RECT  0.06 3.72 2.408 3.792 ;
     RECT  0.084 3.792 2.408 3.816 ;
     RECT  0.06 3.816 2.408 3.888 ;
     RECT  0.084 3.888 2.408 3.912 ;
     RECT  0.06 3.912 2.408 3.984 ;
     RECT  0.084 3.984 2.408 4.008 ;
     RECT  0.06 4.008 2.408 4.08 ;
     RECT  0.084 4.08 2.408 4.104 ;
     RECT  0.06 4.104 2.408 4.176 ;
     RECT  0.084 4.176 2.408 4.2 ;
     RECT  0.06 4.2 2.408 4.272 ;
     RECT  0.084 4.272 2.408 4.296 ;
     RECT  0.06 4.296 2.408 4.368 ;
     RECT  0.084 4.368 2.408 4.392 ;
     RECT  0.06 4.392 2.408 4.464 ;
     RECT  0.084 4.464 2.408 4.488 ;
     RECT  0.06 4.488 2.408 4.56 ;
     RECT  0.084 4.56 2.408 4.584 ;
     RECT  0.06 4.584 2.408 4.656 ;
     RECT  0.084 4.656 2.408 4.68 ;
     RECT  0.06 4.68 2.408 4.752 ;
     RECT  0.084 4.752 2.408 4.776 ;
     RECT  0.06 4.776 2.408 4.848 ;
     RECT  0.084 4.848 2.408 4.872 ;
     RECT  0.06 4.872 2.408 4.944 ;
     RECT  0.084 4.944 2.408 4.968 ;
     RECT  0.06 4.968 2.408 5.04 ;
     RECT  0.084 5.04 2.408 5.064 ;
     RECT  0.06 5.064 2.408 5.136 ;
     RECT  0.084 5.136 2.408 5.16 ;
     RECT  0.06 5.16 2.408 5.232 ;
     RECT  0.084 5.232 2.408 5.256 ;
     RECT  0.06 5.256 2.408 5.328 ;
     RECT  0.084 5.328 2.408 5.352 ;
     RECT  0.06 5.352 2.408 5.424 ;
     RECT  0.084 5.424 2.408 5.448 ;
     RECT  0.06 5.448 2.408 5.52 ;
     RECT  0.084 5.52 2.408 5.544 ;
     RECT  0.06 5.544 2.408 5.616 ;
     RECT  0.084 5.616 2.408 5.64 ;
     RECT  0.06 5.64 2.408 5.712 ;
     RECT  0.084 5.712 2.408 5.736 ;
     RECT  0.06 5.736 2.408 5.808 ;
     RECT  0.084 5.808 2.408 5.832 ;
     RECT  0.06 5.832 2.408 5.904 ;
     RECT  0.084 5.904 2.408 5.928 ;
     RECT  0.06 5.928 2.408 6 ;
     RECT  0.084 6 2.408 6.024 ;
     RECT  0.06 6.024 2.408 6.096 ;
     RECT  0.084 6.096 2.408 6.12 ;
     RECT  0.06 6.12 2.408 6.192 ;
     RECT  0.084 6.192 2.408 6.216 ;
     RECT  0.06 6.216 2.408 6.288 ;
     RECT  0.084 6.288 2.408 6.312 ;
     RECT  0.06 6.312 2.408 6.384 ;
     RECT  0.084 6.384 2.408 6.408 ;
     RECT  0.06 6.408 2.408 6.48 ;
     RECT  0.084 6.48 2.408 6.504 ;
     RECT  0.06 6.504 2.408 6.576 ;
     RECT  0.084 6.576 2.408 6.6 ;
     RECT  0.06 6.6 2.408 6.672 ;
     RECT  0.084 6.672 2.408 6.696 ;
     RECT  0.06 6.696 2.408 6.768 ;
     RECT  0.084 6.768 2.408 6.792 ;
     RECT  0.06 6.792 2.408 6.864 ;
     RECT  0.084 6.864 2.408 6.888 ;
     RECT  0.06 6.888 2.408 6.96 ;
     RECT  0.084 6.96 2.408 6.984 ;
     RECT  0.06 6.984 2.408 7.056 ;
     RECT  0.084 7.056 2.408 7.08 ;
     RECT  0.06 7.08 2.408 7.152 ;
     RECT  0.084 7.152 2.408 7.176 ;
     RECT  0.06 7.176 2.408 7.248 ;
     RECT  0.084 7.248 2.408 7.272 ;
     RECT  0.06 7.272 2.408 7.344 ;
     RECT  0.084 7.344 2.408 7.368 ;
     RECT  0.06 7.368 2.408 7.44 ;
     RECT  0.084 7.44 2.408 7.464 ;
     RECT  0.06 7.464 2.408 7.536 ;
     RECT  0.084 7.536 2.408 7.56 ;
     RECT  0.06 7.56 2.408 7.632 ;
     RECT  0.084 7.632 2.408 7.656 ;
     RECT  0.06 7.656 2.408 7.728 ;
     RECT  0.084 7.728 2.408 7.752 ;
     RECT  0.06 7.752 2.408 7.824 ;
     RECT  0.084 7.824 2.408 7.848 ;
     RECT  0.06 7.848 2.408 7.92 ;
     RECT  0.084 7.92 2.408 7.944 ;
     RECT  0.06 7.944 2.408 8.016 ;
     RECT  0.084 8.016 2.408 8.04 ;
     RECT  0.06 8.04 2.408 8.112 ;
     RECT  0.084 8.112 2.408 8.136 ;
     RECT  0.06 8.136 2.408 8.208 ;
     RECT  0.084 8.208 2.408 8.232 ;
     RECT  0.06 8.232 2.408 8.304 ;
     RECT  0.084 8.304 2.408 8.328 ;
     RECT  0.06 8.328 2.408 8.4 ;
     RECT  0.084 8.4 2.408 8.424 ;
     RECT  0.06 8.424 2.408 8.496 ;
     RECT  0.084 8.496 2.408 8.52 ;
     RECT  0.06 8.52 2.408 8.592 ;
     RECT  0.084 8.592 2.408 8.616 ;
     RECT  0.06 8.616 2.408 8.688 ;
     RECT  0.084 8.688 2.408 8.712 ;
     RECT  0.06 8.712 2.408 8.784 ;
     RECT  0.084 8.784 2.408 8.808 ;
     RECT  0.06 8.808 2.408 8.88 ;
     RECT  0.084 8.88 2.408 8.904 ;
     RECT  0.06 8.904 2.408 8.976 ;
     RECT  0.084 8.976 2.408 9 ;
     RECT  0.06 9 2.408 9.072 ;
     RECT  0.084 9.072 2.408 9.096 ;
     RECT  0.06 9.096 2.408 9.168 ;
     RECT  0.084 9.168 2.408 9.192 ;
     RECT  0.06 9.192 2.408 9.264 ;
     RECT  0.084 9.264 2.408 9.288 ;
     RECT  0.06 9.288 2.408 9.36 ;
     RECT  0.084 9.36 2.408 9.384 ;
     RECT  0.06 9.384 2.408 9.456 ;
     RECT  0.084 9.456 2.408 9.48 ;
     RECT  0.06 9.48 2.408 9.552 ;
     RECT  0.084 9.552 2.408 9.576 ;
     RECT  0.06 9.576 2.408 9.648 ;
     RECT  0.084 9.648 2.408 9.672 ;
     RECT  0.06 9.672 2.408 9.744 ;
     RECT  0.084 9.744 2.408 9.768 ;
     RECT  0.06 9.768 2.408 9.84 ;
     RECT  0.084 9.84 2.408 9.864 ;
     RECT  0.06 9.864 2.408 9.936 ;
     RECT  0.084 9.936 2.408 9.96 ;
     RECT  0.06 9.96 2.408 10.032 ;
     RECT  0.084 10.032 2.408 10.056 ;
     RECT  0.06 10.056 2.408 10.128 ;
     RECT  0.084 10.128 2.408 10.152 ;
     RECT  0.06 10.152 2.408 10.224 ;
     RECT  0.084 10.224 2.408 10.248 ;
     RECT  0.06 10.248 2.408 10.32 ;
     RECT  0.084 10.32 2.408 10.344 ;
     RECT  0.06 10.344 2.408 10.416 ;
     RECT  0.084 10.416 2.408 10.44 ;
     RECT  0.06 10.44 2.408 10.512 ;
     RECT  0.084 10.512 2.408 10.536 ;
     RECT  0.06 10.536 2.408 10.608 ;
     RECT  0.084 10.608 2.408 10.632 ;
     RECT  0.06 10.632 2.408 10.704 ;
     RECT  0.084 10.704 2.408 10.728 ;
     RECT  0.06 10.728 2.408 10.8 ;
     RECT  0.084 10.8 2.408 10.824 ;
     RECT  0.06 10.824 2.408 10.896 ;
     RECT  0.084 10.896 2.408 10.92 ;
     RECT  0.06 10.92 2.408 10.992 ;
     RECT  0.084 10.992 2.408 11.016 ;
     RECT  0.06 11.016 2.408 11.088 ;
     RECT  0.084 11.088 2.408 11.112 ;
     RECT  0.06 11.112 2.408 11.184 ;
     RECT  0.084 11.184 2.408 11.208 ;
     RECT  0.06 11.208 2.408 11.28 ;
     RECT  0.084 11.28 2.408 11.304 ;
     RECT  0.06 11.304 2.408 11.376 ;
     RECT  0.084 11.376 2.408 11.4 ;
     RECT  0.06 11.4 2.408 11.472 ;
     RECT  0.084 11.472 2.408 11.496 ;
     RECT  0.137 13.2 2.408 33.768 ;
     RECT  2.408 2.148 2.512 33.768 ;
     RECT  2.512 2.352 2.819 33.768 ;
     RECT  2.819 13.152 3.017 33.768 ;
     RECT  2.819 2.352 3.125 12.024 ;
     RECT  3.017 13.152 3.305 33.672 ;
     RECT  3.305 13.152 3.341 33.576 ;
     RECT  3.341 13.152 3.377 33.48 ;
     RECT  3.377 13.152 3.413 33.192 ;
     RECT  3.125 2.544 3.841 12.024 ;
     RECT  3.413 13.152 3.841 32.712 ;
     RECT  3.841 2.544 4.025 32.712 ;
     RECT  4.025 2.544 4.165 15.336 ;
     RECT  4.025 16.368 5.105 32.712 ;
     RECT  4.165 2.256 5.108 15.336 ;
     RECT  5.105 16.368 5.108 32.412 ;
     RECT  5.108 2.148 5.212 32.412 ;
     RECT  5.212 2.418 5.404 32.328 ;
     RECT  5.404 2.496 5.573 6.312 ;
     RECT  5.404 14.736 5.645 20.616 ;
     RECT  5.404 22.224 5.969 24.36 ;
     RECT  5.645 14.88 6.275 20.616 ;
     RECT  5.404 11.952 6.293 13.368 ;
     RECT  6.293 12.816 6.437 13.368 ;
     RECT  5.404 25.44 6.617 32.328 ;
     RECT  5.404 7.344 6.649 10.728 ;
     RECT  6.649 7.248 6.689 10.728 ;
     RECT  6.517 21.648 6.689 21.672 ;
     RECT  5.573 2.496 6.793 5.832 ;
     RECT  6.793 2.496 7.261 6.264 ;
     RECT  6.689 7.248 7.261 10.2 ;
     RECT  6.275 15.312 7.369 20.616 ;
     RECT  7.261 2.496 7.808 10.2 ;
     RECT  6.901 11.52 7.808 11.544 ;
     RECT  6.437 12.816 7.808 13.08 ;
     RECT  7.369 15.264 7.808 20.616 ;
     RECT  5.969 22.8 7.808 24.36 ;
     RECT  6.617 25.44 7.808 27.432 ;
     RECT  6.617 28.512 7.808 32.328 ;
     RECT  7.808 2.148 7.912 32.412 ;
     RECT  7.912 2.418 8.104 32.142 ;
     RECT  8.104 27.072 8.165 27.672 ;
     RECT  8.104 2.496 8.525 6.024 ;
     RECT  8.104 12.528 8.723 14.232 ;
     RECT  8.104 7.152 8.921 11.544 ;
     RECT  8.921 10.848 9.109 11.544 ;
     RECT  8.723 12.528 9.109 13.848 ;
     RECT  8.104 15.312 9.173 25.752 ;
     RECT  9.173 15.312 9.209 25.56 ;
     RECT  8.525 5.712 9.241 6.024 ;
     RECT  8.921 7.152 9.241 9.864 ;
     RECT  9.109 10.848 9.395 13.848 ;
     RECT  9.209 15.312 9.421 23.928 ;
     RECT  8.165 27.36 9.457 27.672 ;
     RECT  8.525 2.496 9.709 4.488 ;
     RECT  9.457 27.072 9.745 27.672 ;
     RECT  8.104 28.992 9.745 31.896 ;
     RECT  9.709 2.256 10.005 4.488 ;
     RECT  9.241 5.712 10.005 9.864 ;
     RECT  9.745 27.072 10.177 31.896 ;
     RECT  10.005 2.256 10.357 9.864 ;
     RECT  9.395 10.848 10.357 11.256 ;
     RECT  9.395 12.816 10.393 13.848 ;
     RECT  10.357 2.256 10.508 11.256 ;
     RECT  10.393 12.768 10.508 13.848 ;
     RECT  9.421 14.832 10.508 23.928 ;
     RECT  9.209 25.152 10.508 25.56 ;
     RECT  10.177 26.784 10.508 31.896 ;
     RECT  10.508 2.148 10.612 32.412 ;
     RECT  10.612 2.256 10.804 32.142 ;
     RECT  10.804 2.256 10.829 11.256 ;
     RECT  10.829 2.256 11.009 10.728 ;
     RECT  11.009 2.496 11.075 10.728 ;
     RECT  11.075 2.496 11.117 10.44 ;
     RECT  11.117 2.592 11.153 10.44 ;
     RECT  10.804 15.408 11.411 31.8 ;
     RECT  11.411 18.432 11.657 31.8 ;
     RECT  11.411 15.408 11.833 17.304 ;
     RECT  10.804 12.768 12.049 14.232 ;
     RECT  12.049 12.528 12.265 14.232 ;
     RECT  12.373 11.424 12.445 11.448 ;
     RECT  12.445 11.232 12.589 11.448 ;
     RECT  12.265 12.48 12.589 14.232 ;
     RECT  11.833 15.312 12.589 17.304 ;
     RECT  12.589 11.232 12.625 17.304 ;
     RECT  12.625 11.136 12.949 17.304 ;
     RECT  11.657 18.432 12.949 23.928 ;
     RECT  11.153 2.592 13.208 10.152 ;
     RECT  12.949 11.136 13.208 23.928 ;
     RECT  11.657 24.912 13.208 31.8 ;
     RECT  13.208 2.148 13.312 32.412 ;
     RECT  13.312 2.418 13.504 32.142 ;
     RECT  13.504 11.136 13.565 29.256 ;
     RECT  13.504 2.592 13.637 10.152 ;
     RECT  13.093 0.096 13.667 0.12 ;
     RECT  13.637 2.736 13.853 10.152 ;
     RECT  13.565 27.168 13.889 29.256 ;
     RECT  13.853 2.736 14.033 10.104 ;
     RECT  13.565 11.136 14.291 26.136 ;
     RECT  14.291 11.136 14.393 23.976 ;
     RECT  13.504 30.384 14.429 31.8 ;
     RECT  14.291 25.2 14.537 26.136 ;
     RECT  14.537 25.44 14.569 26.136 ;
     RECT  14.429 30.384 14.573 31.704 ;
     RECT  14.033 2.736 14.821 9.864 ;
     RECT  14.821 2.592 14.857 9.864 ;
     RECT  14.393 11.136 14.861 23.88 ;
     RECT  14.861 11.136 14.933 22.248 ;
     RECT  14.933 11.136 14.965 17.928 ;
     RECT  13.889 27.888 15.001 29.256 ;
     RECT  14.857 2.352 15.433 9.864 ;
     RECT  14.569 25.44 15.433 26.328 ;
     RECT  15.001 27.36 15.433 29.256 ;
     RECT  14.573 30.384 15.577 31.416 ;
     RECT  14.933 19.2 15.829 22.248 ;
     RECT  15.433 2.304 15.865 9.864 ;
     RECT  14.965 10.896 15.865 17.928 ;
     RECT  15.865 2.304 15.908 17.928 ;
     RECT  15.829 19.2 15.908 22.296 ;
     RECT  14.861 23.376 15.908 23.88 ;
     RECT  15.433 25.44 15.908 29.256 ;
     RECT  15.577 30.384 15.908 31.8 ;
     RECT  15.908 2.148 16.012 32.412 ;
     RECT  16.012 2.304 16.204 32.142 ;
     RECT  16.204 26.64 16.625 27.384 ;
     RECT  16.625 26.688 17.093 27.384 ;
     RECT  16.204 2.304 17.161 24.264 ;
     RECT  17.161 2.208 17.309 24.264 ;
     RECT  17.309 2.208 17.345 24.12 ;
     RECT  16.204 30.576 17.453 31.944 ;
     RECT  17.377 0.816 17.485 0.84 ;
     RECT  17.345 2.208 17.485 13.608 ;
     RECT  16.204 29.232 17.557 29.256 ;
     RECT  17.093 26.688 18.565 27.336 ;
     RECT  17.485 0.816 18.608 13.608 ;
     RECT  17.345 14.832 18.608 24.12 ;
     RECT  18.565 26.688 18.608 27.72 ;
     RECT  17.557 28.944 18.608 29.256 ;
     RECT  17.453 30.72 18.608 31.944 ;
     RECT  18.608 0.816 18.712 32.412 ;
     RECT  18.712 0.816 18.904 32.142 ;
     RECT  18.904 5.808 19.073 13.128 ;
     RECT  18.904 0.816 19.897 4.776 ;
     RECT  18.904 14.352 19.897 18.888 ;
     RECT  19.897 0.72 19.933 4.776 ;
     RECT  19.073 5.808 19.933 7.848 ;
     RECT  19.073 8.976 19.933 13.128 ;
     RECT  19.897 14.16 19.933 18.888 ;
     RECT  18.904 26.352 19.933 32.136 ;
     RECT  19.933 0.72 20.185 7.848 ;
     RECT  19.933 8.976 20.185 18.888 ;
     RECT  18.904 19.92 20.185 24.168 ;
     RECT  20.185 0.72 20.401 18.888 ;
     RECT  20.185 19.92 20.401 24.552 ;
     RECT  19.933 26.16 20.473 32.136 ;
     RECT  20.401 0.72 21.516 0.744 ;
     RECT  20.401 0.744 21.564 0.816 ;
     RECT  20.401 0.816 21.516 0.84 ;
     RECT  20.401 0.84 21.564 0.912 ;
     RECT  20.401 0.912 21.516 0.936 ;
     RECT  20.401 0.936 21.564 1.008 ;
     RECT  20.401 1.008 21.516 1.032 ;
     RECT  20.401 1.032 21.564 1.104 ;
     RECT  20.401 1.104 21.516 1.128 ;
     RECT  20.401 1.128 21.564 1.2 ;
     RECT  20.401 1.2 21.516 1.224 ;
     RECT  20.401 1.224 21.564 1.296 ;
     RECT  20.401 1.296 21.516 1.32 ;
     RECT  20.401 1.32 21.564 1.392 ;
     RECT  20.401 1.392 21.516 1.416 ;
     RECT  20.401 1.416 21.564 1.488 ;
     RECT  20.401 1.488 21.516 1.512 ;
     RECT  20.401 1.512 21.564 1.584 ;
     RECT  20.401 1.584 21.516 1.608 ;
     RECT  20.401 1.608 21.564 1.68 ;
     RECT  20.401 1.68 21.516 1.704 ;
     RECT  20.401 1.704 21.564 1.776 ;
     RECT  20.401 1.776 21.516 1.8 ;
     RECT  20.401 1.8 21.564 1.872 ;
     RECT  20.401 1.872 21.516 1.896 ;
     RECT  20.401 1.896 21.564 1.968 ;
     RECT  20.401 1.968 21.516 1.992 ;
     RECT  20.401 1.992 21.564 2.064 ;
     RECT  20.401 2.064 21.516 2.088 ;
     RECT  20.401 2.088 21.564 2.16 ;
     RECT  20.401 2.16 21.516 2.184 ;
     RECT  20.401 2.184 21.564 2.256 ;
     RECT  20.401 2.256 21.516 2.28 ;
     RECT  20.401 2.28 21.564 2.352 ;
     RECT  20.401 2.352 21.516 2.376 ;
     RECT  20.401 2.376 21.564 2.448 ;
     RECT  20.401 2.448 21.516 2.472 ;
     RECT  20.401 2.472 21.564 2.544 ;
     RECT  20.401 2.544 21.516 2.568 ;
     RECT  20.401 2.568 21.564 2.64 ;
     RECT  20.401 2.64 21.516 2.664 ;
     RECT  20.401 2.664 21.564 2.736 ;
     RECT  20.401 2.736 21.516 2.76 ;
     RECT  20.401 2.76 21.564 2.832 ;
     RECT  20.401 2.832 21.516 2.856 ;
     RECT  20.401 2.856 21.564 2.928 ;
     RECT  20.401 2.928 21.516 2.952 ;
     RECT  20.401 2.952 21.564 3.024 ;
     RECT  20.401 3.024 21.516 3.048 ;
     RECT  20.401 3.048 21.564 3.12 ;
     RECT  20.401 3.12 21.516 3.144 ;
     RECT  20.401 3.144 21.564 3.216 ;
     RECT  20.401 3.216 21.516 3.24 ;
     RECT  20.401 3.24 21.564 3.312 ;
     RECT  20.401 3.312 21.516 3.336 ;
     RECT  20.401 3.336 21.564 3.408 ;
     RECT  20.401 3.408 21.516 3.432 ;
     RECT  20.401 3.432 21.564 3.504 ;
     RECT  20.401 3.504 21.516 3.528 ;
     RECT  20.401 3.528 21.564 3.6 ;
     RECT  20.401 3.6 21.516 3.624 ;
     RECT  20.401 3.624 21.564 3.696 ;
     RECT  20.401 3.696 21.516 3.72 ;
     RECT  20.401 3.72 21.564 3.792 ;
     RECT  20.401 3.792 21.516 3.816 ;
     RECT  20.401 3.816 21.564 3.888 ;
     RECT  20.401 3.888 21.516 3.912 ;
     RECT  20.401 3.912 21.564 3.984 ;
     RECT  20.401 3.984 21.516 4.008 ;
     RECT  20.401 4.008 21.564 4.08 ;
     RECT  20.401 4.08 21.516 4.104 ;
     RECT  20.401 4.104 21.564 4.176 ;
     RECT  20.401 4.176 21.516 4.2 ;
     RECT  20.401 4.2 21.564 4.272 ;
     RECT  20.401 4.272 21.516 4.296 ;
     RECT  20.401 4.296 21.564 4.368 ;
     RECT  20.401 4.368 21.516 4.392 ;
     RECT  20.401 4.392 21.564 4.464 ;
     RECT  20.401 4.464 21.516 4.488 ;
     RECT  20.401 4.488 21.564 4.56 ;
     RECT  20.401 4.56 21.516 4.584 ;
     RECT  20.401 4.584 21.564 4.656 ;
     RECT  20.401 4.656 21.516 4.68 ;
     RECT  20.401 4.68 21.564 4.752 ;
     RECT  20.401 4.752 21.516 4.776 ;
     RECT  20.401 4.776 21.564 4.848 ;
     RECT  20.401 4.848 21.516 4.872 ;
     RECT  20.401 4.872 21.564 4.944 ;
     RECT  20.401 4.944 21.516 4.968 ;
     RECT  20.401 4.968 21.564 5.04 ;
     RECT  20.401 5.04 21.516 5.064 ;
     RECT  20.401 5.064 21.564 5.136 ;
     RECT  20.401 5.136 21.516 5.16 ;
     RECT  20.401 5.16 21.564 5.232 ;
     RECT  20.401 5.232 21.516 5.256 ;
     RECT  20.401 5.256 21.564 5.328 ;
     RECT  20.401 5.328 21.516 5.352 ;
     RECT  20.401 5.352 21.564 5.424 ;
     RECT  20.401 5.424 21.516 5.448 ;
     RECT  20.401 5.448 21.564 5.52 ;
     RECT  20.401 5.52 21.516 5.544 ;
     RECT  20.401 5.544 21.564 5.616 ;
     RECT  20.401 5.616 21.516 5.64 ;
     RECT  20.401 5.64 21.564 5.712 ;
     RECT  20.401 5.712 21.516 5.736 ;
     RECT  20.401 5.736 21.564 5.808 ;
     RECT  20.401 5.808 21.516 5.832 ;
     RECT  20.401 5.832 21.564 5.904 ;
     RECT  20.401 5.904 21.516 5.928 ;
     RECT  20.401 5.928 21.564 6 ;
     RECT  20.401 6 21.516 6.024 ;
     RECT  20.401 6.024 21.564 6.096 ;
     RECT  20.401 6.096 21.516 6.12 ;
     RECT  20.401 6.12 21.564 6.192 ;
     RECT  20.401 6.192 21.516 6.216 ;
     RECT  20.401 6.216 21.564 6.288 ;
     RECT  20.401 6.288 21.516 6.312 ;
     RECT  20.401 6.312 21.564 6.384 ;
     RECT  20.401 6.384 21.516 6.408 ;
     RECT  20.401 6.408 21.564 6.48 ;
     RECT  20.401 6.48 21.516 6.504 ;
     RECT  20.401 6.504 21.564 6.576 ;
     RECT  20.401 6.576 21.516 6.6 ;
     RECT  20.401 6.6 21.564 6.672 ;
     RECT  20.401 6.672 21.516 6.696 ;
     RECT  20.401 6.696 21.564 6.768 ;
     RECT  20.401 6.768 21.516 6.792 ;
     RECT  20.401 6.792 21.564 6.864 ;
     RECT  20.401 6.864 21.516 6.888 ;
     RECT  20.401 6.888 21.564 6.96 ;
     RECT  20.401 6.96 21.516 6.984 ;
     RECT  20.401 6.984 21.564 7.056 ;
     RECT  20.401 7.056 21.516 7.08 ;
     RECT  20.401 7.08 21.564 7.152 ;
     RECT  20.401 7.152 21.516 7.176 ;
     RECT  20.401 7.176 21.564 7.248 ;
     RECT  20.401 7.248 21.516 7.272 ;
     RECT  20.401 7.272 21.564 7.344 ;
     RECT  20.401 7.344 21.516 7.368 ;
     RECT  20.401 7.368 21.564 7.44 ;
     RECT  20.401 7.44 21.516 7.464 ;
     RECT  20.401 7.464 21.564 7.536 ;
     RECT  20.401 7.536 21.516 7.56 ;
     RECT  20.401 7.56 21.564 7.632 ;
     RECT  20.401 7.632 21.516 7.656 ;
     RECT  20.401 7.656 21.564 7.728 ;
     RECT  20.401 7.728 21.516 7.752 ;
     RECT  20.401 7.752 21.564 7.824 ;
     RECT  20.401 7.824 21.516 7.848 ;
     RECT  20.401 7.848 21.564 7.92 ;
     RECT  20.401 7.92 21.516 7.944 ;
     RECT  20.401 7.944 21.564 8.016 ;
     RECT  20.401 8.016 21.516 8.04 ;
     RECT  20.401 8.04 21.564 8.112 ;
     RECT  20.401 8.112 21.516 8.136 ;
     RECT  20.401 8.136 21.564 8.208 ;
     RECT  20.401 8.208 21.516 8.232 ;
     RECT  20.401 8.232 21.564 8.304 ;
     RECT  20.401 8.304 21.516 8.328 ;
     RECT  20.401 8.328 21.564 8.4 ;
     RECT  20.401 8.4 21.516 8.424 ;
     RECT  20.401 8.424 21.564 8.496 ;
     RECT  20.401 8.496 21.516 8.52 ;
     RECT  20.401 8.52 21.564 8.592 ;
     RECT  20.401 8.592 21.516 8.616 ;
     RECT  20.401 8.616 21.564 8.688 ;
     RECT  20.401 8.688 21.516 8.712 ;
     RECT  20.401 8.712 21.564 8.784 ;
     RECT  20.401 8.784 21.516 8.808 ;
     RECT  20.401 8.808 21.564 8.88 ;
     RECT  20.401 8.88 21.516 8.904 ;
     RECT  20.401 8.904 21.564 8.976 ;
     RECT  20.401 8.976 21.516 9 ;
     RECT  20.401 9 21.564 9.072 ;
     RECT  20.401 9.072 21.516 9.096 ;
     RECT  20.401 9.096 21.564 9.168 ;
     RECT  20.401 9.168 21.516 9.192 ;
     RECT  20.401 9.192 21.564 9.264 ;
     RECT  20.401 9.264 21.516 9.288 ;
     RECT  20.401 9.288 21.564 9.36 ;
     RECT  20.401 9.36 21.516 9.384 ;
     RECT  20.401 9.384 21.564 9.456 ;
     RECT  20.401 9.456 21.516 9.48 ;
     RECT  20.401 9.48 21.564 9.552 ;
     RECT  20.401 9.552 21.516 9.576 ;
     RECT  20.401 9.576 21.564 9.648 ;
     RECT  20.401 9.648 21.516 9.672 ;
     RECT  20.401 9.672 21.564 9.744 ;
     RECT  20.401 9.744 21.516 9.768 ;
     RECT  20.401 9.768 21.564 9.84 ;
     RECT  20.401 9.84 21.516 9.864 ;
     RECT  20.401 9.864 21.564 9.936 ;
     RECT  20.401 9.936 21.516 9.96 ;
     RECT  20.401 9.96 21.564 10.032 ;
     RECT  20.401 10.032 21.516 10.056 ;
     RECT  20.401 10.056 21.564 10.128 ;
     RECT  20.401 10.128 21.516 10.152 ;
     RECT  20.401 10.152 21.564 10.224 ;
     RECT  20.401 10.224 21.516 10.248 ;
     RECT  20.401 10.248 21.564 10.32 ;
     RECT  20.401 10.32 21.516 10.344 ;
     RECT  20.401 10.344 21.564 10.416 ;
     RECT  20.401 10.416 21.516 10.44 ;
     RECT  20.401 10.44 21.564 10.512 ;
     RECT  20.401 10.512 21.516 10.536 ;
     RECT  20.401 10.536 21.564 10.608 ;
     RECT  20.401 10.608 21.516 10.632 ;
     RECT  20.401 10.632 21.564 10.704 ;
     RECT  20.401 10.704 21.516 10.728 ;
     RECT  20.401 10.728 21.564 10.8 ;
     RECT  20.401 10.8 21.516 10.824 ;
     RECT  20.401 10.824 21.564 10.896 ;
     RECT  20.401 10.896 21.516 10.92 ;
     RECT  20.401 10.92 21.564 10.992 ;
     RECT  20.401 10.992 21.516 11.016 ;
     RECT  20.401 11.016 21.564 11.088 ;
     RECT  20.401 11.088 21.516 11.112 ;
     RECT  20.401 11.112 21.564 11.184 ;
     RECT  20.401 11.184 21.516 11.208 ;
     RECT  20.401 11.208 21.564 11.28 ;
     RECT  20.401 11.28 21.516 11.304 ;
     RECT  20.401 11.304 21.564 11.376 ;
     RECT  20.401 11.376 21.516 11.4 ;
     RECT  20.401 11.4 21.564 11.472 ;
     RECT  20.401 11.472 21.516 11.496 ;
     RECT  20.401 11.496 21.564 11.568 ;
     RECT  20.401 11.568 21.516 11.592 ;
     RECT  20.401 11.592 21.564 11.664 ;
     RECT  20.401 11.664 21.516 11.688 ;
     RECT  20.401 11.688 21.564 11.76 ;
     RECT  20.401 11.76 21.516 11.784 ;
     RECT  20.401 11.784 21.564 11.856 ;
     RECT  20.401 11.856 21.516 11.88 ;
     RECT  20.401 11.88 21.564 11.952 ;
     RECT  20.401 11.952 21.516 11.976 ;
     RECT  20.401 11.976 21.564 12.048 ;
     RECT  20.401 12.048 21.516 12.072 ;
     RECT  20.401 12.072 21.564 12.144 ;
     RECT  20.401 12.144 21.516 12.168 ;
     RECT  20.401 12.168 21.564 12.24 ;
     RECT  20.401 12.24 21.516 12.264 ;
     RECT  20.401 12.264 21.564 12.336 ;
     RECT  20.401 12.336 21.516 12.36 ;
     RECT  20.401 12.36 21.564 12.432 ;
     RECT  20.401 12.432 21.516 12.456 ;
     RECT  20.401 12.456 21.564 12.528 ;
     RECT  20.401 12.528 21.516 12.552 ;
     RECT  20.401 12.552 21.564 12.624 ;
     RECT  20.401 12.624 21.516 12.648 ;
     RECT  20.401 12.648 21.564 12.72 ;
     RECT  20.401 12.72 21.516 12.744 ;
     RECT  20.401 12.744 21.564 12.816 ;
     RECT  20.401 12.816 21.516 12.84 ;
     RECT  20.401 12.84 21.564 12.912 ;
     RECT  20.401 12.912 21.516 12.936 ;
     RECT  20.401 12.936 21.564 13.008 ;
     RECT  20.401 13.008 21.516 13.032 ;
     RECT  20.401 13.032 21.564 13.104 ;
     RECT  20.401 13.104 21.516 13.128 ;
     RECT  20.401 13.128 21.564 13.2 ;
     RECT  20.401 13.2 21.516 13.224 ;
     RECT  20.401 13.224 21.564 13.296 ;
     RECT  20.401 13.296 21.516 13.32 ;
     RECT  20.401 13.32 21.564 13.392 ;
     RECT  20.401 13.392 21.516 13.416 ;
     RECT  20.401 13.416 21.564 13.488 ;
     RECT  20.401 13.488 21.516 13.512 ;
     RECT  20.401 13.512 21.564 13.584 ;
     RECT  20.401 13.584 21.516 13.608 ;
     RECT  20.401 13.608 21.564 13.68 ;
     RECT  20.401 13.68 21.516 13.704 ;
     RECT  20.401 13.704 21.564 13.776 ;
     RECT  20.401 13.776 21.516 13.8 ;
     RECT  20.401 13.8 21.564 13.872 ;
     RECT  20.401 13.872 21.516 13.896 ;
     RECT  20.401 13.896 21.564 13.968 ;
     RECT  20.401 13.968 21.516 13.992 ;
     RECT  20.401 13.992 21.564 14.064 ;
     RECT  20.401 14.064 21.516 14.088 ;
     RECT  20.401 14.088 21.564 14.16 ;
     RECT  20.401 14.16 21.516 14.184 ;
     RECT  20.401 14.184 21.564 14.256 ;
     RECT  20.401 14.256 21.516 14.28 ;
     RECT  20.401 14.28 21.564 14.352 ;
     RECT  20.401 14.352 21.516 14.376 ;
     RECT  20.401 14.376 21.564 14.448 ;
     RECT  20.401 14.448 21.516 14.472 ;
     RECT  20.401 14.472 21.564 14.544 ;
     RECT  20.401 14.544 21.516 14.568 ;
     RECT  20.401 14.568 21.564 14.64 ;
     RECT  20.401 14.64 21.516 14.664 ;
     RECT  20.401 14.664 21.564 14.736 ;
     RECT  20.401 14.736 21.516 14.76 ;
     RECT  20.401 14.76 21.564 14.832 ;
     RECT  20.401 14.832 21.516 14.856 ;
     RECT  20.401 14.856 21.564 14.928 ;
     RECT  20.401 14.928 21.516 14.952 ;
     RECT  20.401 14.952 21.564 15.024 ;
     RECT  20.401 15.024 21.516 15.048 ;
     RECT  20.401 15.048 21.564 15.12 ;
     RECT  20.401 15.12 21.516 15.144 ;
     RECT  20.401 15.144 21.564 15.216 ;
     RECT  20.401 15.216 21.516 15.24 ;
     RECT  20.401 15.24 21.564 15.312 ;
     RECT  20.401 15.312 21.516 15.336 ;
     RECT  20.401 15.336 21.564 15.408 ;
     RECT  20.401 15.408 21.516 15.432 ;
     RECT  20.401 15.432 21.564 15.504 ;
     RECT  20.401 15.504 21.516 15.528 ;
     RECT  20.401 15.528 21.564 15.6 ;
     RECT  20.401 15.6 21.516 15.624 ;
     RECT  20.401 15.624 21.564 15.696 ;
     RECT  20.401 15.696 21.516 15.72 ;
     RECT  20.401 15.72 21.564 15.792 ;
     RECT  20.401 15.792 21.516 15.816 ;
     RECT  20.401 15.816 21.564 15.888 ;
     RECT  20.401 15.888 21.516 15.912 ;
     RECT  20.401 15.912 21.564 15.984 ;
     RECT  20.401 15.984 21.516 16.008 ;
     RECT  20.401 16.008 21.564 16.08 ;
     RECT  20.401 16.08 21.516 16.104 ;
     RECT  20.401 16.104 21.564 16.176 ;
     RECT  20.401 16.176 21.516 16.2 ;
     RECT  20.401 16.2 21.564 16.272 ;
     RECT  20.401 16.272 21.516 16.296 ;
     RECT  20.401 16.296 21.564 16.368 ;
     RECT  20.401 16.368 21.516 16.392 ;
     RECT  20.401 16.392 21.564 16.464 ;
     RECT  20.401 16.464 21.516 16.488 ;
     RECT  20.401 16.488 21.564 16.56 ;
     RECT  20.401 16.56 21.516 16.584 ;
     RECT  20.401 16.584 21.564 16.656 ;
     RECT  20.401 16.656 21.516 16.68 ;
     RECT  20.401 16.68 21.564 16.752 ;
     RECT  20.401 16.752 21.516 16.776 ;
     RECT  20.401 16.776 21.564 16.848 ;
     RECT  20.401 16.848 21.516 16.872 ;
     RECT  20.401 16.872 21.564 16.944 ;
     RECT  20.401 16.944 21.516 16.968 ;
     RECT  20.401 16.968 21.564 17.04 ;
     RECT  20.401 17.04 21.516 17.064 ;
     RECT  20.401 17.064 21.564 17.136 ;
     RECT  20.401 17.136 21.516 17.16 ;
     RECT  20.401 17.16 21.564 17.232 ;
     RECT  20.401 17.232 21.516 17.256 ;
     RECT  20.401 17.256 21.564 17.328 ;
     RECT  20.401 17.328 21.516 17.352 ;
     RECT  20.401 17.352 21.564 17.424 ;
     RECT  20.401 17.424 21.516 17.448 ;
     RECT  20.401 17.448 21.564 17.52 ;
     RECT  20.401 17.52 21.516 17.544 ;
     RECT  20.401 17.544 21.564 17.616 ;
     RECT  20.401 17.616 21.516 17.64 ;
     RECT  20.401 17.64 21.564 17.712 ;
     RECT  20.401 17.712 21.516 17.736 ;
     RECT  20.401 17.736 21.564 17.808 ;
     RECT  20.401 17.808 21.516 17.832 ;
     RECT  20.401 17.832 21.564 17.904 ;
     RECT  20.401 17.904 21.516 17.928 ;
     RECT  20.401 17.928 21.564 18 ;
     RECT  20.401 18 21.516 18.024 ;
     RECT  20.401 18.024 21.564 18.096 ;
     RECT  20.401 18.096 21.516 18.12 ;
     RECT  20.401 18.12 21.564 18.192 ;
     RECT  20.401 18.192 21.516 18.216 ;
     RECT  20.401 18.216 21.564 18.288 ;
     RECT  20.401 18.288 21.516 18.312 ;
     RECT  20.401 18.312 21.564 18.384 ;
     RECT  20.401 18.384 21.516 18.408 ;
     RECT  20.401 18.408 21.564 18.48 ;
     RECT  20.401 18.48 21.516 18.504 ;
     RECT  20.401 18.504 21.564 18.576 ;
     RECT  20.401 18.576 21.516 18.6 ;
     RECT  20.401 18.6 21.564 18.672 ;
     RECT  20.401 18.672 21.516 18.696 ;
     RECT  20.401 18.696 21.564 18.768 ;
     RECT  20.401 18.768 21.516 18.792 ;
     RECT  20.401 18.792 21.564 18.864 ;
     RECT  20.401 18.864 21.516 18.888 ;
     RECT  20.401 18.888 21.564 18.96 ;
     RECT  20.401 18.96 21.516 18.984 ;
     RECT  20.401 18.984 21.564 19.056 ;
     RECT  20.401 19.056 21.516 19.08 ;
     RECT  20.401 19.08 21.564 19.92 ;
     RECT  20.401 19.92 21.516 19.944 ;
     RECT  20.401 19.944 21.564 20.016 ;
     RECT  20.401 20.016 21.516 20.04 ;
     RECT  20.401 20.04 21.564 20.112 ;
     RECT  20.401 20.112 21.516 20.136 ;
     RECT  20.401 20.136 21.564 20.208 ;
     RECT  20.401 20.208 21.516 20.232 ;
     RECT  20.401 20.232 21.564 20.304 ;
     RECT  20.401 20.304 21.516 20.328 ;
     RECT  20.401 20.328 21.564 20.4 ;
     RECT  20.401 20.4 21.516 20.424 ;
     RECT  20.401 20.424 21.564 20.496 ;
     RECT  20.401 20.496 21.516 20.52 ;
     RECT  20.401 20.52 21.564 20.592 ;
     RECT  20.401 20.592 21.516 20.616 ;
     RECT  20.401 20.616 21.564 20.688 ;
     RECT  20.401 20.688 21.516 20.712 ;
     RECT  20.401 20.712 21.564 20.784 ;
     RECT  20.401 20.784 21.516 20.808 ;
     RECT  20.401 20.808 21.564 20.88 ;
     RECT  20.401 20.88 21.516 20.904 ;
     RECT  20.401 20.904 21.564 20.976 ;
     RECT  20.401 20.976 21.516 21 ;
     RECT  20.401 21 21.564 21.072 ;
     RECT  20.401 21.072 21.516 21.096 ;
     RECT  20.401 21.096 21.564 21.168 ;
     RECT  20.401 21.168 21.516 21.192 ;
     RECT  20.401 21.192 21.564 21.264 ;
     RECT  20.401 21.264 21.516 21.288 ;
     RECT  20.401 21.288 21.564 21.36 ;
     RECT  20.401 21.36 21.516 21.384 ;
     RECT  20.401 21.384 21.564 21.456 ;
     RECT  20.401 21.456 21.516 21.48 ;
     RECT  20.401 21.48 21.564 21.552 ;
     RECT  20.401 21.552 21.516 21.576 ;
     RECT  20.401 21.576 21.564 21.648 ;
     RECT  20.401 21.648 21.516 21.672 ;
     RECT  20.401 21.672 21.564 21.744 ;
     RECT  20.401 21.744 21.516 21.768 ;
     RECT  20.401 21.768 21.564 21.84 ;
     RECT  20.401 21.84 21.516 21.864 ;
     RECT  20.401 21.864 21.564 21.936 ;
     RECT  20.401 21.936 21.516 21.96 ;
     RECT  20.401 21.96 21.564 22.032 ;
     RECT  20.401 22.032 21.516 22.056 ;
     RECT  20.401 22.056 21.564 22.128 ;
     RECT  20.401 22.128 21.516 22.152 ;
     RECT  20.401 22.152 21.564 22.224 ;
     RECT  20.401 22.224 21.516 22.248 ;
     RECT  20.401 22.248 21.564 22.32 ;
     RECT  20.401 22.32 21.516 22.344 ;
     RECT  20.401 22.344 21.564 22.416 ;
     RECT  20.401 22.416 21.516 22.44 ;
     RECT  20.401 22.44 21.564 22.512 ;
     RECT  20.401 22.512 21.516 22.536 ;
     RECT  20.401 22.536 21.564 22.608 ;
     RECT  20.401 22.608 21.516 22.632 ;
     RECT  20.401 22.632 21.564 22.704 ;
     RECT  20.401 22.704 21.516 22.728 ;
     RECT  20.401 22.728 21.564 22.8 ;
     RECT  20.401 22.8 21.516 22.824 ;
     RECT  20.401 22.824 21.564 22.896 ;
     RECT  20.401 22.896 21.516 22.92 ;
     RECT  20.401 22.92 21.564 22.992 ;
     RECT  20.401 22.992 21.516 23.016 ;
     RECT  20.401 23.016 21.564 23.088 ;
     RECT  20.401 23.088 21.516 23.112 ;
     RECT  20.401 23.112 21.564 23.184 ;
     RECT  20.401 23.184 21.516 23.208 ;
     RECT  20.401 23.208 21.564 23.28 ;
     RECT  20.401 23.28 21.516 23.304 ;
     RECT  20.401 23.304 21.564 23.376 ;
     RECT  20.401 23.376 21.516 23.4 ;
     RECT  20.401 23.4 21.564 23.472 ;
     RECT  20.401 23.472 21.516 23.496 ;
     RECT  20.401 23.496 21.564 23.568 ;
     RECT  20.401 23.568 21.516 23.592 ;
     RECT  20.401 23.592 21.564 23.664 ;
     RECT  20.401 23.664 21.516 23.688 ;
     RECT  20.401 23.688 21.564 23.76 ;
     RECT  20.401 23.76 21.516 23.784 ;
     RECT  20.401 23.784 21.564 23.856 ;
     RECT  20.401 23.856 21.516 23.88 ;
     RECT  20.401 23.88 21.564 23.952 ;
     RECT  20.401 23.952 21.516 23.976 ;
     RECT  20.401 23.976 21.564 24.048 ;
     RECT  20.401 24.048 21.516 24.072 ;
     RECT  20.401 24.072 21.564 24.144 ;
     RECT  20.401 24.144 21.516 24.168 ;
     RECT  20.401 24.168 21.564 24.24 ;
     RECT  20.401 24.24 21.516 24.264 ;
     RECT  20.401 24.264 21.564 24.336 ;
     RECT  20.401 24.336 21.516 24.36 ;
     RECT  20.401 24.36 21.564 24.432 ;
     RECT  20.401 24.432 21.516 24.456 ;
     RECT  20.401 24.456 21.564 24.528 ;
     RECT  20.401 24.528 21.516 24.552 ;
     RECT  20.473 26.064 21.516 26.088 ;
     RECT  20.473 26.088 21.564 26.16 ;
     RECT  20.473 26.16 21.516 26.184 ;
     RECT  20.473 26.184 21.564 26.256 ;
     RECT  20.473 26.256 21.516 26.28 ;
     RECT  20.473 26.28 21.564 26.352 ;
     RECT  20.473 26.352 21.516 26.376 ;
     RECT  20.473 26.376 21.564 26.448 ;
     RECT  20.473 26.448 21.516 26.472 ;
     RECT  20.473 26.472 21.564 26.544 ;
     RECT  20.473 26.544 21.516 26.568 ;
     RECT  20.473 26.568 21.564 26.64 ;
     RECT  20.473 26.64 21.516 26.664 ;
     RECT  20.473 26.664 21.564 26.736 ;
     RECT  20.473 26.736 21.516 26.76 ;
     RECT  20.473 26.76 21.564 26.832 ;
     RECT  20.473 26.832 21.516 26.856 ;
     RECT  20.473 26.856 21.564 26.928 ;
     RECT  20.473 26.928 21.516 26.952 ;
     RECT  20.473 26.952 21.564 27.024 ;
     RECT  20.473 27.024 21.516 27.048 ;
     RECT  20.473 27.048 21.564 27.12 ;
     RECT  20.473 27.12 21.516 27.144 ;
     RECT  20.473 27.144 21.564 27.216 ;
     RECT  20.473 27.216 21.516 27.24 ;
     RECT  20.473 27.24 21.564 27.312 ;
     RECT  20.473 27.312 21.516 27.336 ;
     RECT  20.473 27.336 21.564 27.408 ;
     RECT  20.473 27.408 21.516 27.432 ;
     RECT  20.473 27.432 21.564 27.504 ;
     RECT  20.473 27.504 21.516 27.528 ;
     RECT  20.473 27.528 21.564 27.6 ;
     RECT  20.473 27.6 21.516 27.624 ;
     RECT  20.473 27.624 21.564 27.696 ;
     RECT  20.473 27.696 21.516 27.72 ;
     RECT  20.473 27.72 21.564 27.792 ;
     RECT  20.473 27.792 21.516 27.816 ;
     RECT  20.473 27.816 21.564 27.888 ;
     RECT  20.473 27.888 21.516 27.912 ;
     RECT  20.473 27.912 21.564 27.984 ;
     RECT  20.473 27.984 21.516 28.008 ;
     RECT  20.473 28.008 21.564 28.08 ;
     RECT  20.473 28.08 21.516 28.104 ;
     RECT  20.473 28.104 21.564 28.176 ;
     RECT  20.473 28.176 21.516 28.2 ;
     RECT  20.473 28.2 21.564 28.272 ;
     RECT  20.473 28.272 21.516 28.296 ;
     RECT  20.473 28.296 21.564 28.368 ;
     RECT  20.473 28.368 21.516 28.392 ;
     RECT  20.473 28.392 21.564 28.464 ;
     RECT  20.473 28.464 21.516 28.488 ;
     RECT  20.473 28.488 21.564 28.56 ;
     RECT  20.473 28.56 21.516 28.584 ;
     RECT  20.473 28.584 21.564 28.656 ;
     RECT  20.473 28.656 21.516 28.68 ;
     RECT  20.473 28.68 21.564 28.752 ;
     RECT  20.473 28.752 21.516 28.776 ;
     RECT  20.473 28.776 21.564 28.848 ;
     RECT  20.473 28.848 21.516 28.872 ;
     RECT  20.473 28.872 21.564 28.944 ;
     RECT  20.473 28.944 21.516 28.968 ;
     RECT  20.473 28.968 21.564 29.04 ;
     RECT  20.473 29.04 21.516 29.064 ;
     RECT  20.473 29.064 21.564 29.136 ;
     RECT  20.473 29.136 21.516 29.16 ;
     RECT  20.473 29.16 21.564 29.232 ;
     RECT  20.473 29.232 21.516 29.256 ;
     RECT  20.473 29.256 21.564 29.328 ;
     RECT  20.473 29.328 21.516 29.352 ;
     RECT  20.473 29.352 21.564 29.424 ;
     RECT  20.473 29.424 21.516 29.448 ;
     RECT  20.473 29.448 21.564 29.52 ;
     RECT  20.473 29.52 21.516 29.544 ;
     RECT  20.473 29.544 21.564 29.616 ;
     RECT  20.473 29.616 21.516 29.64 ;
     RECT  20.473 29.64 21.564 29.712 ;
     RECT  20.473 29.712 21.516 29.736 ;
     RECT  20.473 29.736 21.564 29.808 ;
     RECT  20.473 29.808 21.516 29.832 ;
     RECT  20.473 29.832 21.564 29.904 ;
     RECT  20.473 29.904 21.516 29.928 ;
     RECT  20.473 29.928 21.564 30 ;
     RECT  20.473 30 21.516 30.024 ;
     RECT  20.473 30.024 21.564 30.096 ;
     RECT  20.473 30.096 21.516 30.12 ;
     RECT  20.473 30.12 21.564 30.192 ;
     RECT  20.473 30.192 21.516 30.216 ;
     RECT  20.473 30.216 21.564 30.288 ;
     RECT  20.473 30.288 21.516 30.312 ;
     RECT  20.473 30.312 21.564 30.384 ;
     RECT  20.473 30.384 21.516 30.408 ;
     RECT  20.473 30.408 21.564 30.48 ;
     RECT  20.473 30.48 21.516 30.504 ;
     RECT  20.473 30.504 21.564 30.576 ;
     RECT  20.473 30.576 21.516 30.6 ;
     RECT  20.473 30.6 21.564 30.672 ;
     RECT  20.473 30.672 21.516 30.696 ;
     RECT  20.473 30.696 21.564 30.768 ;
     RECT  20.473 30.768 21.516 30.792 ;
     RECT  20.473 30.792 21.564 30.864 ;
     RECT  20.473 30.864 21.516 30.888 ;
     RECT  20.473 30.888 21.564 30.96 ;
     RECT  20.473 30.96 21.516 30.984 ;
     RECT  20.473 30.984 21.564 31.056 ;
     RECT  20.473 31.056 21.516 31.08 ;
     RECT  20.473 31.08 21.564 31.152 ;
     RECT  20.473 31.152 21.516 31.176 ;
     RECT  20.473 31.176 21.564 31.248 ;
     RECT  20.473 31.248 21.516 31.272 ;
     RECT  20.473 31.272 21.564 31.344 ;
     RECT  20.473 31.344 21.516 31.368 ;
     RECT  20.473 31.368 21.564 31.44 ;
     RECT  20.473 31.44 21.516 31.464 ;
     RECT  20.473 31.464 21.564 31.536 ;
     RECT  20.473 31.536 21.516 31.56 ;
     RECT  20.473 31.56 21.564 31.632 ;
     RECT  20.473 31.632 21.516 31.656 ;
     RECT  20.473 31.656 21.564 31.728 ;
     RECT  20.473 31.728 21.516 31.752 ;
     RECT  20.473 31.752 21.564 31.824 ;
     RECT  20.473 31.824 21.516 31.848 ;
     RECT  20.473 31.848 21.564 31.92 ;
     RECT  20.473 31.92 21.516 31.944 ;
     RECT  20.473 31.944 21.564 32.016 ;
     RECT  20.473 32.016 21.516 32.04 ;
     RECT  20.473 32.04 21.564 32.112 ;
     RECT  20.473 32.112 21.516 32.136 ;
    LAYER M5 ;
     RECT  13.032 0.016 13.104 0.084 ;
     RECT  13.008 0.084 13.128 0.085 ;
     RECT  19.008 0.901 19.032 0.997 ;
     RECT  18.288 0.997 19.032 1.093 ;
     RECT  2.4 2.137 2.52 2.151 ;
     RECT  5.1 2.137 5.22 2.151 ;
     RECT  7.8 2.137 7.92 2.151 ;
     RECT  10.5 2.137 10.62 2.151 ;
     RECT  15.9 2.137 16.02 2.151 ;
     RECT  5.1 2.151 5.412 2.245 ;
     RECT  10.5 2.151 10.812 2.245 ;
     RECT  7.8 2.151 8.112 2.581 ;
     RECT  18.288 1.093 19.32 3.013 ;
     RECT  4.56 2.245 5.412 3.443 ;
     RECT  10.224 2.245 10.812 3.541 ;
     RECT  13.008 0.085 13.656 3.589 ;
     RECT  10.224 3.541 10.968 3.875 ;
     RECT  13.008 3.589 14.616 3.971 ;
     RECT  2.4 2.151 2.712 4.501 ;
     RECT  18.24 3.013 19.32 4.595 ;
     RECT  7.8 2.581 8.232 4.691 ;
     RECT  7.8 4.691 8.112 4.693 ;
     RECT  10.224 3.875 10.812 4.981 ;
     RECT  18.288 4.595 19.08 5.171 ;
     RECT  0.144 5.269 0.168 5.555 ;
     RECT  2.4 4.501 3.624 5.747 ;
     RECT  18.336 5.171 19.08 5.747 ;
     RECT  13.008 3.971 13.656 5.749 ;
     RECT  18.6 5.747 19.08 5.845 ;
     RECT  13.008 5.749 13.704 6.035 ;
     RECT  18.6 5.845 19.896 6.035 ;
     RECT  6.864 4.693 8.112 6.275 ;
     RECT  18.6 6.035 19.08 6.323 ;
     RECT  13.008 6.035 13.656 6.371 ;
     RECT  2.4 5.747 2.856 6.707 ;
     RECT  4.752 3.443 5.412 6.805 ;
     RECT  3.984 6.805 5.412 7.187 ;
     RECT  13.008 6.371 13.608 7.379 ;
     RECT  10.032 4.981 10.812 7.475 ;
     RECT  10.5 7.475 10.812 8.293 ;
     RECT  7.8 6.275 8.112 8.437 ;
     RECT  7.392 8.437 8.112 9.155 ;
     RECT  4.224 7.187 5.412 9.347 ;
     RECT  7.8 9.155 8.112 10.069 ;
     RECT  9.12 7.957 9.144 10.069 ;
     RECT  10.5 8.293 11.064 10.693 ;
     RECT  10.368 10.693 11.064 10.739 ;
     RECT  4.752 9.347 5.412 10.883 ;
     RECT  10.368 10.739 10.812 10.981 ;
     RECT  2.4 6.707 2.712 11.317 ;
     RECT  7.8 10.069 9.144 12.133 ;
     RECT  10.272 10.981 10.812 12.133 ;
     RECT  5.1 10.883 5.412 12.469 ;
     RECT  2.4 11.317 2.808 12.515 ;
     RECT  5.1 12.469 5.544 12.517 ;
     RECT  13.008 7.379 13.512 12.517 ;
     RECT  18.6 6.323 18.912 12.517 ;
     RECT  18.6 12.517 19.32 12.755 ;
     RECT  4.464 12.517 5.544 12.757 ;
     RECT  4.464 12.757 6.264 13.715 ;
     RECT  12.864 12.517 13.512 14.243 ;
     RECT  7.8 12.133 10.812 14.867 ;
     RECT  5.1 13.715 6.264 14.915 ;
     RECT  7.8 14.867 9.384 15.443 ;
     RECT  10.5 14.867 10.812 15.829 ;
     RECT  10.368 15.829 10.812 16.021 ;
     RECT  10.368 16.021 10.92 16.355 ;
     RECT  10.368 16.355 10.812 16.547 ;
     RECT  13.008 14.243 13.512 17.077 ;
     RECT  12.96 17.077 13.512 17.219 ;
     RECT  7.8 15.443 8.112 17.557 ;
     RECT  9.168 15.443 9.384 17.557 ;
     RECT  7.8 17.557 9.384 17.651 ;
     RECT  7.8 17.651 9.192 18.037 ;
     RECT  10.5 16.547 10.812 18.133 ;
     RECT  5.1 14.915 5.688 18.181 ;
     RECT  13.104 17.219 13.512 18.181 ;
     RECT  2.4 12.515 2.712 18.469 ;
     RECT  2.4 18.469 2.808 18.707 ;
     RECT  10.5 18.133 11.4 18.709 ;
     RECT  0.144 17.461 0.168 18.995 ;
     RECT  7.44 18.037 9.192 19.091 ;
     RECT  4.32 18.181 5.688 19.093 ;
     RECT  12.96 18.181 13.512 19.093 ;
     RECT  12.96 19.093 14.184 19.237 ;
     RECT  12.96 19.237 14.232 19.379 ;
     RECT  7.8 19.091 9.192 19.427 ;
     RECT  4.32 19.093 6.552 19.619 ;
     RECT  7.8 19.427 8.112 20.389 ;
     RECT  9.168 19.427 9.192 20.389 ;
     RECT  10.5 18.709 11.976 20.531 ;
     RECT  13.056 19.379 14.232 20.581 ;
     RECT  12.336 20.581 14.232 21.251 ;
     RECT  5.1 19.619 6.552 21.683 ;
     RECT  5.1 21.683 5.688 22.259 ;
     RECT  7.8 20.389 9.192 22.259 ;
     RECT  13.056 21.251 14.232 22.883 ;
     RECT  13.056 22.883 13.512 23.653 ;
     RECT  12.816 23.653 13.512 23.939 ;
     RECT  13.2 23.939 13.512 23.941 ;
     RECT  5.1 22.259 5.412 24.181 ;
     RECT  7.8 22.259 8.808 24.323 ;
     RECT  5.1 24.181 5.736 24.325 ;
     RECT  0.144 24.181 0.168 24.467 ;
     RECT  7.8 24.323 8.472 24.515 ;
     RECT  13.2 23.941 14.28 24.659 ;
     RECT  13.2 24.659 13.704 26.147 ;
     RECT  10.5 20.531 11.112 27.205 ;
     RECT  13.2 26.147 13.512 27.301 ;
     RECT  10.32 27.205 11.112 27.683 ;
     RECT  3.936 25.621 3.96 27.875 ;
     RECT  12.528 27.301 13.512 27.923 ;
     RECT  0.144 28.213 0.168 28.499 ;
     RECT  10.5 27.683 11.112 28.595 ;
     RECT  13.2 27.923 13.512 29.029 ;
     RECT  5.1 24.325 6.024 29.699 ;
     RECT  12.096 28.837 12.12 30.227 ;
     RECT  13.2 29.029 13.848 30.563 ;
     RECT  5.1 29.699 5.544 30.659 ;
     RECT  0.144 29.845 0.168 30.805 ;
     RECT  21.408 30.757 21.432 30.947 ;
     RECT  0.144 30.805 0.312 31.955 ;
     RECT  3.744 29.893 3.768 32.051 ;
     RECT  0.144 31.955 0.168 32.243 ;
     RECT  2.4 18.707 2.712 32.409 ;
     RECT  5.1 30.659 5.412 32.409 ;
     RECT  7.8 24.515 8.112 32.409 ;
     RECT  10.5 28.595 10.812 32.409 ;
     RECT  13.2 30.563 13.512 32.409 ;
     RECT  15.9 2.151 16.212 32.409 ;
     RECT  18.6 12.755 18.912 32.409 ;
     RECT  2.4 32.409 2.52 32.423 ;
     RECT  5.1 32.409 5.22 32.423 ;
     RECT  7.8 32.409 7.92 32.423 ;
     RECT  10.5 32.409 10.62 32.423 ;
     RECT  13.2 32.409 13.32 32.423 ;
     RECT  15.9 32.409 16.02 32.423 ;
     RECT  18.6 32.409 18.72 32.423 ;
     RECT  4.56 3.443 4.752 4.501 ;
     RECT  14.616 3.589 15.9 3.971 ;
     RECT  3.624 4.501 4.752 5.747 ;
     RECT  19.08 4.595 19.32 5.845 ;
     RECT  5.412 4.693 6.864 6.275 ;
     RECT  2.856 5.747 4.752 6.707 ;
     RECT  2.712 6.707 4.752 6.805 ;
     RECT  2.712 6.805 3.984 7.187 ;
     RECT  2.712 7.187 4.224 9.347 ;
     RECT  10.032 7.475 10.5 7.957 ;
     RECT  8.112 7.957 9.12 10.069 ;
     RECT  9.144 7.957 10.5 10.693 ;
     RECT  9.144 10.693 10.368 10.981 ;
     RECT  9.144 10.981 10.272 12.133 ;
     RECT  9.384 14.867 10.5 15.829 ;
     RECT  8.112 15.443 9.168 17.557 ;
     RECT  9.384 15.829 10.368 16.547 ;
     RECT  9.384 16.547 10.5 17.651 ;
     RECT  12.96 17.219 13.104 18.181 ;
     RECT  9.192 17.651 10.5 22.259 ;
     RECT  2.808 18.469 4.32 18.707 ;
     RECT  11.976 18.709 12.96 19.379 ;
     RECT  7.44 19.091 7.8 19.093 ;
     RECT  6.552 19.093 7.8 21.683 ;
     RECT  11.976 19.379 13.056 20.531 ;
     RECT  8.112 19.427 9.168 20.389 ;
     RECT  11.112 20.531 13.056 20.581 ;
     RECT  11.112 20.581 12.336 21.251 ;
     RECT  13.512 22.883 14.232 23.941 ;
     RECT  2.712 25.621 3.936 27.875 ;
     RECT  3.96 25.621 5.1 27.875 ;
     RECT  11.112 27.301 12.528 27.923 ;
     RECT  11.112 27.923 13.2 28.595 ;
     RECT  10.812 28.595 13.2 28.837 ;
     RECT  10.812 28.837 12.096 30.227 ;
     RECT  12.12 28.837 13.2 30.227 ;
     RECT  2.712 29.893 3.744 32.051 ;
     RECT  3.768 29.893 5.1 32.051 ;
  END
END hbfd_rly_304_WE_rr
END LIBRARY
